FUNCTION "PMA_KONGSBERG_SORT" : VOID
TITLE = Collect Data for Kongsberg
VERSION : 0.1


VAR_TEMP
  temp_dwd : DWORD ;
END_VAR
BEGIN
NETWORK
TITLE = DG 1 Binary Points
// *** TELEGRAM 1 ***   Block 2
//  PointId = 011010   Binary Point
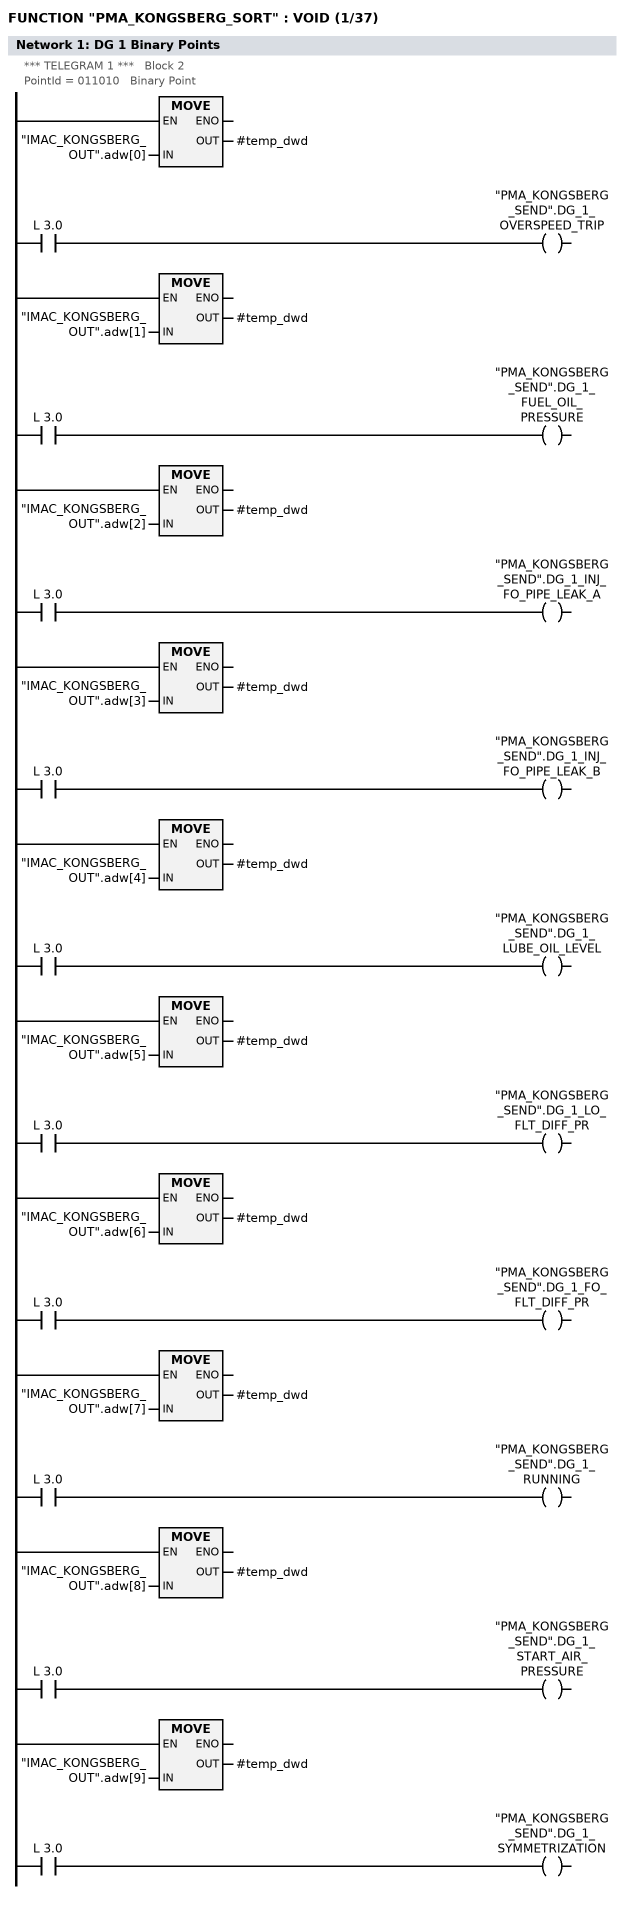
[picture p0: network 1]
      L     "IMAC_KONGSBERG_OUT".adw[0];
      T     #temp_dwd;
      U     L      3.0;
      =     "PMA_KONGSBERG_SEND".DG_1_OVERSPEED_TRIP;


// PointId = 011080   Binary Point
      L     "IMAC_KONGSBERG_OUT".adw[1];
      T     #temp_dwd;
      U     L      3.0;
      =     "PMA_KONGSBERG_SEND".DG_1_FUEL_OIL_PRESSURE;


// PointId = 011160   Binary Point
      L     "IMAC_KONGSBERG_OUT".adw[2];
      T     #temp_dwd;
      U     L      3.0;
      =     "PMA_KONGSBERG_SEND".DG_1_INJ_FO_PIPE_LEAK_A;


// PointId = 011170   Binary Point
      L     "IMAC_KONGSBERG_OUT".adw[3];
      T     #temp_dwd;
      U     L      3.0;
      =     "PMA_KONGSBERG_SEND".DG_1_INJ_FO_PIPE_LEAK_B;


// PointId = 011180   Binary Point
      L     "IMAC_KONGSBERG_OUT".adw[4];
      T     #temp_dwd;
      U     L      3.0;
      =     "PMA_KONGSBERG_SEND".DG_1_LUBE_OIL_LEVEL;


// PointId = 011200   Binary Point
      L     "IMAC_KONGSBERG_OUT".adw[5];
      T     #temp_dwd;
      U     L      3.0;
      =     "PMA_KONGSBERG_SEND".DG_1_LO_FLT_DIFF_PR;


// PointId = 011210   Binary Point
      L     "IMAC_KONGSBERG_OUT".adw[6];
      T     #temp_dwd;
      U     L      3.0;
      =     "PMA_KONGSBERG_SEND".DG_1_FO_FLT_DIFF_PR;


// PointId = 011030   Binary Point
      L     "IMAC_KONGSBERG_OUT".adw[7];
      T     #temp_dwd;
      U     L      3.0;
      =     "PMA_KONGSBERG_SEND".DG_1_RUNNING;


// PointId = 011190   Binary Point
      L     "IMAC_KONGSBERG_OUT".adw[8];
      T     #temp_dwd;
      U     L      3.0;
      =     "PMA_KONGSBERG_SEND".DG_1_START_AIR_PRESSURE;


// PointId = 011570   Binary Point
      L     "IMAC_KONGSBERG_OUT".adw[9];
      T     #temp_dwd;
      U     L      3.0;
      =     "PMA_KONGSBERG_SEND".DG_1_SYMMETRIZATION;


NETWORK
TITLE = DG 1 Analogue Points

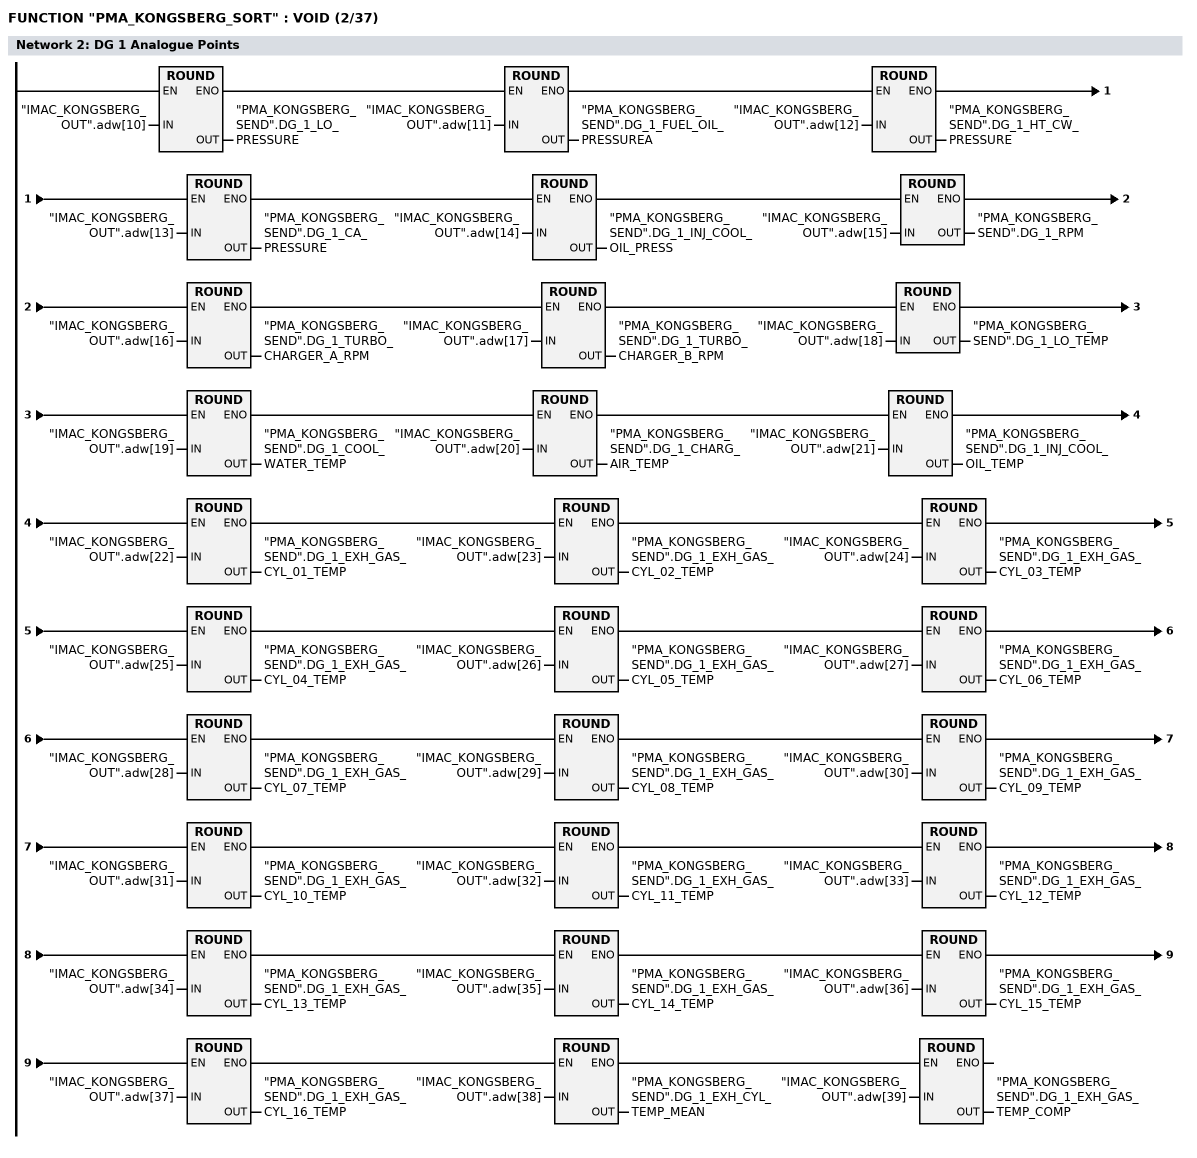
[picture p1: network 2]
// PointId = 011060   Analogue Point
      L     "IMAC_KONGSBERG_OUT".adw[10];
      RND   ;
      T     "PMA_KONGSBERG_SEND".DG_1_LO_PRESSURE;


// PointId = 011080   Analogue Point
      L     "IMAC_KONGSBERG_OUT".adw[11];
      RND   ;
      T     "PMA_KONGSBERG_SEND".DG_1_FUEL_OIL_PRESSUREA;


// PointId = 011090   Analogue Point
      L     "IMAC_KONGSBERG_OUT".adw[12];
      RND   ;
      T     "PMA_KONGSBERG_SEND".DG_1_HT_CW_PRESSURE;


// PointId = 011110   Analogue Point
      L     "IMAC_KONGSBERG_OUT".adw[13];
      RND   ;
      T     "PMA_KONGSBERG_SEND".DG_1_CA_PRESSURE;


// PointId = 011130   Analogue Point
      L     "IMAC_KONGSBERG_OUT".adw[14];
      RND   ;
      T     "PMA_KONGSBERG_SEND".DG_1_INJ_COOL_OIL_PRESS;


// PointId = 011020   Analogue Point
      L     "IMAC_KONGSBERG_OUT".adw[15];
      RND   ;
      T     "PMA_KONGSBERG_SEND".DG_1_RPM;


// PointId = 011040   Analogue Point
      L     "IMAC_KONGSBERG_OUT".adw[16];
      RND   ;
      T     "PMA_KONGSBERG_SEND".DG_1_TURBO_CHARGER_A_RPM;


// PointId = 011050   Analogue Point
      L     "IMAC_KONGSBERG_OUT".adw[17];
      RND   ;
      T     "PMA_KONGSBERG_SEND".DG_1_TURBO_CHARGER_B_RPM;


// PointId = 011070   Analogue Point
      L     "IMAC_KONGSBERG_OUT".adw[18];
      RND   ;
      T     "PMA_KONGSBERG_SEND".DG_1_LO_TEMP;


// PointId = 011100   Analogue Point
      L     "IMAC_KONGSBERG_OUT".adw[19];
      RND   ;
      T     "PMA_KONGSBERG_SEND".DG_1_COOL_WATER_TEMP;


// PointId = 011120   Analogue Point
      L     "IMAC_KONGSBERG_OUT".adw[20];
      RND   ;
      T     "PMA_KONGSBERG_SEND".DG_1_CHARG_AIR_TEMP;


// PointId = 011140   Analogue Point
      L     "IMAC_KONGSBERG_OUT".adw[21];
      RND   ;
      T     "PMA_KONGSBERG_SEND".DG_1_INJ_COOL_OIL_TEMP;


// PointId = 011230   Analogue Point
      L     "IMAC_KONGSBERG_OUT".adw[22];
      RND   ;
      T     "PMA_KONGSBERG_SEND".DG_1_EXH_GAS_CYL_01_TEMP;


// PointId = 011240   Analogue Point
      L     "IMAC_KONGSBERG_OUT".adw[23];
      RND   ;
      T     "PMA_KONGSBERG_SEND".DG_1_EXH_GAS_CYL_02_TEMP;


// PointId = 011250   Analogue Point
      L     "IMAC_KONGSBERG_OUT".adw[24];
      RND   ;
      T     "PMA_KONGSBERG_SEND".DG_1_EXH_GAS_CYL_03_TEMP;


// PointId = 011260   Analogue Point
      L     "IMAC_KONGSBERG_OUT".adw[25];
      RND   ;
      T     "PMA_KONGSBERG_SEND".DG_1_EXH_GAS_CYL_04_TEMP;


// PointId = 011270   Analogue Point
      L     "IMAC_KONGSBERG_OUT".adw[26];
      RND   ;
      T     "PMA_KONGSBERG_SEND".DG_1_EXH_GAS_CYL_05_TEMP;


// PointId = 011280   Analogue Point
      L     "IMAC_KONGSBERG_OUT".adw[27];
      RND   ;
      T     "PMA_KONGSBERG_SEND".DG_1_EXH_GAS_CYL_06_TEMP;


// PointId = 011290   Analogue Point
      L     "IMAC_KONGSBERG_OUT".adw[28];
      RND   ;
      T     "PMA_KONGSBERG_SEND".DG_1_EXH_GAS_CYL_07_TEMP;


// PointId = 011300   Analogue Point
      L     "IMAC_KONGSBERG_OUT".adw[29];
      RND   ;
      T     "PMA_KONGSBERG_SEND".DG_1_EXH_GAS_CYL_08_TEMP;


// PointId = 011310   Analogue Point
      L     "IMAC_KONGSBERG_OUT".adw[30];
      RND   ;
      T     "PMA_KONGSBERG_SEND".DG_1_EXH_GAS_CYL_09_TEMP;


// PointId = 011320   Analogue Point
      L     "IMAC_KONGSBERG_OUT".adw[31];
      RND   ;
      T     "PMA_KONGSBERG_SEND".DG_1_EXH_GAS_CYL_10_TEMP;


// PointId = 011330   Analogue Point
      L     "IMAC_KONGSBERG_OUT".adw[32];
      RND   ;
      T     "PMA_KONGSBERG_SEND".DG_1_EXH_GAS_CYL_11_TEMP;


// PointId = 011340   Analogue Point
      L     "IMAC_KONGSBERG_OUT".adw[33];
      RND   ;
      T     "PMA_KONGSBERG_SEND".DG_1_EXH_GAS_CYL_12_TEMP;


// PointId = 011350   Analogue Point
      L     "IMAC_KONGSBERG_OUT".adw[34];
      RND   ;
      T     "PMA_KONGSBERG_SEND".DG_1_EXH_GAS_CYL_13_TEMP;


// PointId = 011360   Analogue Point
      L     "IMAC_KONGSBERG_OUT".adw[35];
      RND   ;
      T     "PMA_KONGSBERG_SEND".DG_1_EXH_GAS_CYL_14_TEMP;


// PointId = 011370   Analogue Point
      L     "IMAC_KONGSBERG_OUT".adw[36];
      RND   ;
      T     "PMA_KONGSBERG_SEND".DG_1_EXH_GAS_CYL_15_TEMP;


// PointId = 011380   Analogue Point
      L     "IMAC_KONGSBERG_OUT".adw[37];
      RND   ;
      T     "PMA_KONGSBERG_SEND".DG_1_EXH_GAS_CYL_16_TEMP;


// PointId = 011550   Analogue Point
      L     "IMAC_KONGSBERG_OUT".adw[38];
      RND   ;
      T     "PMA_KONGSBERG_SEND".DG_1_EXH_CYL_TEMP_MEAN;


// PointId = 011560   Analogue Point
      L     "IMAC_KONGSBERG_OUT".adw[39];
      RND   ;
      T     "PMA_KONGSBERG_SEND".DG_1_EXH_GAS_TEMP_COMP;
NETWORK
TITLE = DG 2 Binary Points
// *** TELEGRAM 1 ***   Block 3
//  PointId = 012010   Binary Point
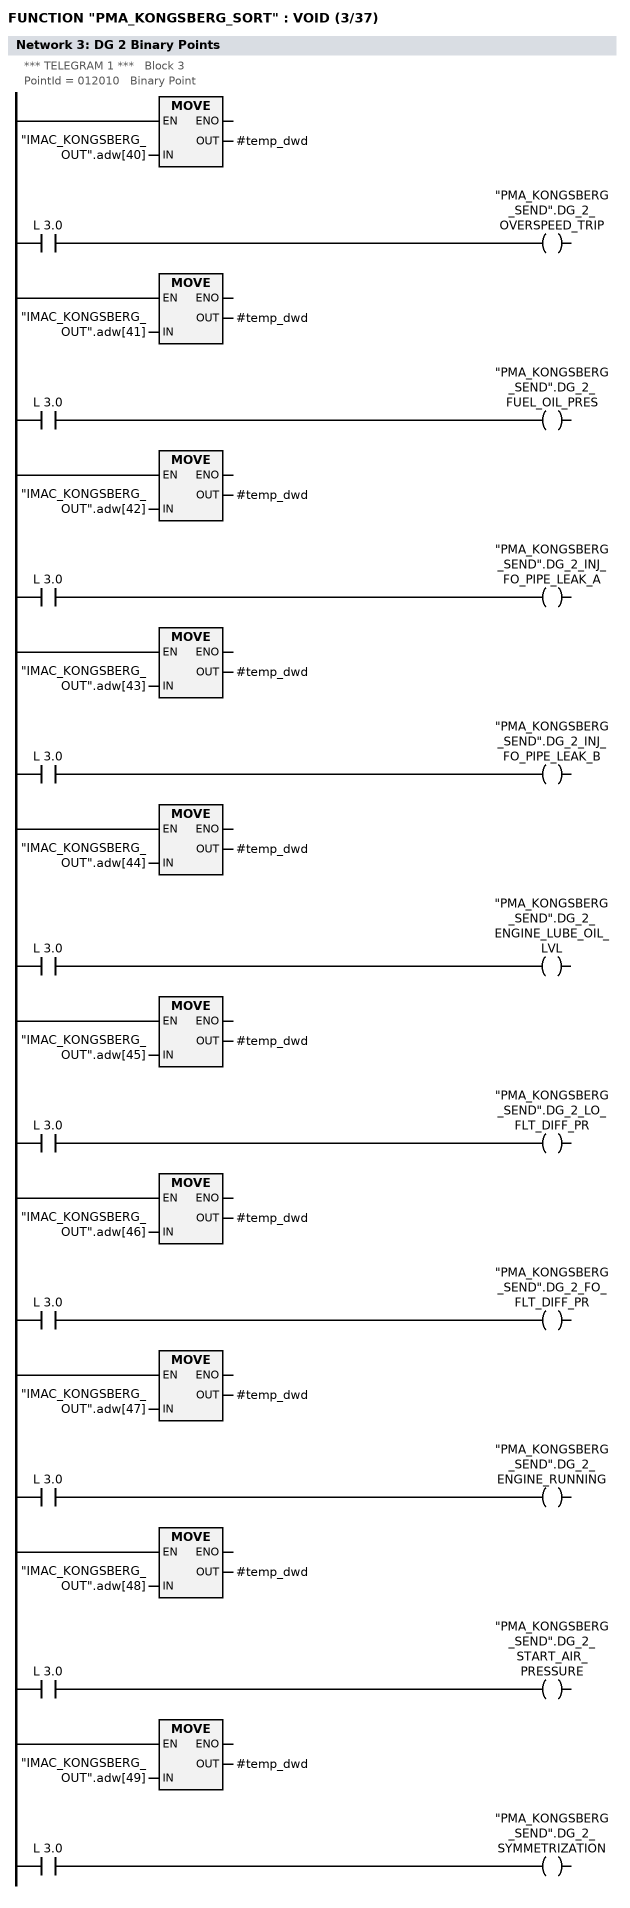
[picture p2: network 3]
      L     "IMAC_KONGSBERG_OUT".adw[40];
      T     #temp_dwd;
      U     L      3.0;
      =     "PMA_KONGSBERG_SEND".DG_2_OVERSPEED_TRIP;


// PointId = 012080   Binary Point
      L     "IMAC_KONGSBERG_OUT".adw[41];
      T     #temp_dwd;
      U     L      3.0;
      =     "PMA_KONGSBERG_SEND".DG_2_FUEL_OIL_PRES;


// PointId = 012160   Binary Point
      L     "IMAC_KONGSBERG_OUT".adw[42];
      T     #temp_dwd;
      U     L      3.0;
      =     "PMA_KONGSBERG_SEND".DG_2_INJ_FO_PIPE_LEAK_A;


// PointId = 012170   Binary Point
      L     "IMAC_KONGSBERG_OUT".adw[43];
      T     #temp_dwd;
      U     L      3.0;
      =     "PMA_KONGSBERG_SEND".DG_2_INJ_FO_PIPE_LEAK_B;


// PointId = 012180   Binary Point
      L     "IMAC_KONGSBERG_OUT".adw[44];
      T     #temp_dwd;
      U     L      3.0;
      =     "PMA_KONGSBERG_SEND".DG_2_ENGINE_LUBE_OIL_LVL;


// PointId = 012200   Binary Point
      L     "IMAC_KONGSBERG_OUT".adw[45];
      T     #temp_dwd;
      U     L      3.0;
      =     "PMA_KONGSBERG_SEND".DG_2_LO_FLT_DIFF_PR;


// PointId = 012210   Binary Point
      L     "IMAC_KONGSBERG_OUT".adw[46];
      T     #temp_dwd;
      U     L      3.0;
      =     "PMA_KONGSBERG_SEND".DG_2_FO_FLT_DIFF_PR;


// PointId = 012030   Binary Point
      L     "IMAC_KONGSBERG_OUT".adw[47];
      T     #temp_dwd;
      U     L      3.0;
      =     "PMA_KONGSBERG_SEND".DG_2_ENGINE_RUNNING;


// PointId = 012190   Binary Point
      L     "IMAC_KONGSBERG_OUT".adw[48];
      T     #temp_dwd;
      U     L      3.0;
      =     "PMA_KONGSBERG_SEND".DG_2_START_AIR_PRESSURE;


// PointId = 012570   Binary Point
      L     "IMAC_KONGSBERG_OUT".adw[49];
      T     #temp_dwd;
      U     L      3.0;
      =     "PMA_KONGSBERG_SEND".DG_2_SYMMETRIZATION;
NETWORK
TITLE = DG 2 Analogue Points

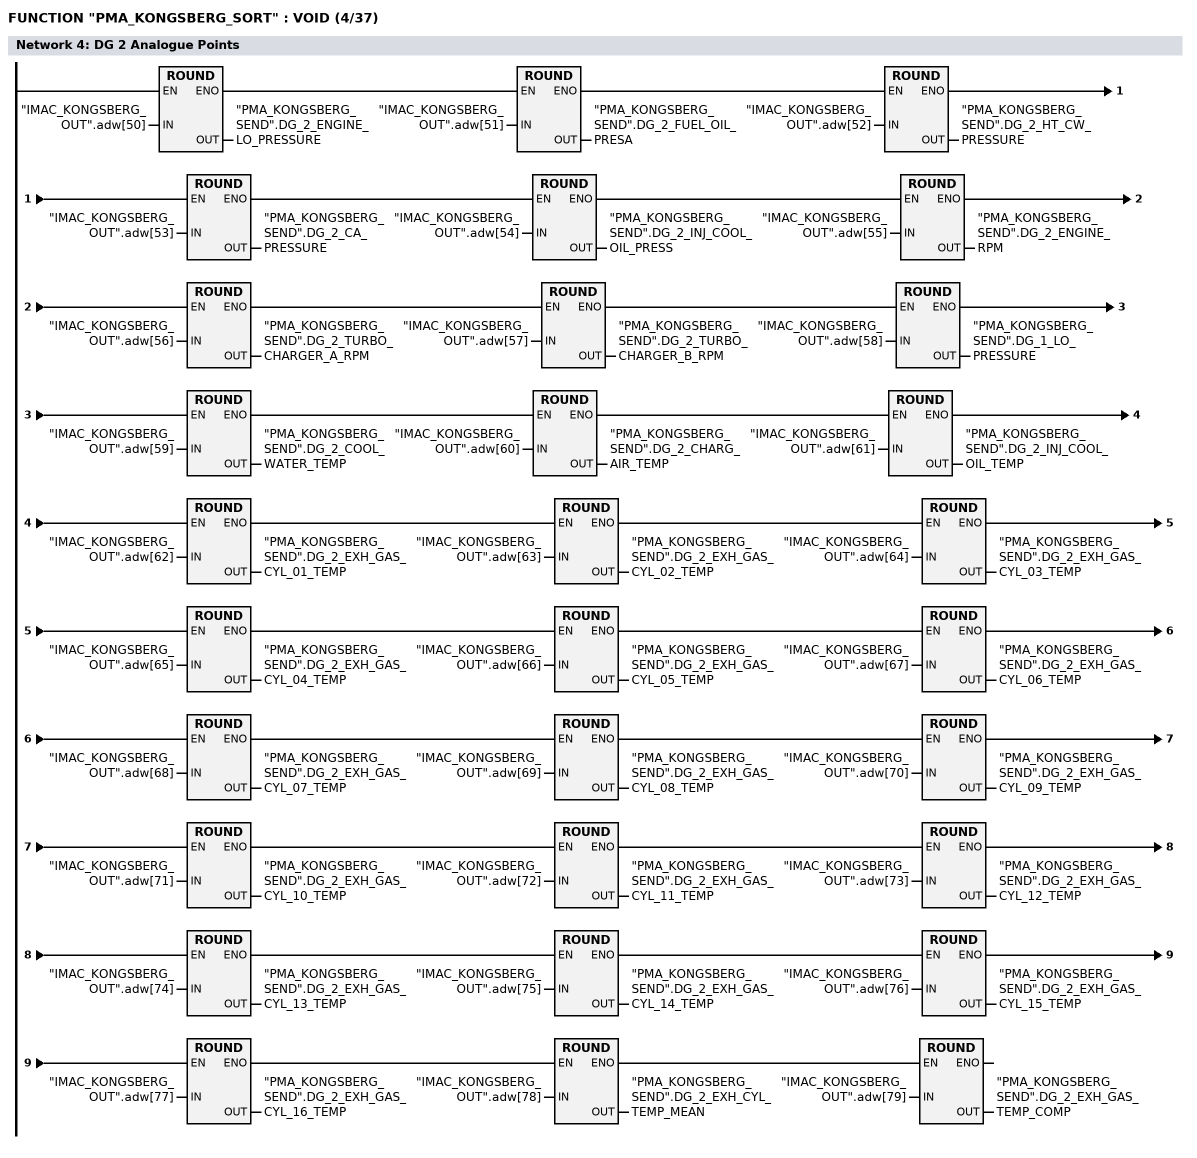
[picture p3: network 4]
//  PointId = 012060   Analogue Point
      L     "IMAC_KONGSBERG_OUT".adw[50];
      RND   ;
      T     "PMA_KONGSBERG_SEND".DG_2_ENGINE_LO_PRESSURE;


// PointId = 012080   Analogue Point
      L     "IMAC_KONGSBERG_OUT".adw[51];
      RND   ;
      T     "PMA_KONGSBERG_SEND".DG_2_FUEL_OIL_PRESA;


// PointId = 012090   Analogue Point
      L     "IMAC_KONGSBERG_OUT".adw[52];
      RND   ;
      T     "PMA_KONGSBERG_SEND".DG_2_HT_CW_PRESSURE;


// PointId = 012110   Analogue Point
      L     "IMAC_KONGSBERG_OUT".adw[53];
      RND   ;
      T     "PMA_KONGSBERG_SEND".DG_2_CA_PRESSURE;


// PointId = 012130   Analogue Point
      L     "IMAC_KONGSBERG_OUT".adw[54];
      RND   ;
      T     "PMA_KONGSBERG_SEND".DG_2_INJ_COOL_OIL_PRESS;


// PointId = 012020   Analogue Point
      L     "IMAC_KONGSBERG_OUT".adw[55];
      RND   ;
      T     "PMA_KONGSBERG_SEND".DG_2_ENGINE_RPM;


// PointId = 012040   Analogue Point
      L     "IMAC_KONGSBERG_OUT".adw[56];
      RND   ;
      T     "PMA_KONGSBERG_SEND".DG_2_TURBO_CHARGER_A_RPM;


// PointId = 012050   Analogue Point
      L     "IMAC_KONGSBERG_OUT".adw[57];
      RND   ;
      T     "PMA_KONGSBERG_SEND".DG_2_TURBO_CHARGER_B_RPM;


// PointId = 012070   Analogue Point
      L     "IMAC_KONGSBERG_OUT".adw[58];
      RND   ;
      T     "PMA_KONGSBERG_SEND".DG_1_LO_PRESSURE;


// PointId = 012100   Analogue Point
      L     "IMAC_KONGSBERG_OUT".adw[59];
      RND   ;
      T     "PMA_KONGSBERG_SEND".DG_2_COOL_WATER_TEMP;


// PointId = 012120   Analogue Point
      L     "IMAC_KONGSBERG_OUT".adw[60];
      RND   ;
      T     "PMA_KONGSBERG_SEND".DG_2_CHARG_AIR_TEMP;


// PointId = 012140   Analogue Point
      L     "IMAC_KONGSBERG_OUT".adw[61];
      RND   ;
      T     "PMA_KONGSBERG_SEND".DG_2_INJ_COOL_OIL_TEMP;


// PointId = 012230   Analogue Point
      L     "IMAC_KONGSBERG_OUT".adw[62];
      RND   ;
      T     "PMA_KONGSBERG_SEND".DG_2_EXH_GAS_CYL_01_TEMP;


// PointId = 012240   Analogue Point
      L     "IMAC_KONGSBERG_OUT".adw[63];
      RND   ;
      T     "PMA_KONGSBERG_SEND".DG_2_EXH_GAS_CYL_02_TEMP;


// PointId = 012250   Analogue Point
      L     "IMAC_KONGSBERG_OUT".adw[64];
      RND   ;
      T     "PMA_KONGSBERG_SEND".DG_2_EXH_GAS_CYL_03_TEMP;


// PointId = 012260   Analogue Point
      L     "IMAC_KONGSBERG_OUT".adw[65];
      RND   ;
      T     "PMA_KONGSBERG_SEND".DG_2_EXH_GAS_CYL_04_TEMP;


// PointId = 012270   Analogue Point
      L     "IMAC_KONGSBERG_OUT".adw[66];
      RND   ;
      T     "PMA_KONGSBERG_SEND".DG_2_EXH_GAS_CYL_05_TEMP;


// PointId = 012280   Analogue Point
      L     "IMAC_KONGSBERG_OUT".adw[67];
      RND   ;
      T     "PMA_KONGSBERG_SEND".DG_2_EXH_GAS_CYL_06_TEMP;


// PointId = 012290   Analogue Point
      L     "IMAC_KONGSBERG_OUT".adw[68];
      RND   ;
      T     "PMA_KONGSBERG_SEND".DG_2_EXH_GAS_CYL_07_TEMP;


// PointId = 012300   Analogue Point
      L     "IMAC_KONGSBERG_OUT".adw[69];
      RND   ;
      T     "PMA_KONGSBERG_SEND".DG_2_EXH_GAS_CYL_08_TEMP;


// PointId = 012310   Analogue Point
      L     "IMAC_KONGSBERG_OUT".adw[70];
      RND   ;
      T     "PMA_KONGSBERG_SEND".DG_2_EXH_GAS_CYL_09_TEMP;


// PointId = 012320   Analogue Point
      L     "IMAC_KONGSBERG_OUT".adw[71];
      RND   ;
      T     "PMA_KONGSBERG_SEND".DG_2_EXH_GAS_CYL_10_TEMP;


// PointId = 012330   Analogue Point
      L     "IMAC_KONGSBERG_OUT".adw[72];
      RND   ;
      T     "PMA_KONGSBERG_SEND".DG_2_EXH_GAS_CYL_11_TEMP;


// PointId = 012340   Analogue Point
      L     "IMAC_KONGSBERG_OUT".adw[73];
      RND   ;
      T     "PMA_KONGSBERG_SEND".DG_2_EXH_GAS_CYL_12_TEMP;


// PointId = 012350   Analogue Point
      L     "IMAC_KONGSBERG_OUT".adw[74];
      RND   ;
      T     "PMA_KONGSBERG_SEND".DG_2_EXH_GAS_CYL_13_TEMP;


// PointId = 012360   Analogue Point
      L     "IMAC_KONGSBERG_OUT".adw[75];
      RND   ;
      T     "PMA_KONGSBERG_SEND".DG_2_EXH_GAS_CYL_14_TEMP;


// PointId = 012370   Analogue Point
      L     "IMAC_KONGSBERG_OUT".adw[76];
      RND   ;
      T     "PMA_KONGSBERG_SEND".DG_2_EXH_GAS_CYL_15_TEMP;


// PointId = 012380   Analogue Point
      L     "IMAC_KONGSBERG_OUT".adw[77];
      RND   ;
      T     "PMA_KONGSBERG_SEND".DG_2_EXH_GAS_CYL_16_TEMP;


// PointId = 012550   Analogue Point
      L     "IMAC_KONGSBERG_OUT".adw[78];
      RND   ;
      T     "PMA_KONGSBERG_SEND".DG_2_EXH_CYL_TEMP_MEAN;


// PointId = 012560   Analogue Point
      L     "IMAC_KONGSBERG_OUT".adw[79];
      RND   ;
      T     "PMA_KONGSBERG_SEND".DG_2_EXH_GAS_TEMP_COMP;
NETWORK
TITLE = GEN 1 Analogue Points
// *** TELEGRAM 1 ***   Block 4
// PointId = 021010   Analogue Point
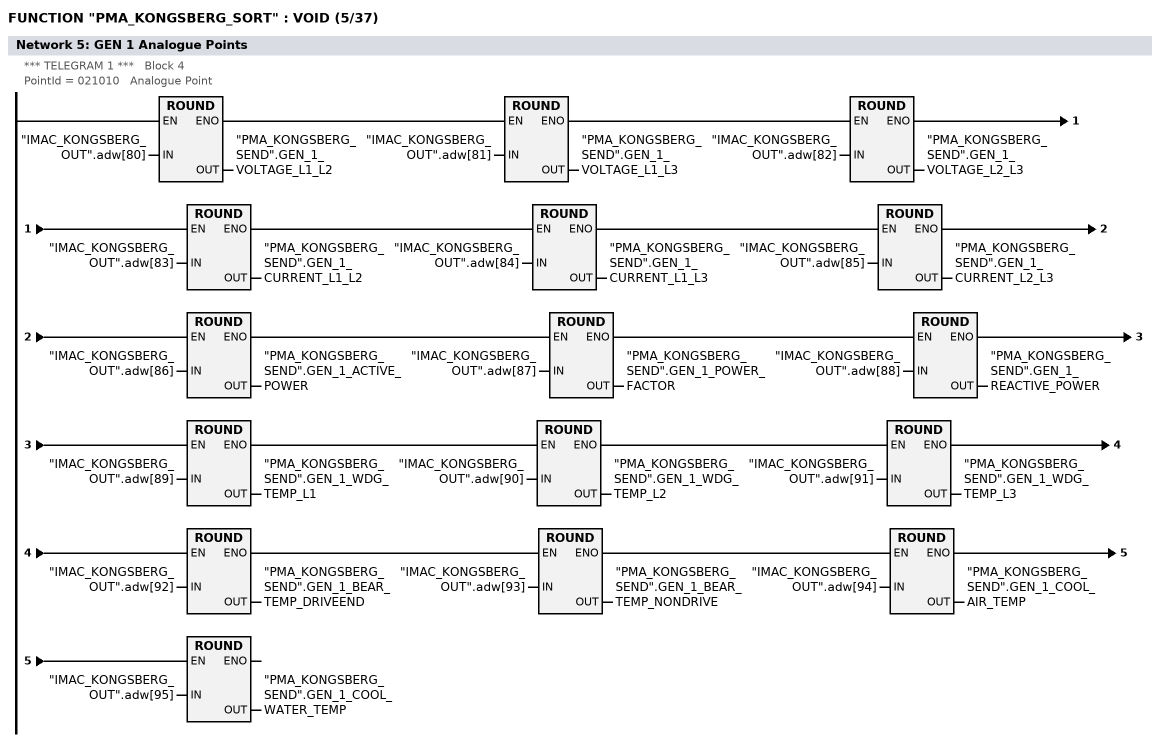
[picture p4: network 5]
      L     "IMAC_KONGSBERG_OUT".adw[80];
      RND   ;
      T     "PMA_KONGSBERG_SEND".GEN_1_VOLTAGE_L1_L2;


// PointId = 021020   Analogue Point
      L     "IMAC_KONGSBERG_OUT".adw[81];
      RND   ;
      T     "PMA_KONGSBERG_SEND".GEN_1_VOLTAGE_L1_L3;


// PointId = 021030   Analogue Point
      L     "IMAC_KONGSBERG_OUT".adw[82];
      RND   ;
      T     "PMA_KONGSBERG_SEND".GEN_1_VOLTAGE_L2_L3;


// PointId = 021040   Analogue Point
      L     "IMAC_KONGSBERG_OUT".adw[83];
      RND   ;
      T     "PMA_KONGSBERG_SEND".GEN_1_CURRENT_L1_L2;


// PointId = 021051   Analogue Point
      L     "IMAC_KONGSBERG_OUT".adw[84];
      RND   ;
      T     "PMA_KONGSBERG_SEND".GEN_1_CURRENT_L1_L3;


// PointId = 021060   Analogue Point
      L     "IMAC_KONGSBERG_OUT".adw[85];
      RND   ;
      T     "PMA_KONGSBERG_SEND".GEN_1_CURRENT_L2_L3;


// PointId = 021070   Analogue Point
      L     "IMAC_KONGSBERG_OUT".adw[86];
      RND   ;
      T     "PMA_KONGSBERG_SEND".GEN_1_ACTIVE_POWER;


// PointId = 021080   Analogue Point
      L     "IMAC_KONGSBERG_OUT".adw[87];
      RND   ;
      T     "PMA_KONGSBERG_SEND".GEN_1_POWER_FACTOR;


// PointId = 021090   Analogue Point
      L     "IMAC_KONGSBERG_OUT".adw[88];
      RND   ;
      T     "PMA_KONGSBERG_SEND".GEN_1_REACTIVE_POWER;


// PointId = 021120   Analogue Point
      L     "IMAC_KONGSBERG_OUT".adw[89];
      RND   ;
      T     "PMA_KONGSBERG_SEND".GEN_1_WDG_TEMP_L1;


// PointId = 021130   Analogue Point
      L     "IMAC_KONGSBERG_OUT".adw[90];
      RND   ;
      T     "PMA_KONGSBERG_SEND".GEN_1_WDG_TEMP_L2;


// PointId = 021140   Analogue Point
      L     "IMAC_KONGSBERG_OUT".adw[91];
      RND   ;
      T     "PMA_KONGSBERG_SEND".GEN_1_WDG_TEMP_L3;


// PointId = 021150   Analogue Point
      L     "IMAC_KONGSBERG_OUT".adw[92];
      RND   ;
      T     "PMA_KONGSBERG_SEND".GEN_1_BEAR_TEMP_DRIVEEND;


// PointId = 021160   Analogue Point
      L     "IMAC_KONGSBERG_OUT".adw[93];
      RND   ;
      T     "PMA_KONGSBERG_SEND".GEN_1_BEAR_TEMP_NONDRIVE;


// PointId = 021170   Analogue Point
      L     "IMAC_KONGSBERG_OUT".adw[94];
      RND   ;
      T     "PMA_KONGSBERG_SEND".GEN_1_COOL_AIR_TEMP;


// PointId = 021180   Analogue Point
      L     "IMAC_KONGSBERG_OUT".adw[95];
      RND   ;
      T     "PMA_KONGSBERG_SEND".GEN_1_COOL_WATER_TEMP;
NETWORK
TITLE = GEN 1 Binary Points
// *** TELEGRAM 1 ***   Block 5
// PointId = 021100   Binary Point
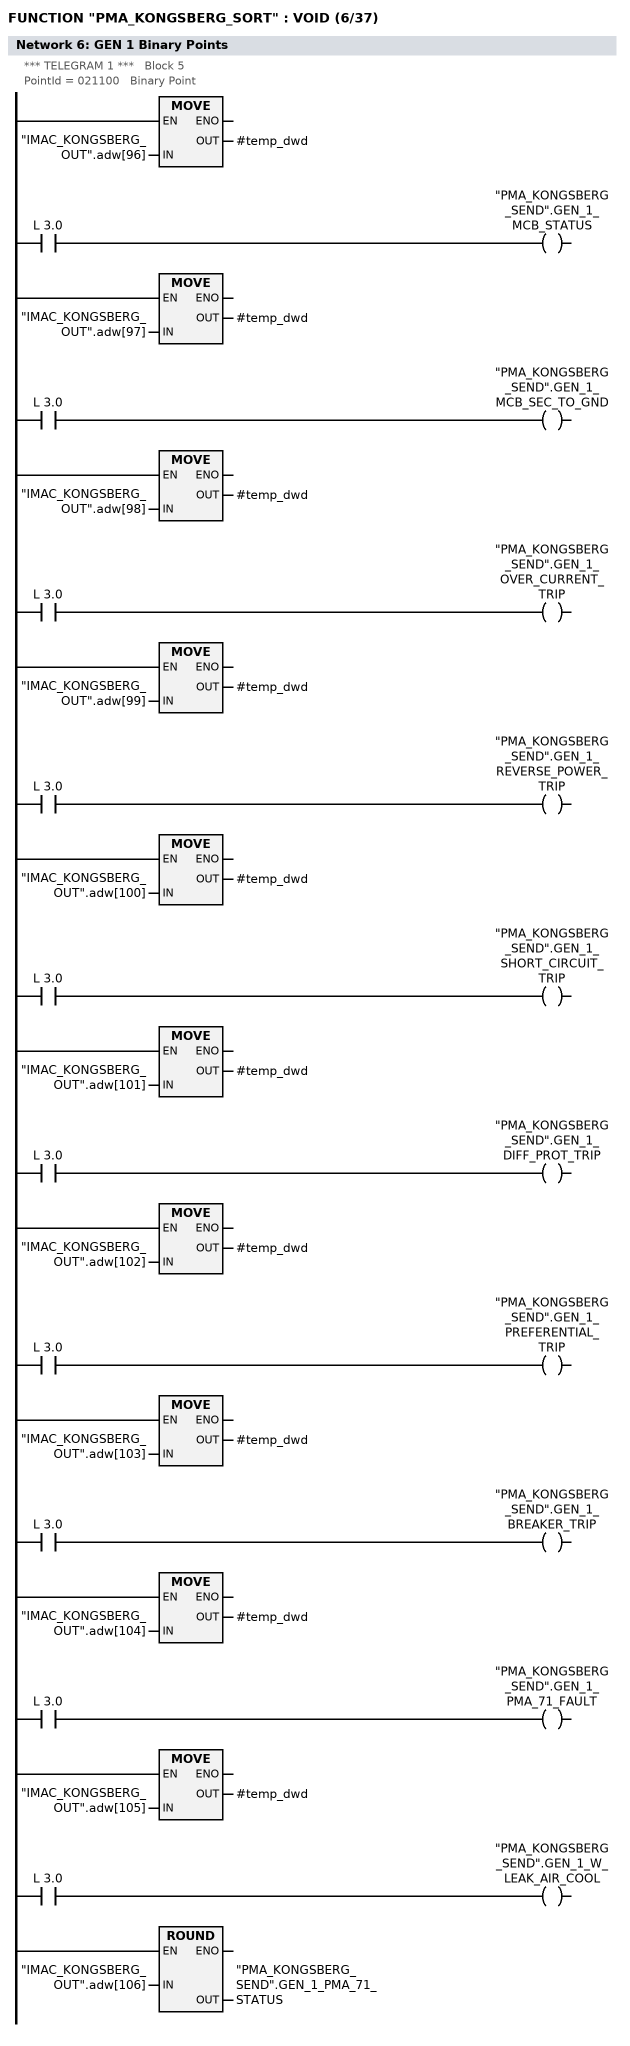
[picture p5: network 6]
      L     "IMAC_KONGSBERG_OUT".adw[96];
      T     #temp_dwd;
      U     L      3.0;
      =     "PMA_KONGSBERG_SEND".GEN_1_MCB_STATUS;


// PointId = 021110   Binary Point
      L     "IMAC_KONGSBERG_OUT".adw[97];
      T     #temp_dwd;
      U     L      3.0;
      =     "PMA_KONGSBERG_SEND".GEN_1_MCB_SEC_TO_GND;


// PointId = 021190   Binary Point
      L     "IMAC_KONGSBERG_OUT".adw[98];
      T     #temp_dwd;
      U     L      3.0;
      =     "PMA_KONGSBERG_SEND".GEN_1_OVER_CURRENT_TRIP;


// PointId = 021200   Binary Point
      L     "IMAC_KONGSBERG_OUT".adw[99];
      T     #temp_dwd;
      U     L      3.0;
      =     "PMA_KONGSBERG_SEND".GEN_1_REVERSE_POWER_TRIP;


// PointId = 021210   Binary Point
      L     "IMAC_KONGSBERG_OUT".adw[100];
      T     #temp_dwd;
      U     L      3.0;
      =     "PMA_KONGSBERG_SEND".GEN_1_SHORT_CIRCUIT_TRIP;


// PointId = 021240   Binary Point
      L     "IMAC_KONGSBERG_OUT".adw[101];
      T     #temp_dwd;
      U     L      3.0;
      =     "PMA_KONGSBERG_SEND".GEN_1_DIFF_PROT_TRIP;


// PointId = 021260   Binary Point
      L     "IMAC_KONGSBERG_OUT".adw[102];
      T     #temp_dwd;
      U     L      3.0;
      =     "PMA_KONGSBERG_SEND".GEN_1_PREFERENTIAL_TRIP;


// PointId = 021270   Binary Point
      L     "IMAC_KONGSBERG_OUT".adw[103];
      T     #temp_dwd;
      U     L      3.0;
      =     "PMA_KONGSBERG_SEND".GEN_1_BREAKER_TRIP;


// PointId = 021290   Binary Point
      L     "IMAC_KONGSBERG_OUT".adw[104];
      T     #temp_dwd;
      U     L      3.0;
      =     "PMA_KONGSBERG_SEND".GEN_1_PMA_71_FAULT;


// PointId = 021310   Binary Point
      L     "IMAC_KONGSBERG_OUT".adw[105];
      T     #temp_dwd;
      U     L      3.0;
      =     "PMA_KONGSBERG_SEND".GEN_1_W_LEAK_AIR_COOL;


// PointId = 021300   Analogue Point
      L     "IMAC_KONGSBERG_OUT".adw[106];
      RND   ;
      T     "PMA_KONGSBERG_SEND".GEN_1_PMA_71_STATUS;
NETWORK
TITLE = GEN 2 Analogue Points
//  *** TELEGRAM 1 ***   Block 6
// PointId = 022010   Analogue Point
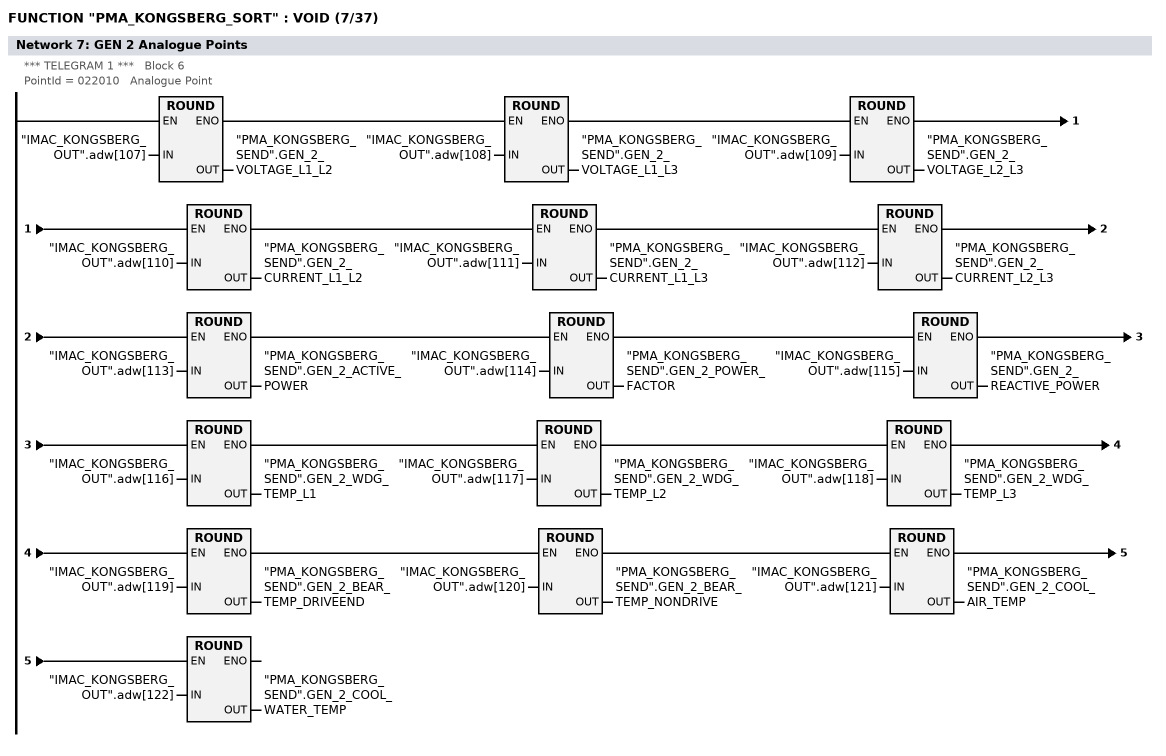
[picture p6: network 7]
      L     "IMAC_KONGSBERG_OUT".adw[107];
      RND   ;
      T     "PMA_KONGSBERG_SEND".GEN_2_VOLTAGE_L1_L2;


// PointId = 022020   Analogue Point
      L     "IMAC_KONGSBERG_OUT".adw[108];
      RND   ;
      T     "PMA_KONGSBERG_SEND".GEN_2_VOLTAGE_L1_L3;


// PointId = 022030   Analogue Point
      L     "IMAC_KONGSBERG_OUT".adw[109];
      RND   ;
      T     "PMA_KONGSBERG_SEND".GEN_2_VOLTAGE_L2_L3;


// PointId = 022040   Analogue Point
      L     "IMAC_KONGSBERG_OUT".adw[110];
      RND   ;
      T     "PMA_KONGSBERG_SEND".GEN_2_CURRENT_L1_L2;


// PointId = 022051   Analogue Point
      L     "IMAC_KONGSBERG_OUT".adw[111];
      RND   ;
      T     "PMA_KONGSBERG_SEND".GEN_2_CURRENT_L1_L3;


// PointId = 022060   Analogue Point
      L     "IMAC_KONGSBERG_OUT".adw[112];
      RND   ;
      T     "PMA_KONGSBERG_SEND".GEN_2_CURRENT_L2_L3;


// PointId = 022070   Analogue Point
      L     "IMAC_KONGSBERG_OUT".adw[113];
      RND   ;
      T     "PMA_KONGSBERG_SEND".GEN_2_ACTIVE_POWER;


// PointId = 022080   Analogue Point
      L     "IMAC_KONGSBERG_OUT".adw[114];
      RND   ;
      T     "PMA_KONGSBERG_SEND".GEN_2_POWER_FACTOR;


// PointId = 022090   Analogue Point
      L     "IMAC_KONGSBERG_OUT".adw[115];
      RND   ;
      T     "PMA_KONGSBERG_SEND".GEN_2_REACTIVE_POWER;


// PointId = 022120   Analogue Point
      L     "IMAC_KONGSBERG_OUT".adw[116];
      RND   ;
      T     "PMA_KONGSBERG_SEND".GEN_2_WDG_TEMP_L1;


// PointId = 022130   Analogue Point
      L     "IMAC_KONGSBERG_OUT".adw[117];
      RND   ;
      T     "PMA_KONGSBERG_SEND".GEN_2_WDG_TEMP_L2;


// PointId = 022140   Analogue Point
      L     "IMAC_KONGSBERG_OUT".adw[118];
      RND   ;
      T     "PMA_KONGSBERG_SEND".GEN_2_WDG_TEMP_L3;


// PointId = 022150   Analogue Point
      L     "IMAC_KONGSBERG_OUT".adw[119];
      RND   ;
      T     "PMA_KONGSBERG_SEND".GEN_2_BEAR_TEMP_DRIVEEND;


// PointId = 022160   Analogue Point
      L     "IMAC_KONGSBERG_OUT".adw[120];
      RND   ;
      T     "PMA_KONGSBERG_SEND".GEN_2_BEAR_TEMP_NONDRIVE;


// PointId = 022170   Analogue Point
      L     "IMAC_KONGSBERG_OUT".adw[121];
      RND   ;
      T     "PMA_KONGSBERG_SEND".GEN_2_COOL_AIR_TEMP;


// PointId = 022180   Analogue Point
      L     "IMAC_KONGSBERG_OUT".adw[122];
      RND   ;
      T     "PMA_KONGSBERG_SEND".GEN_2_COOL_WATER_TEMP;
NETWORK
TITLE = GEN 2 Binary Points
// *** TELEGRAM 1 ***   Block 7
// PointId = 022100   Binary Point
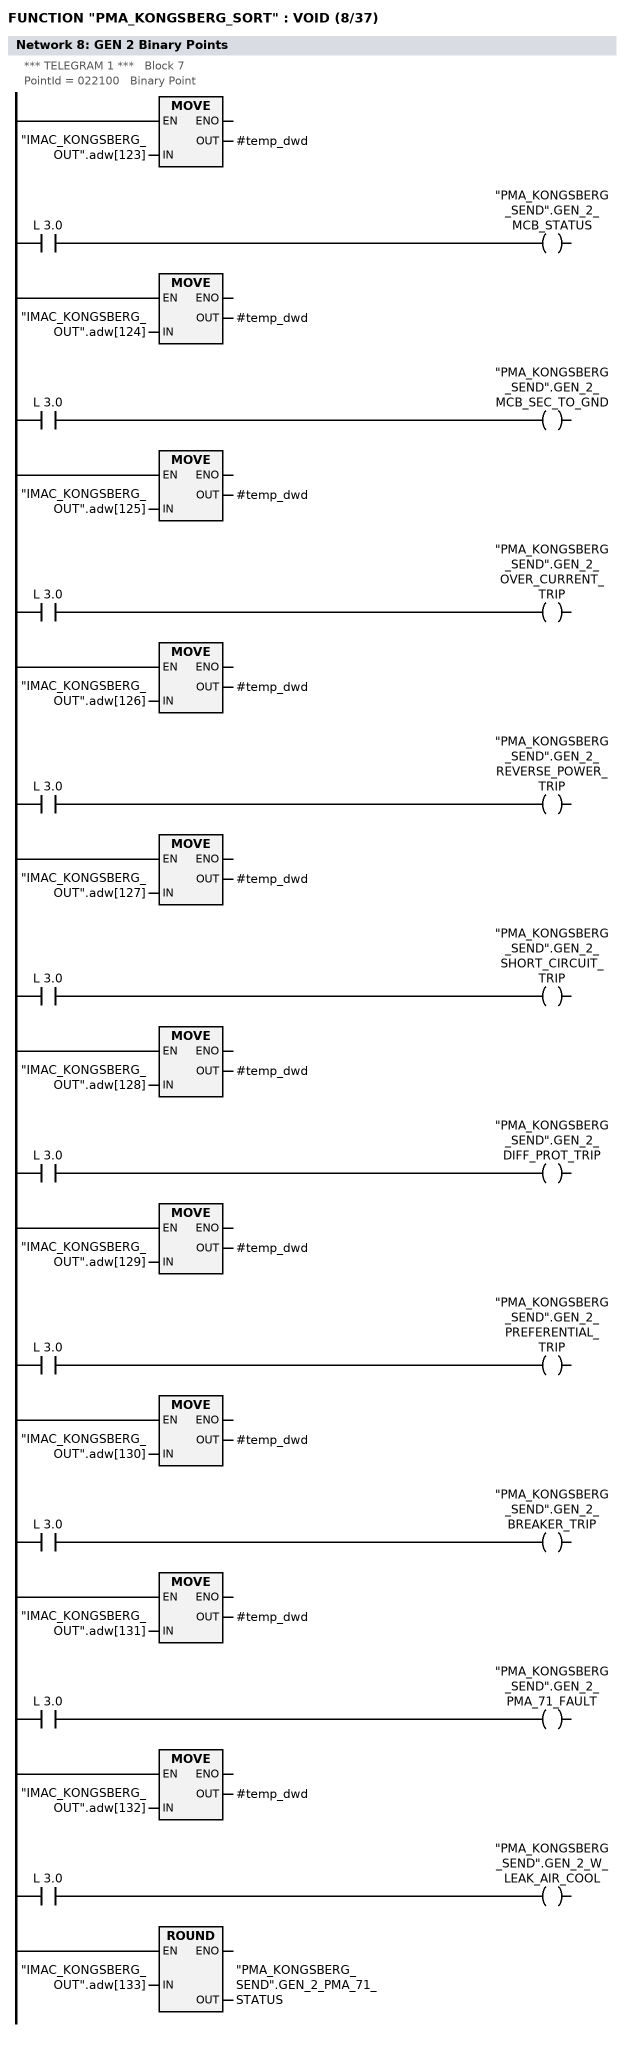
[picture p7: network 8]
      L     "IMAC_KONGSBERG_OUT".adw[123];
      T     #temp_dwd;
      U     L      3.0;
      =     "PMA_KONGSBERG_SEND".GEN_2_MCB_STATUS;


// PointId = 022110   Binary Point
      L     "IMAC_KONGSBERG_OUT".adw[124];
      T     #temp_dwd;
      U     L      3.0;
      =     "PMA_KONGSBERG_SEND".GEN_2_MCB_SEC_TO_GND;


// PointId = 022190   Binary Point
      L     "IMAC_KONGSBERG_OUT".adw[125];
      T     #temp_dwd;
      U     L      3.0;
      =     "PMA_KONGSBERG_SEND".GEN_2_OVER_CURRENT_TRIP;


// PointId = 022200   Binary Point
      L     "IMAC_KONGSBERG_OUT".adw[126];
      T     #temp_dwd;
      U     L      3.0;
      =     "PMA_KONGSBERG_SEND".GEN_2_REVERSE_POWER_TRIP;


// PointId = 022210   Binary Point
      L     "IMAC_KONGSBERG_OUT".adw[127];
      T     #temp_dwd;
      U     L      3.0;
      =     "PMA_KONGSBERG_SEND".GEN_2_SHORT_CIRCUIT_TRIP;


// PointId = 022240   Binary Point
      L     "IMAC_KONGSBERG_OUT".adw[128];
      T     #temp_dwd;
      U     L      3.0;
      =     "PMA_KONGSBERG_SEND".GEN_2_DIFF_PROT_TRIP;


// PointId = 022260   Binary Point
      L     "IMAC_KONGSBERG_OUT".adw[129];
      T     #temp_dwd;
      U     L      3.0;
      =     "PMA_KONGSBERG_SEND".GEN_2_PREFERENTIAL_TRIP;


// PointId = 022270   Binary Point
      L     "IMAC_KONGSBERG_OUT".adw[130];
      T     #temp_dwd;
      U     L      3.0;
      =     "PMA_KONGSBERG_SEND".GEN_2_BREAKER_TRIP;


// PointId = 022290   Binary Point
      L     "IMAC_KONGSBERG_OUT".adw[131];
      T     #temp_dwd;
      U     L      3.0;
      =     "PMA_KONGSBERG_SEND".GEN_2_PMA_71_FAULT;


// PointId = 022310   Binary Point
      L     "IMAC_KONGSBERG_OUT".adw[132];
      T     #temp_dwd;
      U     L      3.0;
      =     "PMA_KONGSBERG_SEND".GEN_2_W_LEAK_AIR_COOL;


// PointId = 022300   Analogue Point
      L     "IMAC_KONGSBERG_OUT".adw[133];
      RND   ;
      T     "PMA_KONGSBERG_SEND".GEN_2_PMA_71_STATUS;
NETWORK
TITLE = DG 3 Binary Points
// *** TELEGRAM 2 ***   Block 2
// PointId = 013010   Binary Point
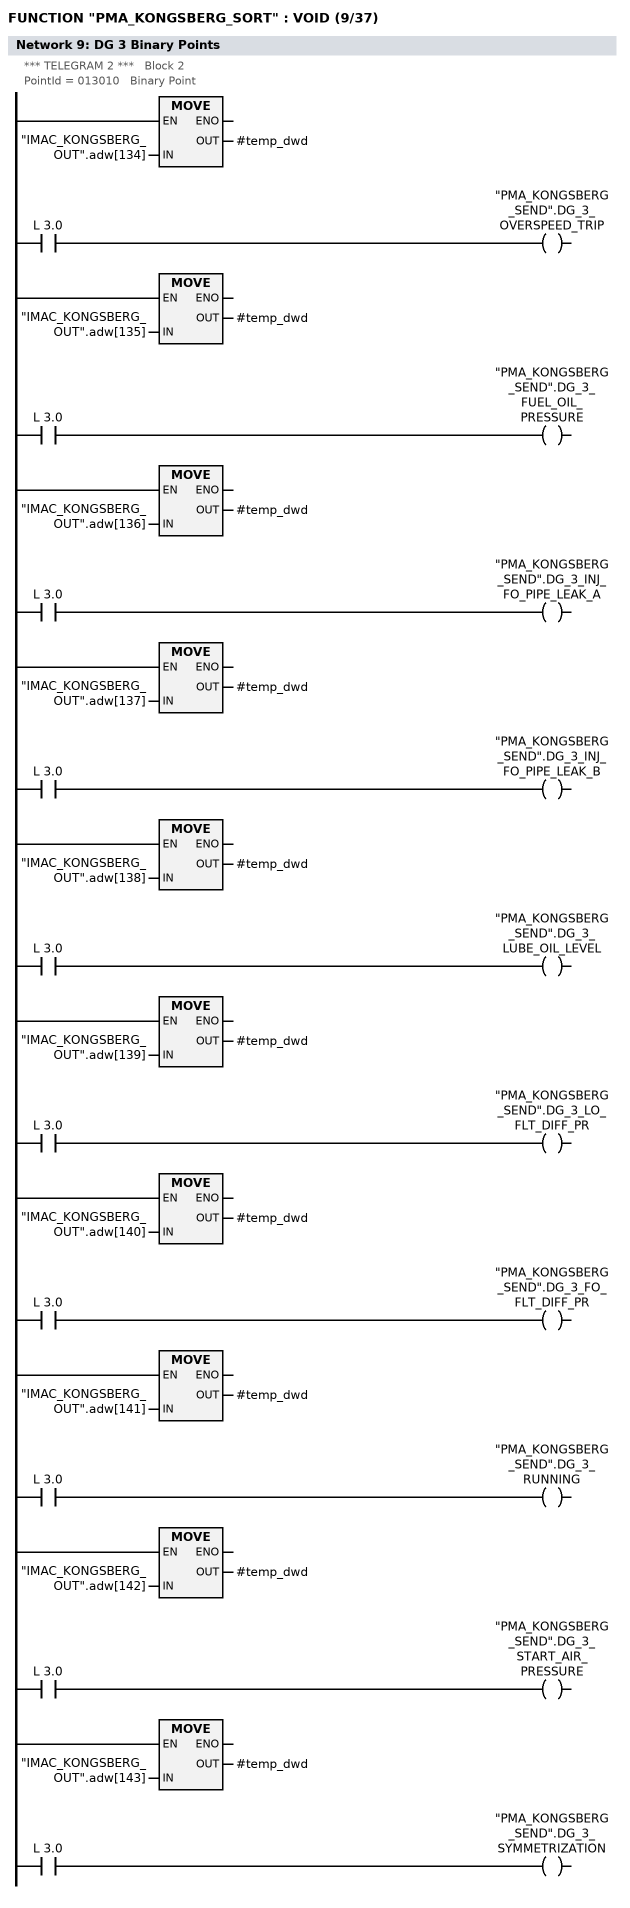
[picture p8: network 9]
      L     "IMAC_KONGSBERG_OUT".adw[134];
      T     #temp_dwd;
      U     L      3.0;
      =     "PMA_KONGSBERG_SEND".DG_3_OVERSPEED_TRIP;


// PointId = 013080   Binary Point
      L     "IMAC_KONGSBERG_OUT".adw[135];
      T     #temp_dwd;
      U     L      3.0;
      =     "PMA_KONGSBERG_SEND".DG_3_FUEL_OIL_PRESSURE;


// PointId = 013160   Binary Point
      L     "IMAC_KONGSBERG_OUT".adw[136];
      T     #temp_dwd;
      U     L      3.0;
      =     "PMA_KONGSBERG_SEND".DG_3_INJ_FO_PIPE_LEAK_A;


// PointId = 013170   Binary Point
      L     "IMAC_KONGSBERG_OUT".adw[137];
      T     #temp_dwd;
      U     L      3.0;
      =     "PMA_KONGSBERG_SEND".DG_3_INJ_FO_PIPE_LEAK_B;


// PointId = 013180   Binary Point
      L     "IMAC_KONGSBERG_OUT".adw[138];
      T     #temp_dwd;
      U     L      3.0;
      =     "PMA_KONGSBERG_SEND".DG_3_LUBE_OIL_LEVEL;


// PointId = 013200   Binary Point
      L     "IMAC_KONGSBERG_OUT".adw[139];
      T     #temp_dwd;
      U     L      3.0;
      =     "PMA_KONGSBERG_SEND".DG_3_LO_FLT_DIFF_PR;


// PointId = 013210   Binary Point
      L     "IMAC_KONGSBERG_OUT".adw[140];
      T     #temp_dwd;
      U     L      3.0;
      =     "PMA_KONGSBERG_SEND".DG_3_FO_FLT_DIFF_PR;


// PointId = 013030   Binary Point
      L     "IMAC_KONGSBERG_OUT".adw[141];
      T     #temp_dwd;
      U     L      3.0;
      =     "PMA_KONGSBERG_SEND".DG_3_RUNNING;


// PointId = 013190   Binary Point
      L     "IMAC_KONGSBERG_OUT".adw[142];
      T     #temp_dwd;
      U     L      3.0;
      =     "PMA_KONGSBERG_SEND".DG_3_START_AIR_PRESSURE;


// PointId = 013570   Binary Point
      L     "IMAC_KONGSBERG_OUT".adw[143];
      T     #temp_dwd;
      U     L      3.0;
      =     "PMA_KONGSBERG_SEND".DG_3_SYMMETRIZATION;
NETWORK
TITLE = DG 3 Analogue Points

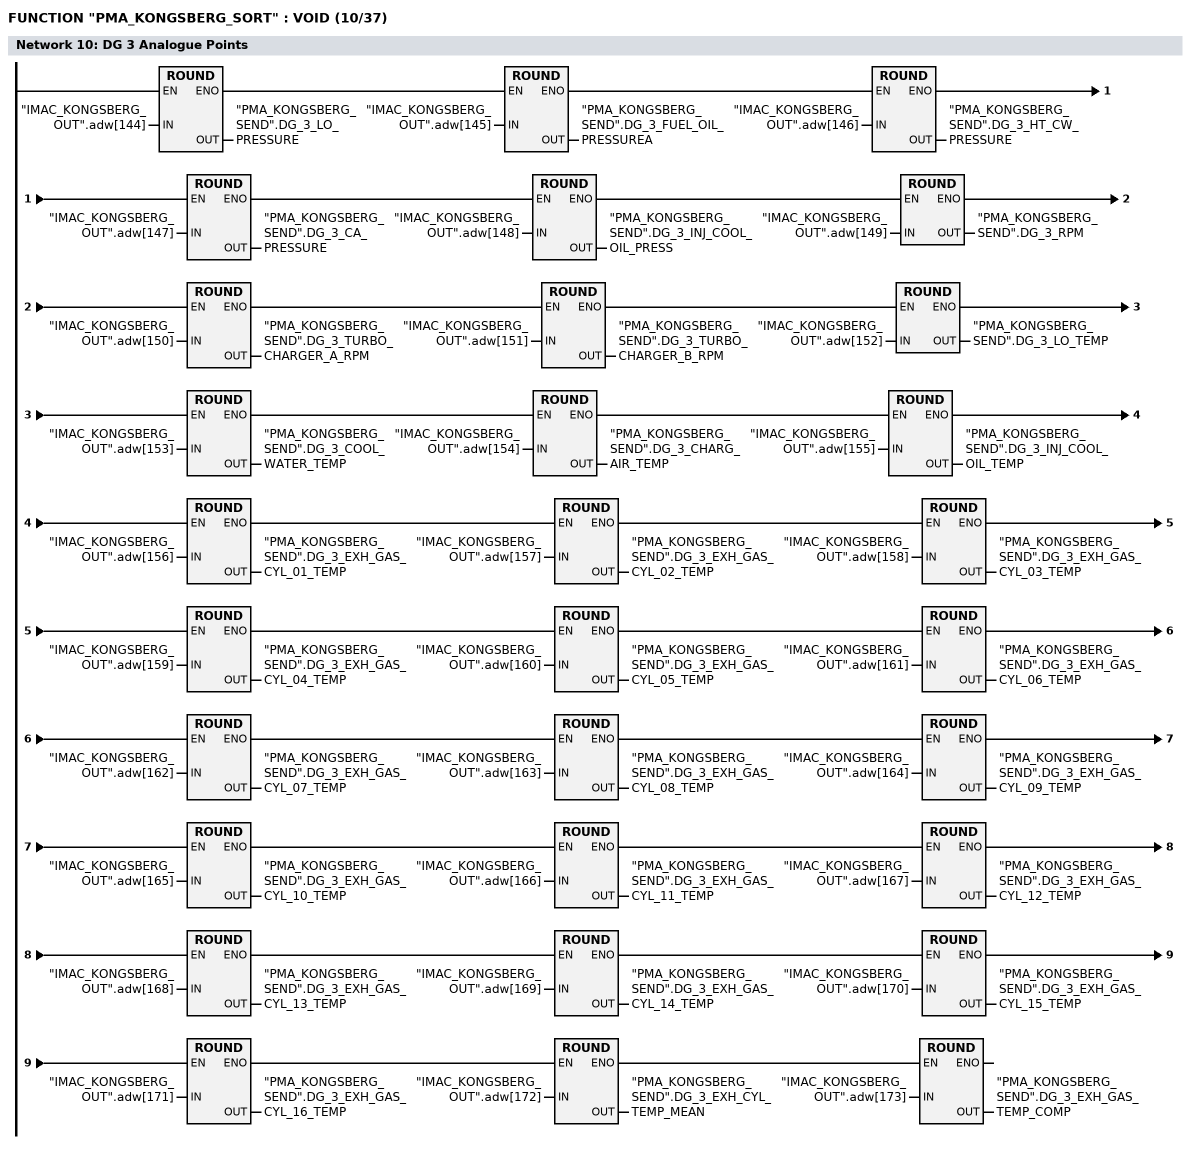
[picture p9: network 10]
// PointId = 013060   Analogue Point
      L     "IMAC_KONGSBERG_OUT".adw[144];
      RND   ;
      T     "PMA_KONGSBERG_SEND".DG_3_LO_PRESSURE;


// PointId = 013080   Analogue Point
      L     "IMAC_KONGSBERG_OUT".adw[145];
      RND   ;
      T     "PMA_KONGSBERG_SEND".DG_3_FUEL_OIL_PRESSUREA;


// PointId = 013090   Analogue Point
      L     "IMAC_KONGSBERG_OUT".adw[146];
      RND   ;
      T     "PMA_KONGSBERG_SEND".DG_3_HT_CW_PRESSURE;


// PointId = 013110   Analogue Point
      L     "IMAC_KONGSBERG_OUT".adw[147];
      RND   ;
      T     "PMA_KONGSBERG_SEND".DG_3_CA_PRESSURE;


// PointId = 013130   Analogue Point
      L     "IMAC_KONGSBERG_OUT".adw[148];
      RND   ;
      T     "PMA_KONGSBERG_SEND".DG_3_INJ_COOL_OIL_PRESS;


// PointId = 013020   Analogue Point
      L     "IMAC_KONGSBERG_OUT".adw[149];
      RND   ;
      T     "PMA_KONGSBERG_SEND".DG_3_RPM;


// PointId = 013040   Analogue Point
      L     "IMAC_KONGSBERG_OUT".adw[150];
      RND   ;
      T     "PMA_KONGSBERG_SEND".DG_3_TURBO_CHARGER_A_RPM;


// PointId = 013050   Analogue Point
      L     "IMAC_KONGSBERG_OUT".adw[151];
      RND   ;
      T     "PMA_KONGSBERG_SEND".DG_3_TURBO_CHARGER_B_RPM;


// PointId = 013070   Analogue Point
      L     "IMAC_KONGSBERG_OUT".adw[152];
      RND   ;
      T     "PMA_KONGSBERG_SEND".DG_3_LO_TEMP;


// PointId = 013100   Analogue Point
      L     "IMAC_KONGSBERG_OUT".adw[153];
      RND   ;
      T     "PMA_KONGSBERG_SEND".DG_3_COOL_WATER_TEMP;


// PointId = 013120   Analogue Point
      L     "IMAC_KONGSBERG_OUT".adw[154];
      RND   ;
      T     "PMA_KONGSBERG_SEND".DG_3_CHARG_AIR_TEMP;


// PointId = 013140   Analogue Point
      L     "IMAC_KONGSBERG_OUT".adw[155];
      RND   ;
      T     "PMA_KONGSBERG_SEND".DG_3_INJ_COOL_OIL_TEMP;


// PointId = 013230   Analogue Point
      L     "IMAC_KONGSBERG_OUT".adw[156];
      RND   ;
      T     "PMA_KONGSBERG_SEND".DG_3_EXH_GAS_CYL_01_TEMP;


// PointId = 013240   Analogue Point
      L     "IMAC_KONGSBERG_OUT".adw[157];
      RND   ;
      T     "PMA_KONGSBERG_SEND".DG_3_EXH_GAS_CYL_02_TEMP;


// PointId = 013250   Analogue Point
      L     "IMAC_KONGSBERG_OUT".adw[158];
      RND   ;
      T     "PMA_KONGSBERG_SEND".DG_3_EXH_GAS_CYL_03_TEMP;


// PointId = 013260   Analogue Point
      L     "IMAC_KONGSBERG_OUT".adw[159];
      RND   ;
      T     "PMA_KONGSBERG_SEND".DG_3_EXH_GAS_CYL_04_TEMP;


// PointId = 013270   Analogue Point
      L     "IMAC_KONGSBERG_OUT".adw[160];
      RND   ;
      T     "PMA_KONGSBERG_SEND".DG_3_EXH_GAS_CYL_05_TEMP;


// PointId = 013280   Analogue Point
      L     "IMAC_KONGSBERG_OUT".adw[161];
      RND   ;
      T     "PMA_KONGSBERG_SEND".DG_3_EXH_GAS_CYL_06_TEMP;


// PointId = 013290   Analogue Point
      L     "IMAC_KONGSBERG_OUT".adw[162];
      RND   ;
      T     "PMA_KONGSBERG_SEND".DG_3_EXH_GAS_CYL_07_TEMP;


// PointId = 013300   Analogue Point
      L     "IMAC_KONGSBERG_OUT".adw[163];
      RND   ;
      T     "PMA_KONGSBERG_SEND".DG_3_EXH_GAS_CYL_08_TEMP;


// PointId = 013310   Analogue Point
      L     "IMAC_KONGSBERG_OUT".adw[164];
      RND   ;
      T     "PMA_KONGSBERG_SEND".DG_3_EXH_GAS_CYL_09_TEMP;


// PointId = 013320   Analogue Point
      L     "IMAC_KONGSBERG_OUT".adw[165];
      RND   ;
      T     "PMA_KONGSBERG_SEND".DG_3_EXH_GAS_CYL_10_TEMP;


// PointId = 013330   Analogue Point
      L     "IMAC_KONGSBERG_OUT".adw[166];
      RND   ;
      T     "PMA_KONGSBERG_SEND".DG_3_EXH_GAS_CYL_11_TEMP;


// PointId = 013340   Analogue Point
      L     "IMAC_KONGSBERG_OUT".adw[167];
      RND   ;
      T     "PMA_KONGSBERG_SEND".DG_3_EXH_GAS_CYL_12_TEMP;


// PointId = 013350   Analogue Point
      L     "IMAC_KONGSBERG_OUT".adw[168];
      RND   ;
      T     "PMA_KONGSBERG_SEND".DG_3_EXH_GAS_CYL_13_TEMP;


// PointId = 013360   Analogue Point
      L     "IMAC_KONGSBERG_OUT".adw[169];
      RND   ;
      T     "PMA_KONGSBERG_SEND".DG_3_EXH_GAS_CYL_14_TEMP;


// PointId = 013370   Analogue Point
      L     "IMAC_KONGSBERG_OUT".adw[170];
      RND   ;
      T     "PMA_KONGSBERG_SEND".DG_3_EXH_GAS_CYL_15_TEMP;


// PointId = 013380   Analogue Point
      L     "IMAC_KONGSBERG_OUT".adw[171];
      RND   ;
      T     "PMA_KONGSBERG_SEND".DG_3_EXH_GAS_CYL_16_TEMP;


// PointId = 013550   Analogue Point
      L     "IMAC_KONGSBERG_OUT".adw[172];
      RND   ;
      T     "PMA_KONGSBERG_SEND".DG_3_EXH_CYL_TEMP_MEAN;


// PointId = 013560   Analogue Point
      L     "IMAC_KONGSBERG_OUT".adw[173];
      RND   ;
      T     "PMA_KONGSBERG_SEND".DG_3_EXH_GAS_TEMP_COMP;
NETWORK
TITLE = DG 4 Binary Points
// *** TELEGRAM 2 ***   Block 3
// PointId = 014010   Binary Point
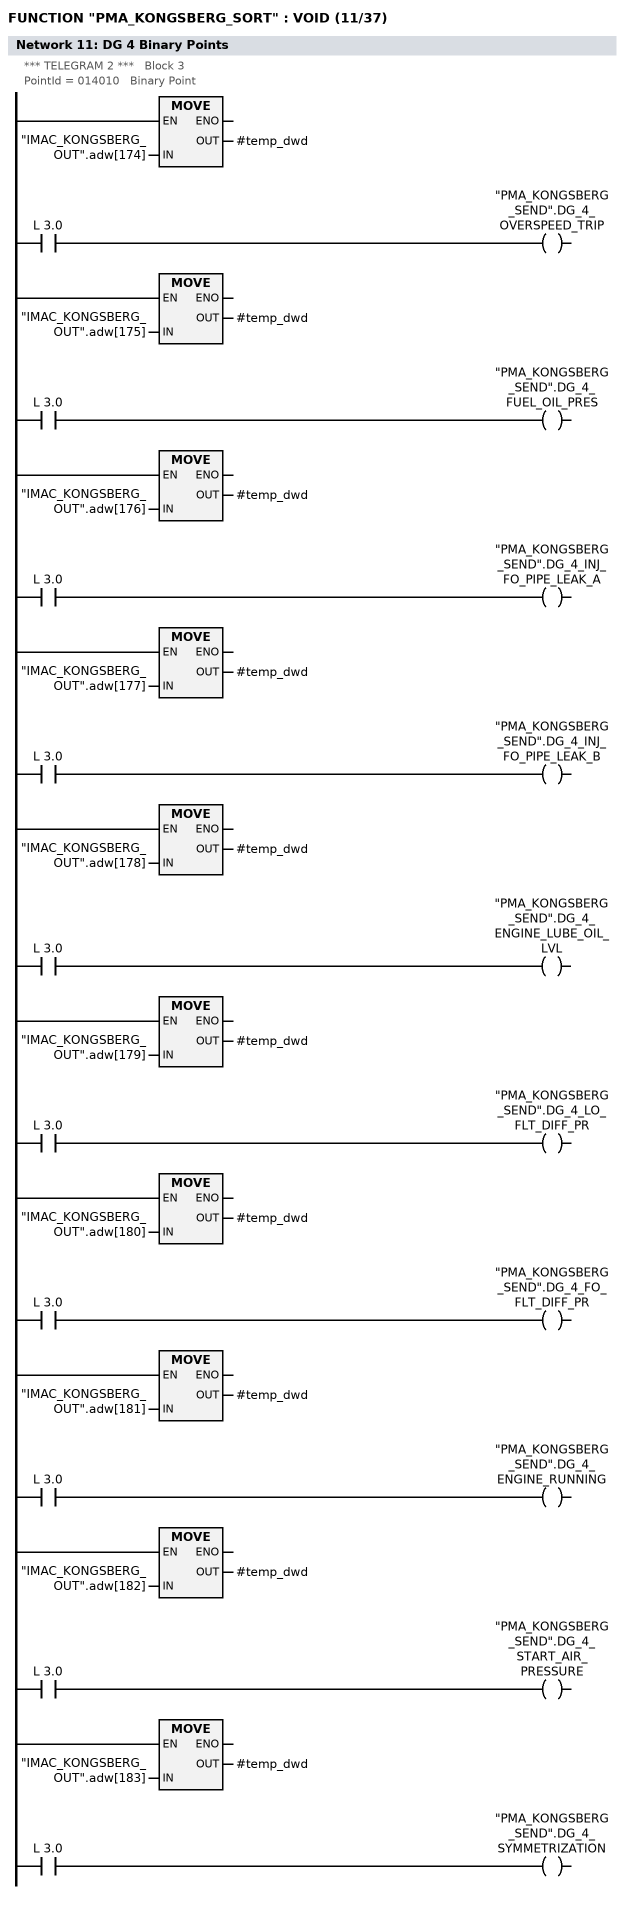
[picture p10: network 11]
      L     "IMAC_KONGSBERG_OUT".adw[174];
      T     #temp_dwd;
      U     L      3.0;
      =     "PMA_KONGSBERG_SEND".DG_4_OVERSPEED_TRIP;


// PointId = 014080   Binary Point
      L     "IMAC_KONGSBERG_OUT".adw[175];
      T     #temp_dwd;
      U     L      3.0;
      =     "PMA_KONGSBERG_SEND".DG_4_FUEL_OIL_PRES;


// PointId = 014160   Binary Point
      L     "IMAC_KONGSBERG_OUT".adw[176];
      T     #temp_dwd;
      U     L      3.0;
      =     "PMA_KONGSBERG_SEND".DG_4_INJ_FO_PIPE_LEAK_A;


// PointId = 014170   Binary Point
      L     "IMAC_KONGSBERG_OUT".adw[177];
      T     #temp_dwd;
      U     L      3.0;
      =     "PMA_KONGSBERG_SEND".DG_4_INJ_FO_PIPE_LEAK_B;


// PointId = 014180   Binary Point
      L     "IMAC_KONGSBERG_OUT".adw[178];
      T     #temp_dwd;
      U     L      3.0;
      =     "PMA_KONGSBERG_SEND".DG_4_ENGINE_LUBE_OIL_LVL;


// PointId = 014200   Binary Point
      L     "IMAC_KONGSBERG_OUT".adw[179];
      T     #temp_dwd;
      U     L      3.0;
      =     "PMA_KONGSBERG_SEND".DG_4_LO_FLT_DIFF_PR;


// PointId = 014210   Binary Point
      L     "IMAC_KONGSBERG_OUT".adw[180];
      T     #temp_dwd;
      U     L      3.0;
      =     "PMA_KONGSBERG_SEND".DG_4_FO_FLT_DIFF_PR;


// PointId = 014030   Binary Point
      L     "IMAC_KONGSBERG_OUT".adw[181];
      T     #temp_dwd;
      U     L      3.0;
      =     "PMA_KONGSBERG_SEND".DG_4_ENGINE_RUNNING;


// PointId = 014190   Binary Point
      L     "IMAC_KONGSBERG_OUT".adw[182];
      T     #temp_dwd;
      U     L      3.0;
      =     "PMA_KONGSBERG_SEND".DG_4_START_AIR_PRESSURE;


// PointId = 014570   Binary Point
      L     "IMAC_KONGSBERG_OUT".adw[183];
      T     #temp_dwd;
      U     L      3.0;
      =     "PMA_KONGSBERG_SEND".DG_4_SYMMETRIZATION;
NETWORK
TITLE = DG 4 Analogue Points

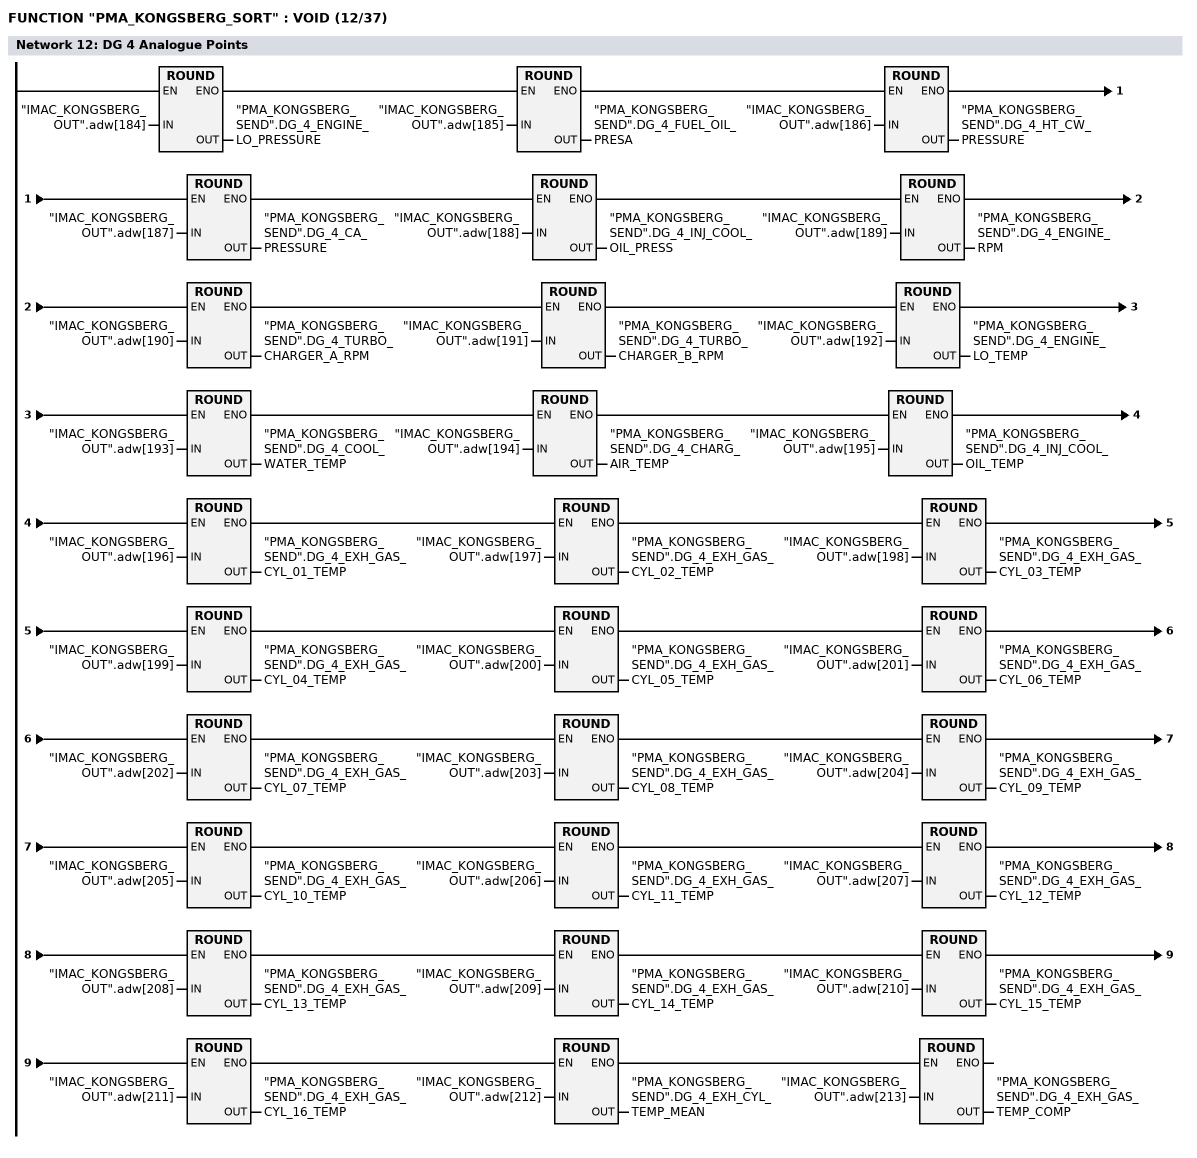
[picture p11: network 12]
//  PointId = 014060   Analogue Point
      L     "IMAC_KONGSBERG_OUT".adw[184];
      RND   ;
      T     "PMA_KONGSBERG_SEND".DG_4_ENGINE_LO_PRESSURE;


// PointId = 014080   Analogue Point
      L     "IMAC_KONGSBERG_OUT".adw[185];
      RND   ;
      T     "PMA_KONGSBERG_SEND".DG_4_FUEL_OIL_PRESA;


// PointId = 014090   Analogue Point
      L     "IMAC_KONGSBERG_OUT".adw[186];
      RND   ;
      T     "PMA_KONGSBERG_SEND".DG_4_HT_CW_PRESSURE;


// PointId = 014110   Analogue Point
      L     "IMAC_KONGSBERG_OUT".adw[187];
      RND   ;
      T     "PMA_KONGSBERG_SEND".DG_4_CA_PRESSURE;


// PointId = 014130   Analogue Point
      L     "IMAC_KONGSBERG_OUT".adw[188];
      RND   ;
      T     "PMA_KONGSBERG_SEND".DG_4_INJ_COOL_OIL_PRESS;


// PointId = 014020   Analogue Point
      L     "IMAC_KONGSBERG_OUT".adw[189];
      RND   ;
      T     "PMA_KONGSBERG_SEND".DG_4_ENGINE_RPM;


// PointId = 014040   Analogue Point
      L     "IMAC_KONGSBERG_OUT".adw[190];
      RND   ;
      T     "PMA_KONGSBERG_SEND".DG_4_TURBO_CHARGER_A_RPM;


// PointId = 014050   Analogue Point
      L     "IMAC_KONGSBERG_OUT".adw[191];
      RND   ;
      T     "PMA_KONGSBERG_SEND".DG_4_TURBO_CHARGER_B_RPM;


// PointId = 014070   Analogue Point
      L     "IMAC_KONGSBERG_OUT".adw[192];
      RND   ;
      T     "PMA_KONGSBERG_SEND".DG_4_ENGINE_LO_TEMP;


// PointId = 014100   Analogue Point
      L     "IMAC_KONGSBERG_OUT".adw[193];
      RND   ;
      T     "PMA_KONGSBERG_SEND".DG_4_COOL_WATER_TEMP;


// PointId = 014120   Analogue Point
      L     "IMAC_KONGSBERG_OUT".adw[194];
      RND   ;
      T     "PMA_KONGSBERG_SEND".DG_4_CHARG_AIR_TEMP;


// PointId = 014140   Analogue Point
      L     "IMAC_KONGSBERG_OUT".adw[195];
      RND   ;
      T     "PMA_KONGSBERG_SEND".DG_4_INJ_COOL_OIL_TEMP;


// PointId = 014230   Analogue Point
      L     "IMAC_KONGSBERG_OUT".adw[196];
      RND   ;
      T     "PMA_KONGSBERG_SEND".DG_4_EXH_GAS_CYL_01_TEMP;


// PointId = 014240   Analogue Point
      L     "IMAC_KONGSBERG_OUT".adw[197];
      RND   ;
      T     "PMA_KONGSBERG_SEND".DG_4_EXH_GAS_CYL_02_TEMP;


// PointId = 014250   Analogue Point
      L     "IMAC_KONGSBERG_OUT".adw[198];
      RND   ;
      T     "PMA_KONGSBERG_SEND".DG_4_EXH_GAS_CYL_03_TEMP;


// PointId = 014260   Analogue Point
      L     "IMAC_KONGSBERG_OUT".adw[199];
      RND   ;
      T     "PMA_KONGSBERG_SEND".DG_4_EXH_GAS_CYL_04_TEMP;


// PointId = 014270   Analogue Point
      L     "IMAC_KONGSBERG_OUT".adw[200];
      RND   ;
      T     "PMA_KONGSBERG_SEND".DG_4_EXH_GAS_CYL_05_TEMP;


// PointId = 014280   Analogue Point
      L     "IMAC_KONGSBERG_OUT".adw[201];
      RND   ;
      T     "PMA_KONGSBERG_SEND".DG_4_EXH_GAS_CYL_06_TEMP;


// PointId = 014290   Analogue Point
      L     "IMAC_KONGSBERG_OUT".adw[202];
      RND   ;
      T     "PMA_KONGSBERG_SEND".DG_4_EXH_GAS_CYL_07_TEMP;


// PointId = 014300   Analogue Point
      L     "IMAC_KONGSBERG_OUT".adw[203];
      RND   ;
      T     "PMA_KONGSBERG_SEND".DG_4_EXH_GAS_CYL_08_TEMP;


// PointId = 014310   Analogue Point
      L     "IMAC_KONGSBERG_OUT".adw[204];
      RND   ;
      T     "PMA_KONGSBERG_SEND".DG_4_EXH_GAS_CYL_09_TEMP;


// PointId = 014320   Analogue Point
      L     "IMAC_KONGSBERG_OUT".adw[205];
      RND   ;
      T     "PMA_KONGSBERG_SEND".DG_4_EXH_GAS_CYL_10_TEMP;


// PointId = 014330   Analogue Point
      L     "IMAC_KONGSBERG_OUT".adw[206];
      RND   ;
      T     "PMA_KONGSBERG_SEND".DG_4_EXH_GAS_CYL_11_TEMP;


// PointId = 014340   Analogue Point
      L     "IMAC_KONGSBERG_OUT".adw[207];
      RND   ;
      T     "PMA_KONGSBERG_SEND".DG_4_EXH_GAS_CYL_12_TEMP;


// PointId = 014350   Analogue Point
      L     "IMAC_KONGSBERG_OUT".adw[208];
      RND   ;
      T     "PMA_KONGSBERG_SEND".DG_4_EXH_GAS_CYL_13_TEMP;


// PointId = 014360   Analogue Point
      L     "IMAC_KONGSBERG_OUT".adw[209];
      RND   ;
      T     "PMA_KONGSBERG_SEND".DG_4_EXH_GAS_CYL_14_TEMP;


// PointId = 014370   Analogue Point
      L     "IMAC_KONGSBERG_OUT".adw[210];
      RND   ;
      T     "PMA_KONGSBERG_SEND".DG_4_EXH_GAS_CYL_15_TEMP;


// PointId = 014380   Analogue Point
      L     "IMAC_KONGSBERG_OUT".adw[211];
      RND   ;
      T     "PMA_KONGSBERG_SEND".DG_4_EXH_GAS_CYL_16_TEMP;


// PointId = 014550   Analogue Point
      L     "IMAC_KONGSBERG_OUT".adw[212];
      RND   ;
      T     "PMA_KONGSBERG_SEND".DG_4_EXH_CYL_TEMP_MEAN;


// PointId = 014560   Analogue Point
      L     "IMAC_KONGSBERG_OUT".adw[213];
      RND   ;
      T     "PMA_KONGSBERG_SEND".DG_4_EXH_GAS_TEMP_COMP;
NETWORK
TITLE = GEN 3 Analogue Points
// *** TELEGRAM 2 ***   Block 4
// PointId = 023010   Analogue Point
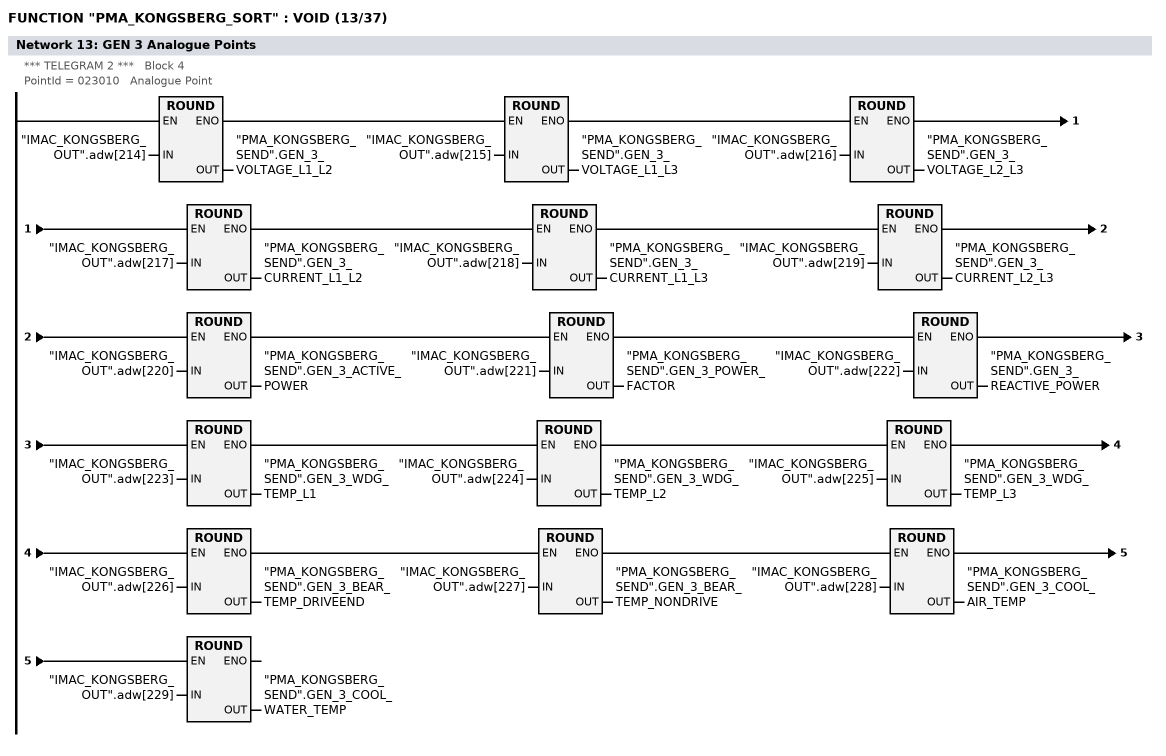
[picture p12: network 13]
      L     "IMAC_KONGSBERG_OUT".adw[214];
      RND   ;
      T     "PMA_KONGSBERG_SEND".GEN_3_VOLTAGE_L1_L2;


// PointId = 023020   Analogue Point
      L     "IMAC_KONGSBERG_OUT".adw[215];
      RND   ;
      T     "PMA_KONGSBERG_SEND".GEN_3_VOLTAGE_L1_L3;


// PointId = 023030   Analogue Point
      L     "IMAC_KONGSBERG_OUT".adw[216];
      RND   ;
      T     "PMA_KONGSBERG_SEND".GEN_3_VOLTAGE_L2_L3;


// PointId = 023040   Analogue Point
      L     "IMAC_KONGSBERG_OUT".adw[217];
      RND   ;
      T     "PMA_KONGSBERG_SEND".GEN_3_CURRENT_L1_L2;


// PointId = 023051   Analogue Point
      L     "IMAC_KONGSBERG_OUT".adw[218];
      RND   ;
      T     "PMA_KONGSBERG_SEND".GEN_3_CURRENT_L1_L3;


// PointId = 023060   Analogue Point
      L     "IMAC_KONGSBERG_OUT".adw[219];
      RND   ;
      T     "PMA_KONGSBERG_SEND".GEN_3_CURRENT_L2_L3;


// PointId = 023070   Analogue Point
      L     "IMAC_KONGSBERG_OUT".adw[220];
      RND   ;
      T     "PMA_KONGSBERG_SEND".GEN_3_ACTIVE_POWER;


// PointId = 023080   Analogue Point
      L     "IMAC_KONGSBERG_OUT".adw[221];
      RND   ;
      T     "PMA_KONGSBERG_SEND".GEN_3_POWER_FACTOR;


// PointId = 023090   Analogue Point
      L     "IMAC_KONGSBERG_OUT".adw[222];
      RND   ;
      T     "PMA_KONGSBERG_SEND".GEN_3_REACTIVE_POWER;


// PointId = 023120   Analogue Point
      L     "IMAC_KONGSBERG_OUT".adw[223];
      RND   ;
      T     "PMA_KONGSBERG_SEND".GEN_3_WDG_TEMP_L1;


// PointId = 023130   Analogue Point
      L     "IMAC_KONGSBERG_OUT".adw[224];
      RND   ;
      T     "PMA_KONGSBERG_SEND".GEN_3_WDG_TEMP_L2;


// PointId = 023140   Analogue Point
      L     "IMAC_KONGSBERG_OUT".adw[225];
      RND   ;
      T     "PMA_KONGSBERG_SEND".GEN_3_WDG_TEMP_L3;


// PointId = 023150   Analogue Point
      L     "IMAC_KONGSBERG_OUT".adw[226];
      RND   ;
      T     "PMA_KONGSBERG_SEND".GEN_3_BEAR_TEMP_DRIVEEND;


// PointId = 023160   Analogue Point
      L     "IMAC_KONGSBERG_OUT".adw[227];
      RND   ;
      T     "PMA_KONGSBERG_SEND".GEN_3_BEAR_TEMP_NONDRIVE;


// PointId = 023170   Analogue Point
      L     "IMAC_KONGSBERG_OUT".adw[228];
      RND   ;
      T     "PMA_KONGSBERG_SEND".GEN_3_COOL_AIR_TEMP;


// PointId = 023180   Analogue Point
      L     "IMAC_KONGSBERG_OUT".adw[229];
      RND   ;
      T     "PMA_KONGSBERG_SEND".GEN_3_COOL_WATER_TEMP;
NETWORK
TITLE = GEN 3 Binary Points
// *** TELEGRAM 2 ***   Block 5
//  PointId = 023100   Binary Point
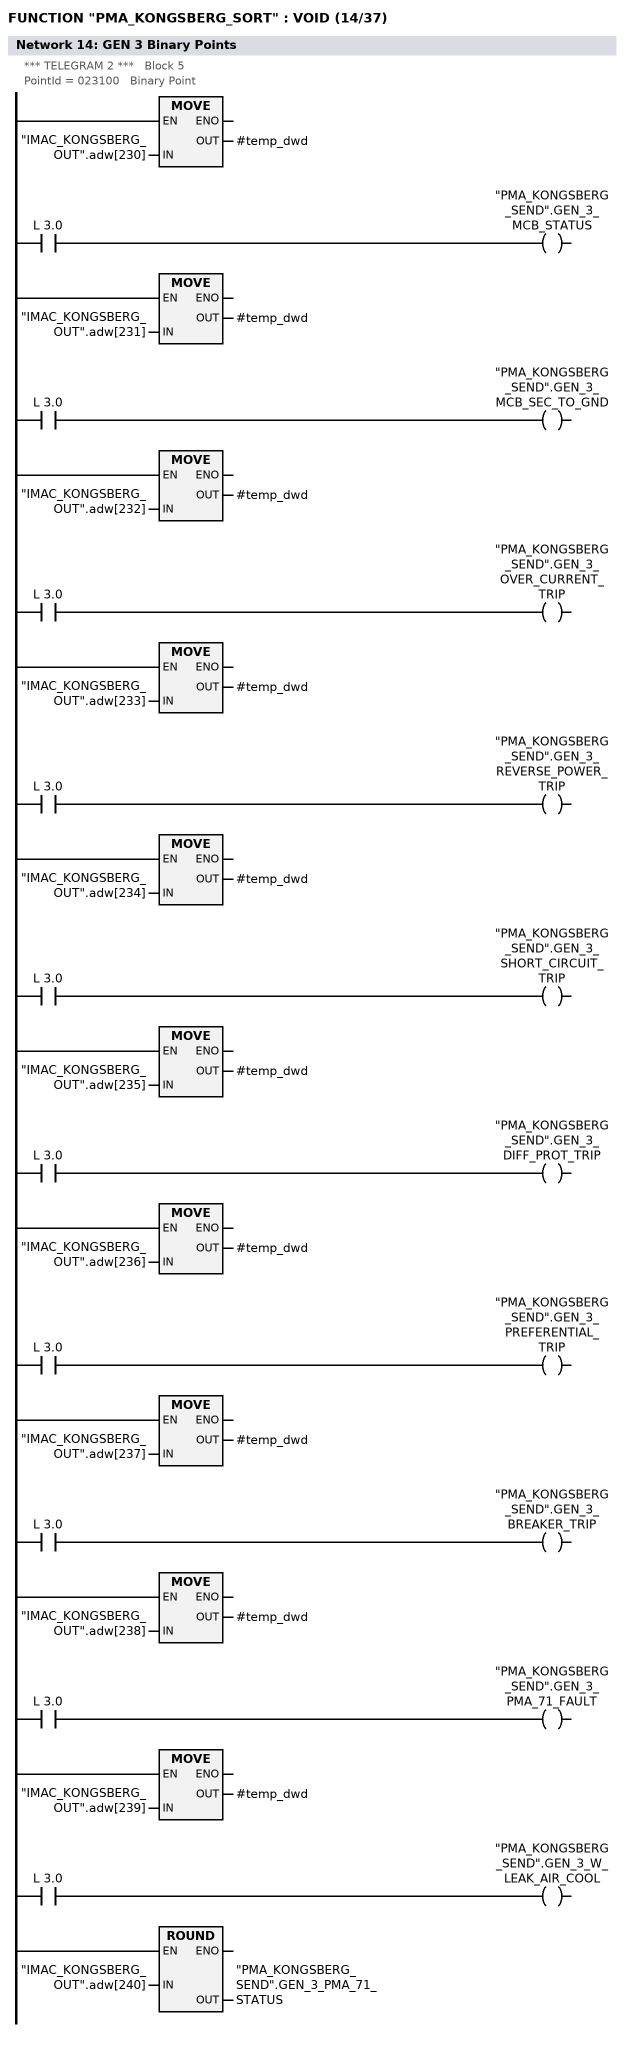
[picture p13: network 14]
      L     "IMAC_KONGSBERG_OUT".adw[230];
      T     #temp_dwd;
      U     L      3.0;
      =     "PMA_KONGSBERG_SEND".GEN_3_MCB_STATUS;


// PointId = 023110   Binary Point
      L     "IMAC_KONGSBERG_OUT".adw[231];
      T     #temp_dwd;
      U     L      3.0;
      =     "PMA_KONGSBERG_SEND".GEN_3_MCB_SEC_TO_GND;


// PointId = 023190   Binary Point
      L     "IMAC_KONGSBERG_OUT".adw[232];
      T     #temp_dwd;
      U     L      3.0;
      =     "PMA_KONGSBERG_SEND".GEN_3_OVER_CURRENT_TRIP;


// PointId = 023200   Binary Point
      L     "IMAC_KONGSBERG_OUT".adw[233];
      T     #temp_dwd;
      U     L      3.0;
      =     "PMA_KONGSBERG_SEND".GEN_3_REVERSE_POWER_TRIP;


// PointId = 023210   Binary Point
      L     "IMAC_KONGSBERG_OUT".adw[234];
      T     #temp_dwd;
      U     L      3.0;
      =     "PMA_KONGSBERG_SEND".GEN_3_SHORT_CIRCUIT_TRIP;


// PointId = 023240   Binary Point
      L     "IMAC_KONGSBERG_OUT".adw[235];
      T     #temp_dwd;
      U     L      3.0;
      =     "PMA_KONGSBERG_SEND".GEN_3_DIFF_PROT_TRIP;


// PointId = 023260   Binary Point
      L     "IMAC_KONGSBERG_OUT".adw[236];
      T     #temp_dwd;
      U     L      3.0;
      =     "PMA_KONGSBERG_SEND".GEN_3_PREFERENTIAL_TRIP;


// PointId = 023270   Binary Point
      L     "IMAC_KONGSBERG_OUT".adw[237];
      T     #temp_dwd;
      U     L      3.0;
      =     "PMA_KONGSBERG_SEND".GEN_3_BREAKER_TRIP;


// PointId = 023290   Binary Point
      L     "IMAC_KONGSBERG_OUT".adw[238];
      T     #temp_dwd;
      U     L      3.0;
      =     "PMA_KONGSBERG_SEND".GEN_3_PMA_71_FAULT;


// PointId = 023310   Binary Point
      L     "IMAC_KONGSBERG_OUT".adw[239];
      T     #temp_dwd;
      U     L      3.0;
      =     "PMA_KONGSBERG_SEND".GEN_3_W_LEAK_AIR_COOL;

//  PointId = 023300   Analogue Point
      L     "IMAC_KONGSBERG_OUT".adw[240];
      RND   ;
      T     "PMA_KONGSBERG_SEND".GEN_3_PMA_71_STATUS;
NETWORK
TITLE = GEN 4 Analogue Points
// *** TELEGRAM 2 ***   Block 6
// PointId = 024010   Analogue Point
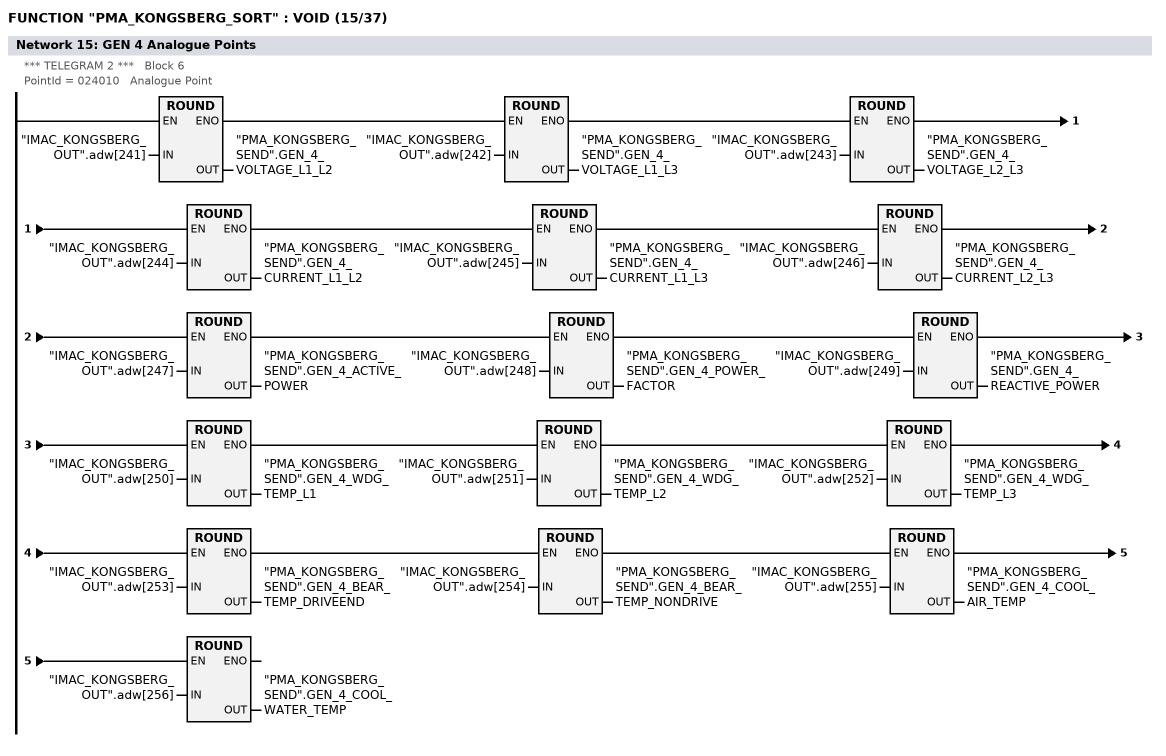
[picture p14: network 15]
      L     "IMAC_KONGSBERG_OUT".adw[241];
      RND   ;
      T     "PMA_KONGSBERG_SEND".GEN_4_VOLTAGE_L1_L2;


// PointId = 024020   Analogue Point
      L     "IMAC_KONGSBERG_OUT".adw[242];
      RND   ;
      T     "PMA_KONGSBERG_SEND".GEN_4_VOLTAGE_L1_L3;


// PointId = 024030   Analogue Point
      L     "IMAC_KONGSBERG_OUT".adw[243];
      RND   ;
      T     "PMA_KONGSBERG_SEND".GEN_4_VOLTAGE_L2_L3;


// PointId = 024040   Analogue Point
      L     "IMAC_KONGSBERG_OUT".adw[244];
      RND   ;
      T     "PMA_KONGSBERG_SEND".GEN_4_CURRENT_L1_L2;


// PointId = 024051   Analogue Point
      L     "IMAC_KONGSBERG_OUT".adw[245];
      RND   ;
      T     "PMA_KONGSBERG_SEND".GEN_4_CURRENT_L1_L3;


// PointId = 024060   Analogue Point
      L     "IMAC_KONGSBERG_OUT".adw[246];
      RND   ;
      T     "PMA_KONGSBERG_SEND".GEN_4_CURRENT_L2_L3;


// PointId = 024070   Analogue Point
      L     "IMAC_KONGSBERG_OUT".adw[247];
      RND   ;
      T     "PMA_KONGSBERG_SEND".GEN_4_ACTIVE_POWER;


// PointId = 024080   Analogue Point
      L     "IMAC_KONGSBERG_OUT".adw[248];
      RND   ;
      T     "PMA_KONGSBERG_SEND".GEN_4_POWER_FACTOR;


// PointId = 024090   Analogue Point
      L     "IMAC_KONGSBERG_OUT".adw[249];
      RND   ;
      T     "PMA_KONGSBERG_SEND".GEN_4_REACTIVE_POWER;


// PointId = 024120   Analogue Point
      L     "IMAC_KONGSBERG_OUT".adw[250];
      RND   ;
      T     "PMA_KONGSBERG_SEND".GEN_4_WDG_TEMP_L1;


// PointId = 024130   Analogue Point
      L     "IMAC_KONGSBERG_OUT".adw[251];
      RND   ;
      T     "PMA_KONGSBERG_SEND".GEN_4_WDG_TEMP_L2;


// PointId = 024140   Analogue Point
      L     "IMAC_KONGSBERG_OUT".adw[252];
      RND   ;
      T     "PMA_KONGSBERG_SEND".GEN_4_WDG_TEMP_L3;


// PointId = 024150   Analogue Point
      L     "IMAC_KONGSBERG_OUT".adw[253];
      RND   ;
      T     "PMA_KONGSBERG_SEND".GEN_4_BEAR_TEMP_DRIVEEND;


// PointId = 024160   Analogue Point
      L     "IMAC_KONGSBERG_OUT".adw[254];
      RND   ;
      T     "PMA_KONGSBERG_SEND".GEN_4_BEAR_TEMP_NONDRIVE;


// PointId = 024170   Analogue Point
      L     "IMAC_KONGSBERG_OUT".adw[255];
      RND   ;
      T     "PMA_KONGSBERG_SEND".GEN_4_COOL_AIR_TEMP;


// PointId = 024180   Analogue Point
      L     "IMAC_KONGSBERG_OUT".adw[256];
      RND   ;
      T     "PMA_KONGSBERG_SEND".GEN_4_COOL_WATER_TEMP;
NETWORK
TITLE = GEN 4 Binary Points
// *** TELEGRAM 2 ***   Block 7
// PointId = 024100   Binary Point
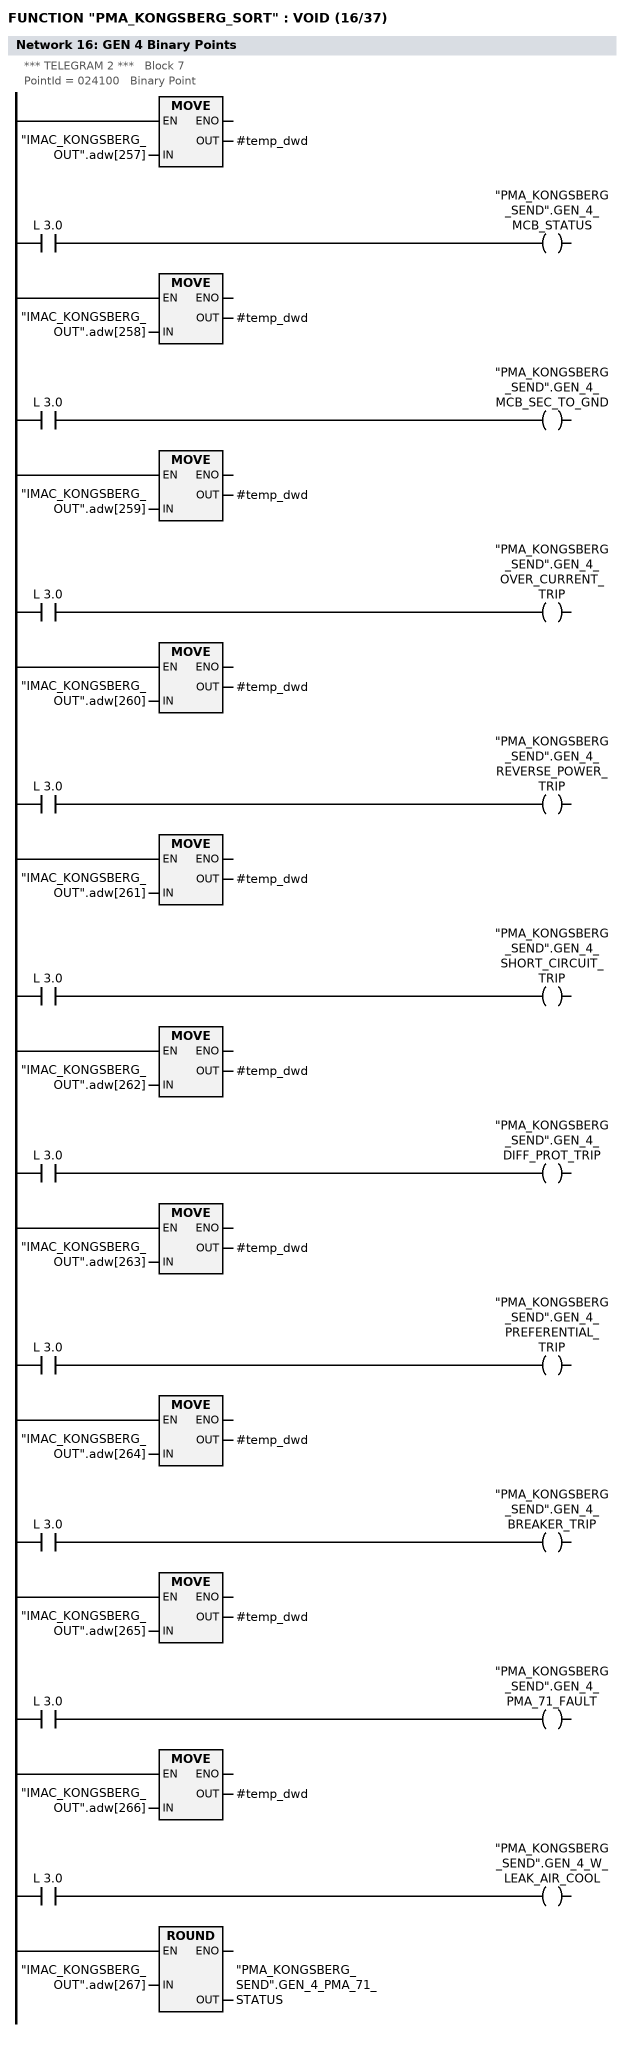
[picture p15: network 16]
      L     "IMAC_KONGSBERG_OUT".adw[257];
      T     #temp_dwd;
      U     L      3.0;
      =     "PMA_KONGSBERG_SEND".GEN_4_MCB_STATUS;


// PointId = 024110   Binary Point
      L     "IMAC_KONGSBERG_OUT".adw[258];
      T     #temp_dwd;
      U     L      3.0;
      =     "PMA_KONGSBERG_SEND".GEN_4_MCB_SEC_TO_GND;


// PointId = 024190   Binary Point
      L     "IMAC_KONGSBERG_OUT".adw[259];
      T     #temp_dwd;
      U     L      3.0;
      =     "PMA_KONGSBERG_SEND".GEN_4_OVER_CURRENT_TRIP;


// PointId = 024200   Binary Point
      L     "IMAC_KONGSBERG_OUT".adw[260];
      T     #temp_dwd;
      U     L      3.0;
      =     "PMA_KONGSBERG_SEND".GEN_4_REVERSE_POWER_TRIP;


// PointId = 024210   Binary Point
      L     "IMAC_KONGSBERG_OUT".adw[261];
      T     #temp_dwd;
      U     L      3.0;
      =     "PMA_KONGSBERG_SEND".GEN_4_SHORT_CIRCUIT_TRIP;


// PointId = 024240   Binary Point
      L     "IMAC_KONGSBERG_OUT".adw[262];
      T     #temp_dwd;
      U     L      3.0;
      =     "PMA_KONGSBERG_SEND".GEN_4_DIFF_PROT_TRIP;


// PointId = 024260   Binary Point
      L     "IMAC_KONGSBERG_OUT".adw[263];
      T     #temp_dwd;
      U     L      3.0;
      =     "PMA_KONGSBERG_SEND".GEN_4_PREFERENTIAL_TRIP;


// PointId = 024270   Binary Point
      L     "IMAC_KONGSBERG_OUT".adw[264];
      T     #temp_dwd;
      U     L      3.0;
      =     "PMA_KONGSBERG_SEND".GEN_4_BREAKER_TRIP;


// PointId = 024290   Binary Point
      L     "IMAC_KONGSBERG_OUT".adw[265];
      T     #temp_dwd;
      U     L      3.0;
      =     "PMA_KONGSBERG_SEND".GEN_4_PMA_71_FAULT;


// PointId = 024310   Binary Point
      L     "IMAC_KONGSBERG_OUT".adw[266];
      T     #temp_dwd;
      U     L      3.0;
      =     "PMA_KONGSBERG_SEND".GEN_4_W_LEAK_AIR_COOL;


// PointId = 024300   Analogue Point
      L     "IMAC_KONGSBERG_OUT".adw[267];
      RND   ;
      T     "PMA_KONGSBERG_SEND".GEN_4_PMA_71_STATUS;
NETWORK
TITLE = DG 5 Binary Points
// *** TELEGRAM 3 ***   Block 2
// PointId = 015010   Binary Point
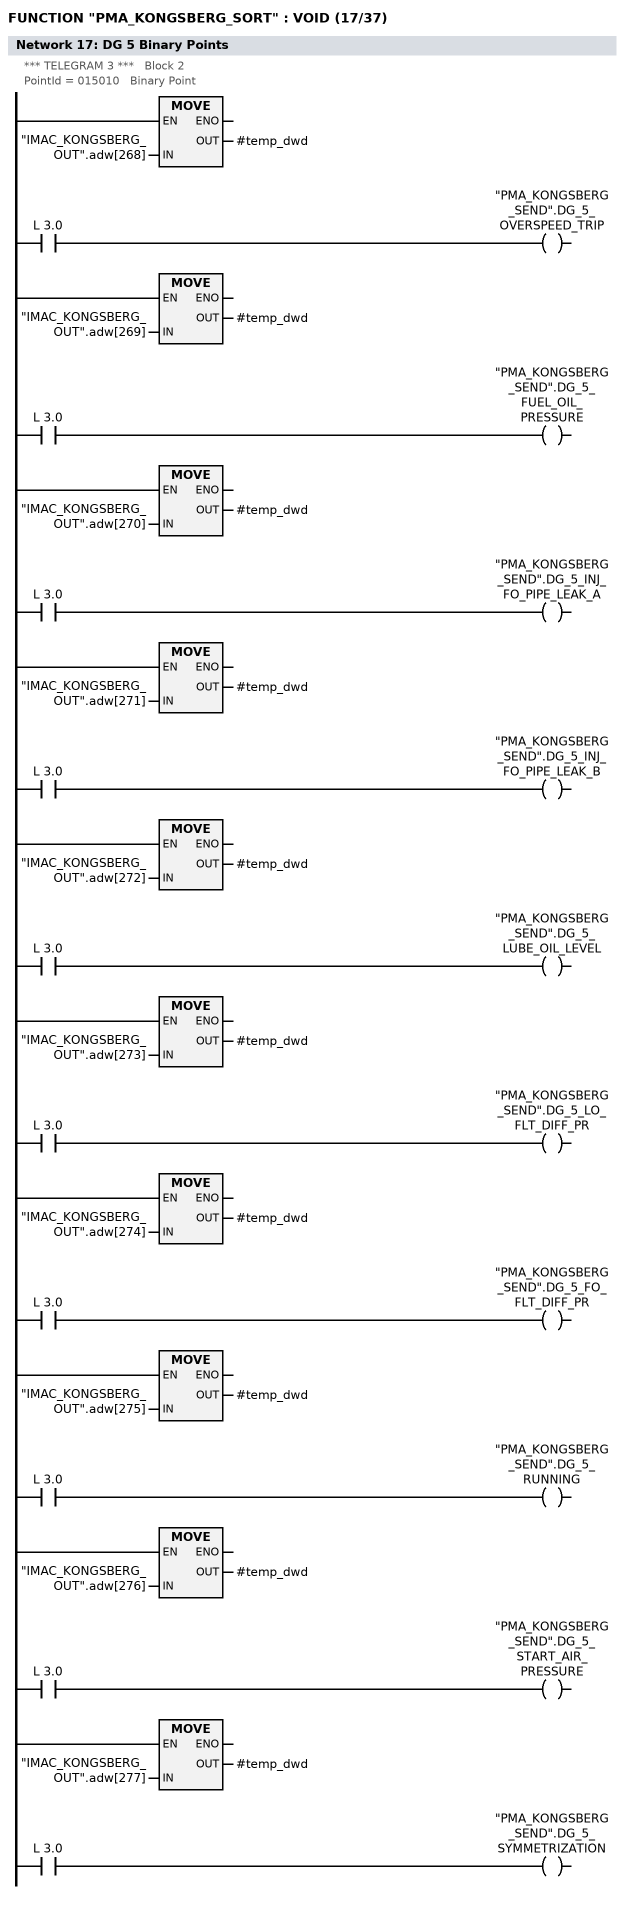
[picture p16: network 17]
      L     "IMAC_KONGSBERG_OUT".adw[268];
      T     #temp_dwd;
      U     L      3.0;
      =     "PMA_KONGSBERG_SEND".DG_5_OVERSPEED_TRIP;


// PointId = 015080   Binary Point
      L     "IMAC_KONGSBERG_OUT".adw[269];
      T     #temp_dwd;
      U     L      3.0;
      =     "PMA_KONGSBERG_SEND".DG_5_FUEL_OIL_PRESSURE;


// PointId = 015160   Binary Point
      L     "IMAC_KONGSBERG_OUT".adw[270];
      T     #temp_dwd;
      U     L      3.0;
      =     "PMA_KONGSBERG_SEND".DG_5_INJ_FO_PIPE_LEAK_A;


// PointId = 015170   Binary Point
      L     "IMAC_KONGSBERG_OUT".adw[271];
      T     #temp_dwd;
      U     L      3.0;
      =     "PMA_KONGSBERG_SEND".DG_5_INJ_FO_PIPE_LEAK_B;


// PointId = 015180   Binary Point
      L     "IMAC_KONGSBERG_OUT".adw[272];
      T     #temp_dwd;
      U     L      3.0;
      =     "PMA_KONGSBERG_SEND".DG_5_LUBE_OIL_LEVEL;


// PointId = 015200   Binary Point
      L     "IMAC_KONGSBERG_OUT".adw[273];
      T     #temp_dwd;
      U     L      3.0;
      =     "PMA_KONGSBERG_SEND".DG_5_LO_FLT_DIFF_PR;


// PointId = 015210   Binary Point
      L     "IMAC_KONGSBERG_OUT".adw[274];
      T     #temp_dwd;
      U     L      3.0;
      =     "PMA_KONGSBERG_SEND".DG_5_FO_FLT_DIFF_PR;


// PointId = 015030   Binary Point
      L     "IMAC_KONGSBERG_OUT".adw[275];
      T     #temp_dwd;
      U     L      3.0;
      =     "PMA_KONGSBERG_SEND".DG_5_RUNNING;


// PointId = 015190   Binary Point
      L     "IMAC_KONGSBERG_OUT".adw[276];
      T     #temp_dwd;
      U     L      3.0;
      =     "PMA_KONGSBERG_SEND".DG_5_START_AIR_PRESSURE;


// PointId = 015570   Binary Point
      L     "IMAC_KONGSBERG_OUT".adw[277];
      T     #temp_dwd;
      U     L      3.0;
      =     "PMA_KONGSBERG_SEND".DG_5_SYMMETRIZATION;
NETWORK
TITLE = DG 5 Analogue Points

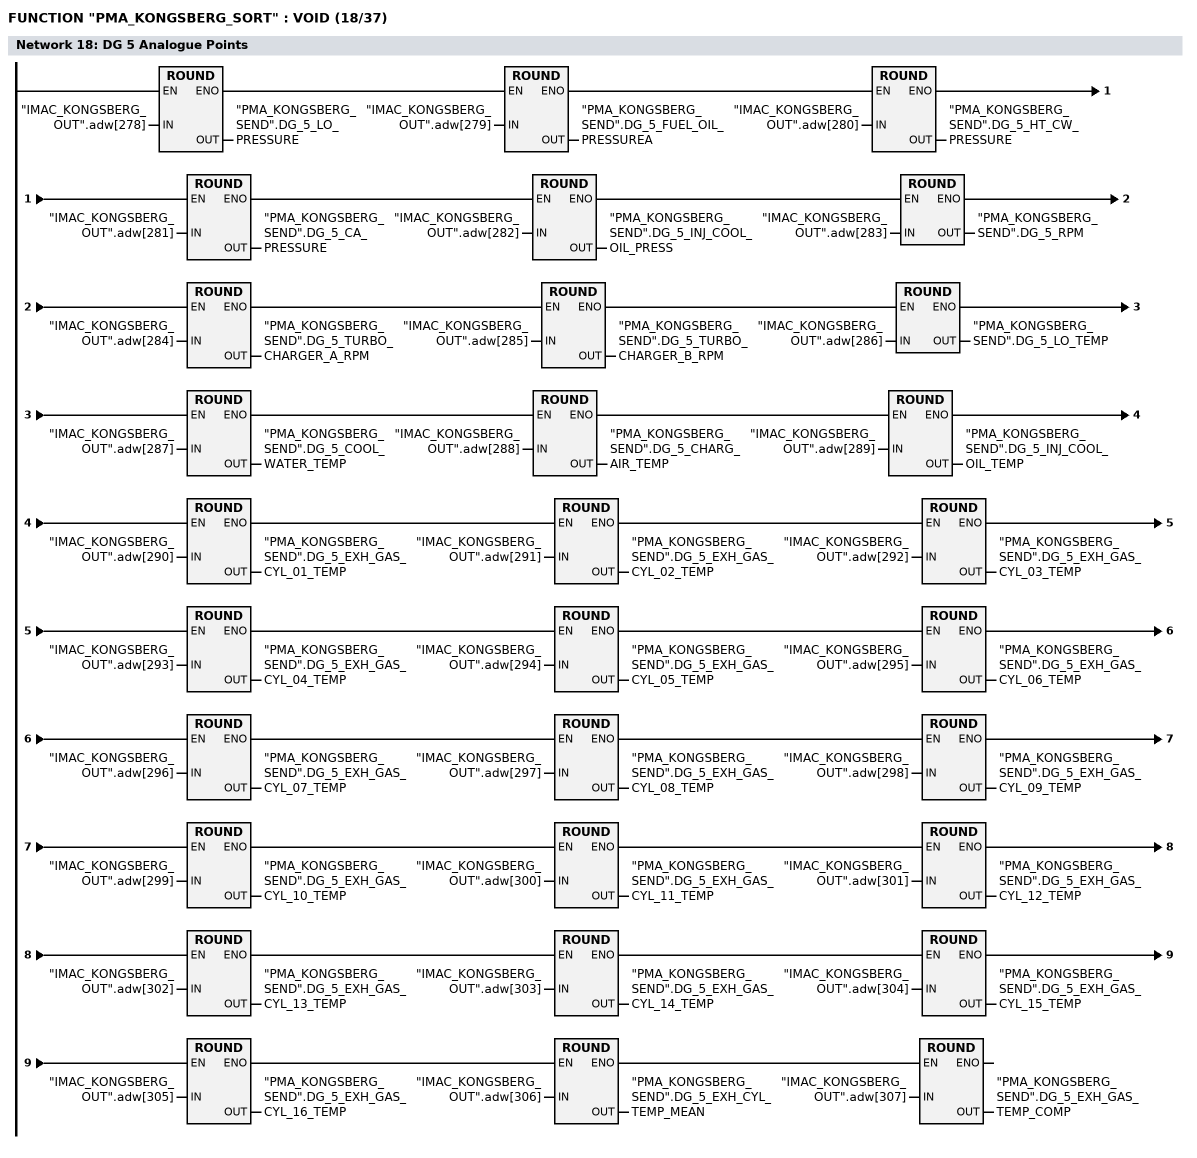
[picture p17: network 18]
//  PointId = 015060   Analogue Point
      L     "IMAC_KONGSBERG_OUT".adw[278];
      RND   ;
      T     "PMA_KONGSBERG_SEND".DG_5_LO_PRESSURE;


// PointId = 015080   Analogue Point
      L     "IMAC_KONGSBERG_OUT".adw[279];
      RND   ;
      T     "PMA_KONGSBERG_SEND".DG_5_FUEL_OIL_PRESSUREA;


// PointId = 015090   Analogue Point
      L     "IMAC_KONGSBERG_OUT".adw[280];
      RND   ;
      T     "PMA_KONGSBERG_SEND".DG_5_HT_CW_PRESSURE;


// PointId = 015110   Analogue Point
      L     "IMAC_KONGSBERG_OUT".adw[281];
      RND   ;
      T     "PMA_KONGSBERG_SEND".DG_5_CA_PRESSURE;


// PointId = 015130   Analogue Point
      L     "IMAC_KONGSBERG_OUT".adw[282];
      RND   ;
      T     "PMA_KONGSBERG_SEND".DG_5_INJ_COOL_OIL_PRESS;


// PointId = 015020   Analogue Point
      L     "IMAC_KONGSBERG_OUT".adw[283];
      RND   ;
      T     "PMA_KONGSBERG_SEND".DG_5_RPM;


// PointId = 015040   Analogue Point
      L     "IMAC_KONGSBERG_OUT".adw[284];
      RND   ;
      T     "PMA_KONGSBERG_SEND".DG_5_TURBO_CHARGER_A_RPM;


// PointId = 015050   Analogue Point
      L     "IMAC_KONGSBERG_OUT".adw[285];
      RND   ;
      T     "PMA_KONGSBERG_SEND".DG_5_TURBO_CHARGER_B_RPM;


// PointId = 015070   Analogue Point
      L     "IMAC_KONGSBERG_OUT".adw[286];
      RND   ;
      T     "PMA_KONGSBERG_SEND".DG_5_LO_TEMP;


// PointId = 015100   Analogue Point
      L     "IMAC_KONGSBERG_OUT".adw[287];
      RND   ;
      T     "PMA_KONGSBERG_SEND".DG_5_COOL_WATER_TEMP;


// PointId = 015120   Analogue Point
      L     "IMAC_KONGSBERG_OUT".adw[288];
      RND   ;
      T     "PMA_KONGSBERG_SEND".DG_5_CHARG_AIR_TEMP;


// PointId = 015140   Analogue Point
      L     "IMAC_KONGSBERG_OUT".adw[289];
      RND   ;
      T     "PMA_KONGSBERG_SEND".DG_5_INJ_COOL_OIL_TEMP;


// PointId = 015230   Analogue Point
      L     "IMAC_KONGSBERG_OUT".adw[290];
      RND   ;
      T     "PMA_KONGSBERG_SEND".DG_5_EXH_GAS_CYL_01_TEMP;


// PointId = 015240   Analogue Point
      L     "IMAC_KONGSBERG_OUT".adw[291];
      RND   ;
      T     "PMA_KONGSBERG_SEND".DG_5_EXH_GAS_CYL_02_TEMP;


// PointId = 015250   Analogue Point
      L     "IMAC_KONGSBERG_OUT".adw[292];
      RND   ;
      T     "PMA_KONGSBERG_SEND".DG_5_EXH_GAS_CYL_03_TEMP;


// PointId = 015260   Analogue Point
      L     "IMAC_KONGSBERG_OUT".adw[293];
      RND   ;
      T     "PMA_KONGSBERG_SEND".DG_5_EXH_GAS_CYL_04_TEMP;


// PointId = 015270   Analogue Point
      L     "IMAC_KONGSBERG_OUT".adw[294];
      RND   ;
      T     "PMA_KONGSBERG_SEND".DG_5_EXH_GAS_CYL_05_TEMP;


// PointId = 015280   Analogue Point
      L     "IMAC_KONGSBERG_OUT".adw[295];
      RND   ;
      T     "PMA_KONGSBERG_SEND".DG_5_EXH_GAS_CYL_06_TEMP;


// PointId = 015290   Analogue Point
      L     "IMAC_KONGSBERG_OUT".adw[296];
      RND   ;
      T     "PMA_KONGSBERG_SEND".DG_5_EXH_GAS_CYL_07_TEMP;


// PointId = 015300   Analogue Point
      L     "IMAC_KONGSBERG_OUT".adw[297];
      RND   ;
      T     "PMA_KONGSBERG_SEND".DG_5_EXH_GAS_CYL_08_TEMP;


// PointId = 015310   Analogue Point
      L     "IMAC_KONGSBERG_OUT".adw[298];
      RND   ;
      T     "PMA_KONGSBERG_SEND".DG_5_EXH_GAS_CYL_09_TEMP;


// PointId = 015320   Analogue Point
      L     "IMAC_KONGSBERG_OUT".adw[299];
      RND   ;
      T     "PMA_KONGSBERG_SEND".DG_5_EXH_GAS_CYL_10_TEMP;


// PointId = 015330   Analogue Point
      L     "IMAC_KONGSBERG_OUT".adw[300];
      RND   ;
      T     "PMA_KONGSBERG_SEND".DG_5_EXH_GAS_CYL_11_TEMP;


// PointId = 015340   Analogue Point
      L     "IMAC_KONGSBERG_OUT".adw[301];
      RND   ;
      T     "PMA_KONGSBERG_SEND".DG_5_EXH_GAS_CYL_12_TEMP;


// PointId = 015350   Analogue Point
      L     "IMAC_KONGSBERG_OUT".adw[302];
      RND   ;
      T     "PMA_KONGSBERG_SEND".DG_5_EXH_GAS_CYL_13_TEMP;


// PointId = 015360   Analogue Point
      L     "IMAC_KONGSBERG_OUT".adw[303];
      RND   ;
      T     "PMA_KONGSBERG_SEND".DG_5_EXH_GAS_CYL_14_TEMP;


// PointId = 015370   Analogue Point
      L     "IMAC_KONGSBERG_OUT".adw[304];
      RND   ;
      T     "PMA_KONGSBERG_SEND".DG_5_EXH_GAS_CYL_15_TEMP;


// PointId = 015380   Analogue Point
      L     "IMAC_KONGSBERG_OUT".adw[305];
      RND   ;
      T     "PMA_KONGSBERG_SEND".DG_5_EXH_GAS_CYL_16_TEMP;


// PointId = 015550   Analogue Point
      L     "IMAC_KONGSBERG_OUT".adw[306];
      RND   ;
      T     "PMA_KONGSBERG_SEND".DG_5_EXH_CYL_TEMP_MEAN;


// PointId = 015560   Analogue Point
      L     "IMAC_KONGSBERG_OUT".adw[307];
      RND   ;
      T     "PMA_KONGSBERG_SEND".DG_5_EXH_GAS_TEMP_COMP;
NETWORK
TITLE = DG 6 Binary Points
// *** TELEGRAM 3 ***   Block 3
// PointId = 016010   Binary Point
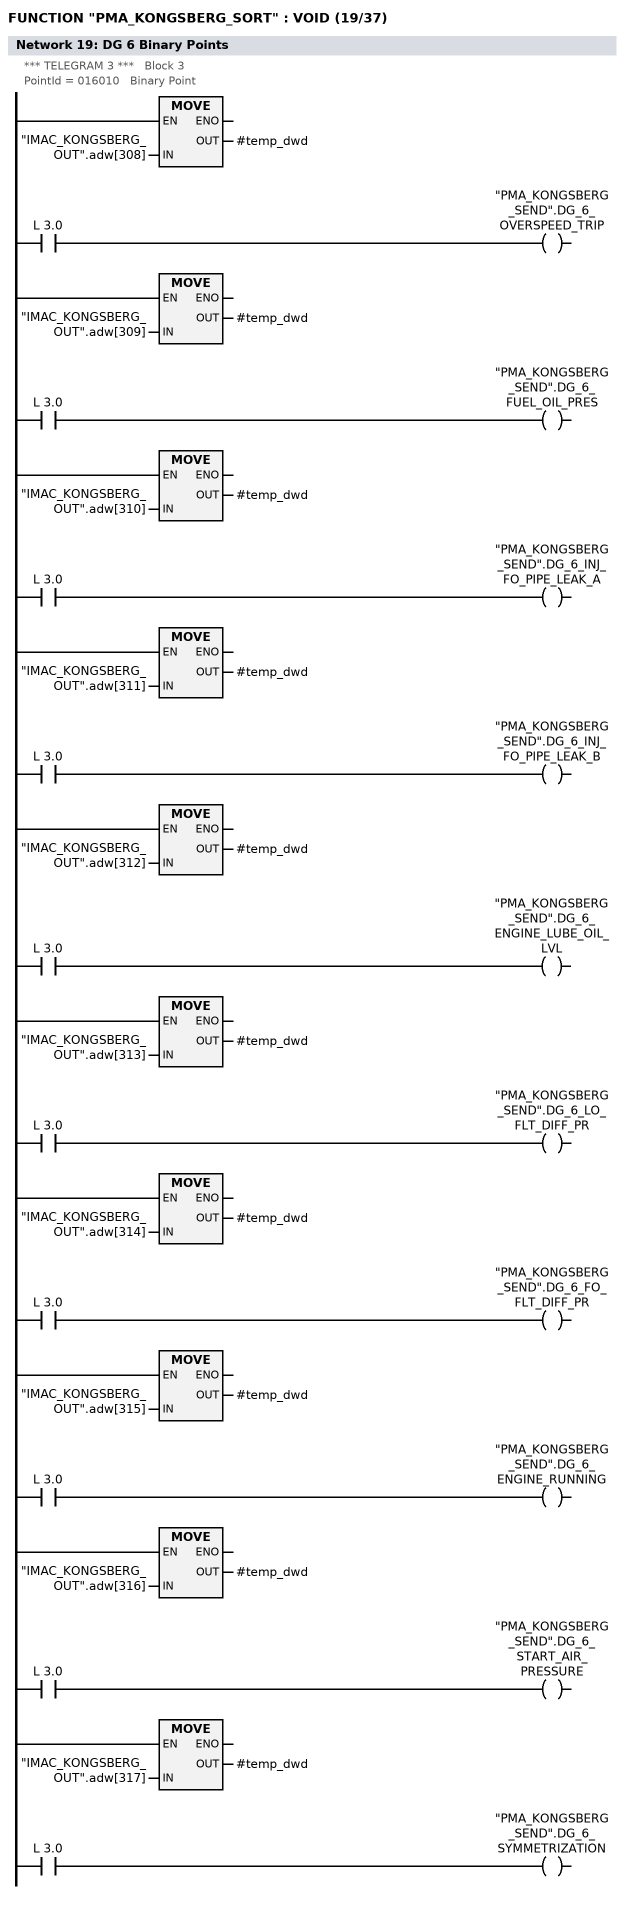
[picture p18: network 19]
      L     "IMAC_KONGSBERG_OUT".adw[308];
      T     #temp_dwd;
      U     L      3.0;
      =     "PMA_KONGSBERG_SEND".DG_6_OVERSPEED_TRIP;


// PointId = 016080   Binary Point
      L     "IMAC_KONGSBERG_OUT".adw[309];
      T     #temp_dwd;
      U     L      3.0;
      =     "PMA_KONGSBERG_SEND".DG_6_FUEL_OIL_PRES;


// PointId = 016160   Binary Point
      L     "IMAC_KONGSBERG_OUT".adw[310];
      T     #temp_dwd;
      U     L      3.0;
      =     "PMA_KONGSBERG_SEND".DG_6_INJ_FO_PIPE_LEAK_A;


// PointId = 016170   Binary Point
      L     "IMAC_KONGSBERG_OUT".adw[311];
      T     #temp_dwd;
      U     L      3.0;
      =     "PMA_KONGSBERG_SEND".DG_6_INJ_FO_PIPE_LEAK_B;


// PointId = 016180   Binary Point
      L     "IMAC_KONGSBERG_OUT".adw[312];
      T     #temp_dwd;
      U     L      3.0;
      =     "PMA_KONGSBERG_SEND".DG_6_ENGINE_LUBE_OIL_LVL;


// PointId = 016200   Binary Point
      L     "IMAC_KONGSBERG_OUT".adw[313];
      T     #temp_dwd;
      U     L      3.0;
      =     "PMA_KONGSBERG_SEND".DG_6_LO_FLT_DIFF_PR;


// PointId = 016210   Binary Point
      L     "IMAC_KONGSBERG_OUT".adw[314];
      T     #temp_dwd;
      U     L      3.0;
      =     "PMA_KONGSBERG_SEND".DG_6_FO_FLT_DIFF_PR;


// PointId = 016030   Binary Point
      L     "IMAC_KONGSBERG_OUT".adw[315];
      T     #temp_dwd;
      U     L      3.0;
      =     "PMA_KONGSBERG_SEND".DG_6_ENGINE_RUNNING;


// PointId = 016190   Binary Point
      L     "IMAC_KONGSBERG_OUT".adw[316];
      T     #temp_dwd;
      U     L      3.0;
      =     "PMA_KONGSBERG_SEND".DG_6_START_AIR_PRESSURE;


// PointId = 016570   Binary Point
      L     "IMAC_KONGSBERG_OUT".adw[317];
      T     #temp_dwd;
      U     L      3.0;
      =     "PMA_KONGSBERG_SEND".DG_6_SYMMETRIZATION;
NETWORK
TITLE = DG 6 Analogue Points

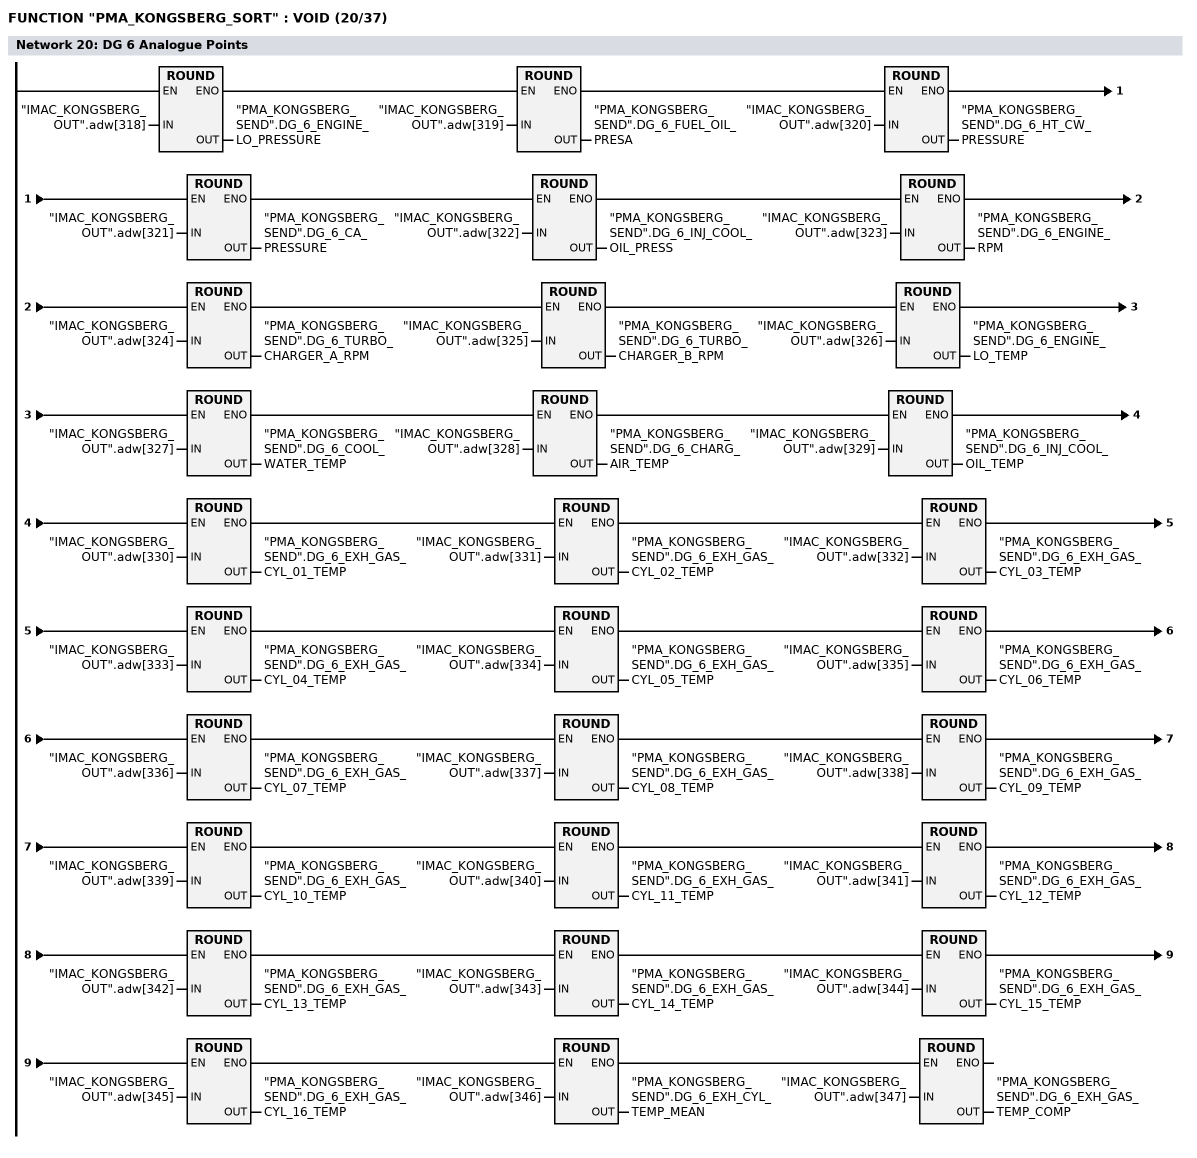
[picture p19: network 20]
//  PointId = 016060   Analogue Point
      L     "IMAC_KONGSBERG_OUT".adw[318];
      RND   ;
      T     "PMA_KONGSBERG_SEND".DG_6_ENGINE_LO_PRESSURE;


// PointId = 016080   Analogue Point
      L     "IMAC_KONGSBERG_OUT".adw[319];
      RND   ;
      T     "PMA_KONGSBERG_SEND".DG_6_FUEL_OIL_PRESA;


// PointId = 016090   Analogue Point
      L     "IMAC_KONGSBERG_OUT".adw[320];
      RND   ;
      T     "PMA_KONGSBERG_SEND".DG_6_HT_CW_PRESSURE;


// PointId = 016110   Analogue Point
      L     "IMAC_KONGSBERG_OUT".adw[321];
      RND   ;
      T     "PMA_KONGSBERG_SEND".DG_6_CA_PRESSURE;


// PointId = 016130   Analogue Point
      L     "IMAC_KONGSBERG_OUT".adw[322];
      RND   ;
      T     "PMA_KONGSBERG_SEND".DG_6_INJ_COOL_OIL_PRESS;


// PointId = 016020   Analogue Point
      L     "IMAC_KONGSBERG_OUT".adw[323];
      RND   ;
      T     "PMA_KONGSBERG_SEND".DG_6_ENGINE_RPM;


// PointId = 016040   Analogue Point
      L     "IMAC_KONGSBERG_OUT".adw[324];
      RND   ;
      T     "PMA_KONGSBERG_SEND".DG_6_TURBO_CHARGER_A_RPM;


// PointId = 016050   Analogue Point
      L     "IMAC_KONGSBERG_OUT".adw[325];
      RND   ;
      T     "PMA_KONGSBERG_SEND".DG_6_TURBO_CHARGER_B_RPM;


// PointId = 016070   Analogue Point
      L     "IMAC_KONGSBERG_OUT".adw[326];
      RND   ;
      T     "PMA_KONGSBERG_SEND".DG_6_ENGINE_LO_TEMP;


// PointId = 016100   Analogue Point
      L     "IMAC_KONGSBERG_OUT".adw[327];
      RND   ;
      T     "PMA_KONGSBERG_SEND".DG_6_COOL_WATER_TEMP;


// PointId = 016120   Analogue Point
      L     "IMAC_KONGSBERG_OUT".adw[328];
      RND   ;
      T     "PMA_KONGSBERG_SEND".DG_6_CHARG_AIR_TEMP;


// PointId = 016140   Analogue Point
      L     "IMAC_KONGSBERG_OUT".adw[329];
      RND   ;
      T     "PMA_KONGSBERG_SEND".DG_6_INJ_COOL_OIL_TEMP;


// PointId = 016230   Analogue Point
      L     "IMAC_KONGSBERG_OUT".adw[330];
      RND   ;
      T     "PMA_KONGSBERG_SEND".DG_6_EXH_GAS_CYL_01_TEMP;


// PointId = 016240   Analogue Point
      L     "IMAC_KONGSBERG_OUT".adw[331];
      RND   ;
      T     "PMA_KONGSBERG_SEND".DG_6_EXH_GAS_CYL_02_TEMP;


// PointId = 016250   Analogue Point
      L     "IMAC_KONGSBERG_OUT".adw[332];
      RND   ;
      T     "PMA_KONGSBERG_SEND".DG_6_EXH_GAS_CYL_03_TEMP;


// PointId = 016260   Analogue Point
      L     "IMAC_KONGSBERG_OUT".adw[333];
      RND   ;
      T     "PMA_KONGSBERG_SEND".DG_6_EXH_GAS_CYL_04_TEMP;


// PointId = 016270   Analogue Point
      L     "IMAC_KONGSBERG_OUT".adw[334];
      RND   ;
      T     "PMA_KONGSBERG_SEND".DG_6_EXH_GAS_CYL_05_TEMP;


// PointId = 016280   Analogue Point
      L     "IMAC_KONGSBERG_OUT".adw[335];
      RND   ;
      T     "PMA_KONGSBERG_SEND".DG_6_EXH_GAS_CYL_06_TEMP;


// PointId = 016290   Analogue Point
      L     "IMAC_KONGSBERG_OUT".adw[336];
      RND   ;
      T     "PMA_KONGSBERG_SEND".DG_6_EXH_GAS_CYL_07_TEMP;


// PointId = 016300   Analogue Point
      L     "IMAC_KONGSBERG_OUT".adw[337];
      RND   ;
      T     "PMA_KONGSBERG_SEND".DG_6_EXH_GAS_CYL_08_TEMP;


// PointId = 016310   Analogue Point
      L     "IMAC_KONGSBERG_OUT".adw[338];
      RND   ;
      T     "PMA_KONGSBERG_SEND".DG_6_EXH_GAS_CYL_09_TEMP;


// PointId = 016320   Analogue Point
      L     "IMAC_KONGSBERG_OUT".adw[339];
      RND   ;
      T     "PMA_KONGSBERG_SEND".DG_6_EXH_GAS_CYL_10_TEMP;


// PointId = 016330   Analogue Point
      L     "IMAC_KONGSBERG_OUT".adw[340];
      RND   ;
      T     "PMA_KONGSBERG_SEND".DG_6_EXH_GAS_CYL_11_TEMP;


// PointId = 016340   Analogue Point
      L     "IMAC_KONGSBERG_OUT".adw[341];
      RND   ;
      T     "PMA_KONGSBERG_SEND".DG_6_EXH_GAS_CYL_12_TEMP;


// PointId = 016350   Analogue Point
      L     "IMAC_KONGSBERG_OUT".adw[342];
      RND   ;
      T     "PMA_KONGSBERG_SEND".DG_6_EXH_GAS_CYL_13_TEMP;


// PointId = 016360   Analogue Point
      L     "IMAC_KONGSBERG_OUT".adw[343];
      RND   ;
      T     "PMA_KONGSBERG_SEND".DG_6_EXH_GAS_CYL_14_TEMP;


// PointId = 016370   Analogue Point
      L     "IMAC_KONGSBERG_OUT".adw[344];
      RND   ;
      T     "PMA_KONGSBERG_SEND".DG_6_EXH_GAS_CYL_15_TEMP;


// PointId = 016380   Analogue Point
      L     "IMAC_KONGSBERG_OUT".adw[345];
      RND   ;
      T     "PMA_KONGSBERG_SEND".DG_6_EXH_GAS_CYL_16_TEMP;


// PointId = 016550   Analogue Point
      L     "IMAC_KONGSBERG_OUT".adw[346];
      RND   ;
      T     "PMA_KONGSBERG_SEND".DG_6_EXH_CYL_TEMP_MEAN;


// PointId = 016560   Analogue Point
      L     "IMAC_KONGSBERG_OUT".adw[347];
      RND   ;
      T     "PMA_KONGSBERG_SEND".DG_6_EXH_GAS_TEMP_COMP;
NETWORK
TITLE = GEN 5 Analogue Points
// *** TELEGRAM 3 ***   Block 4
// PointId = 025010   Analogue Point
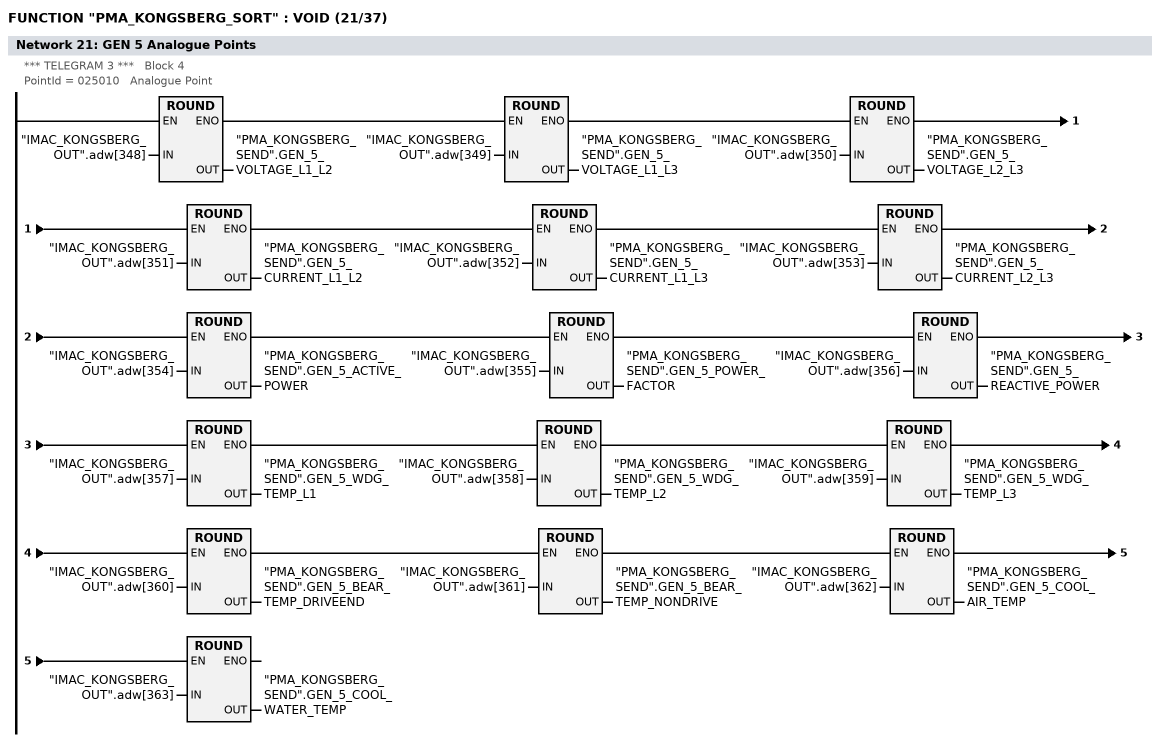
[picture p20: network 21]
      L     "IMAC_KONGSBERG_OUT".adw[348];
      RND   ;
      T     "PMA_KONGSBERG_SEND".GEN_5_VOLTAGE_L1_L2;


// PointId = 025020   Analogue Point
      L     "IMAC_KONGSBERG_OUT".adw[349];
      RND   ;
      T     "PMA_KONGSBERG_SEND".GEN_5_VOLTAGE_L1_L3;


// PointId = 025030   Analogue Point
      L     "IMAC_KONGSBERG_OUT".adw[350];
      RND   ;
      T     "PMA_KONGSBERG_SEND".GEN_5_VOLTAGE_L2_L3;


// PointId = 025040   Analogue Point
      L     "IMAC_KONGSBERG_OUT".adw[351];
      RND   ;
      T     "PMA_KONGSBERG_SEND".GEN_5_CURRENT_L1_L2;


// PointId = 025051   Analogue Point
      L     "IMAC_KONGSBERG_OUT".adw[352];
      RND   ;
      T     "PMA_KONGSBERG_SEND".GEN_5_CURRENT_L1_L3;


// PointId = 025060   Analogue Point
      L     "IMAC_KONGSBERG_OUT".adw[353];
      RND   ;
      T     "PMA_KONGSBERG_SEND".GEN_5_CURRENT_L2_L3;


// PointId = 025070   Analogue Point
      L     "IMAC_KONGSBERG_OUT".adw[354];
      RND   ;
      T     "PMA_KONGSBERG_SEND".GEN_5_ACTIVE_POWER;


// PointId = 025080   Analogue Point
      L     "IMAC_KONGSBERG_OUT".adw[355];
      RND   ;
      T     "PMA_KONGSBERG_SEND".GEN_5_POWER_FACTOR;


// PointId = 025090   Analogue Point
      L     "IMAC_KONGSBERG_OUT".adw[356];
      RND   ;
      T     "PMA_KONGSBERG_SEND".GEN_5_REACTIVE_POWER;


// PointId = 025120   Analogue Point
      L     "IMAC_KONGSBERG_OUT".adw[357];
      RND   ;
      T     "PMA_KONGSBERG_SEND".GEN_5_WDG_TEMP_L1;


// PointId = 025130   Analogue Point
      L     "IMAC_KONGSBERG_OUT".adw[358];
      RND   ;
      T     "PMA_KONGSBERG_SEND".GEN_5_WDG_TEMP_L2;


// PointId = 025140   Analogue Point
      L     "IMAC_KONGSBERG_OUT".adw[359];
      RND   ;
      T     "PMA_KONGSBERG_SEND".GEN_5_WDG_TEMP_L3;


// PointId = 025150   Analogue Point
      L     "IMAC_KONGSBERG_OUT".adw[360];
      RND   ;
      T     "PMA_KONGSBERG_SEND".GEN_5_BEAR_TEMP_DRIVEEND;


// PointId = 025160   Analogue Point
      L     "IMAC_KONGSBERG_OUT".adw[361];
      RND   ;
      T     "PMA_KONGSBERG_SEND".GEN_5_BEAR_TEMP_NONDRIVE;


// PointId = 025170   Analogue Point
      L     "IMAC_KONGSBERG_OUT".adw[362];
      RND   ;
      T     "PMA_KONGSBERG_SEND".GEN_5_COOL_AIR_TEMP;


// PointId = 025180   Analogue Point
      L     "IMAC_KONGSBERG_OUT".adw[363];
      RND   ;
      T     "PMA_KONGSBERG_SEND".GEN_5_COOL_WATER_TEMP;
NETWORK
TITLE = GEN 5 Binary Points
// *** TELEGRAM 3 ***   Block 5
//  PointId = 025100   Binary Point
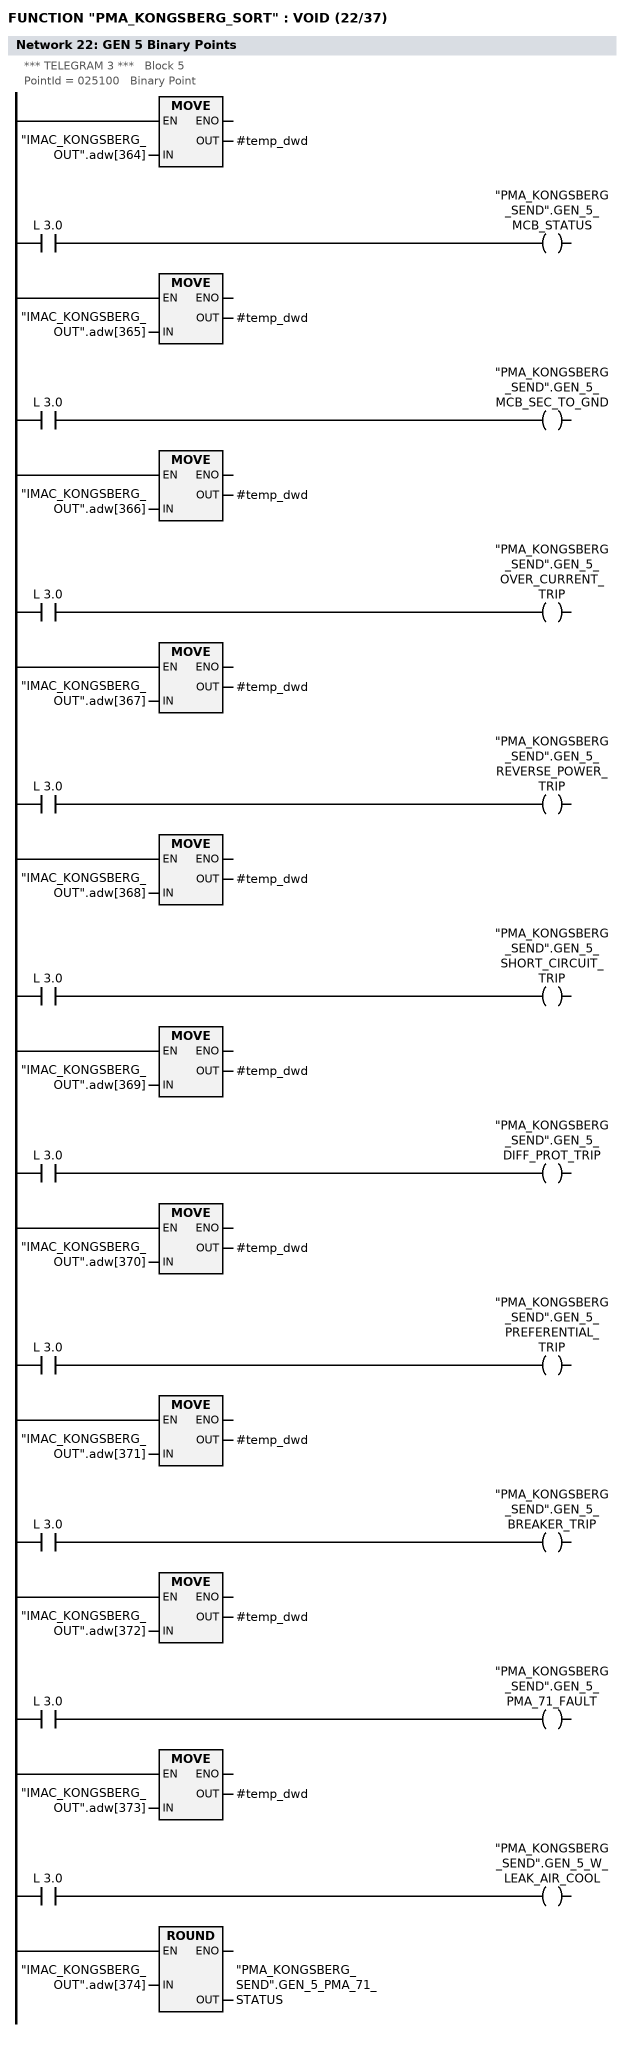
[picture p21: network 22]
      L     "IMAC_KONGSBERG_OUT".adw[364];
      T     #temp_dwd;
      U     L      3.0;
      =     "PMA_KONGSBERG_SEND".GEN_5_MCB_STATUS;


// PointId = 025110   Binary Point
      L     "IMAC_KONGSBERG_OUT".adw[365];
      T     #temp_dwd;
      U     L      3.0;
      =     "PMA_KONGSBERG_SEND".GEN_5_MCB_SEC_TO_GND;


// PointId = 025190   Binary Point
      L     "IMAC_KONGSBERG_OUT".adw[366];
      T     #temp_dwd;
      U     L      3.0;
      =     "PMA_KONGSBERG_SEND".GEN_5_OVER_CURRENT_TRIP;


// PointId = 025200   Binary Point
      L     "IMAC_KONGSBERG_OUT".adw[367];
      T     #temp_dwd;
      U     L      3.0;
      =     "PMA_KONGSBERG_SEND".GEN_5_REVERSE_POWER_TRIP;


// PointId = 025210   Binary Point
      L     "IMAC_KONGSBERG_OUT".adw[368];
      T     #temp_dwd;
      U     L      3.0;
      =     "PMA_KONGSBERG_SEND".GEN_5_SHORT_CIRCUIT_TRIP;


// PointId = 025240   Binary Point
      L     "IMAC_KONGSBERG_OUT".adw[369];
      T     #temp_dwd;
      U     L      3.0;
      =     "PMA_KONGSBERG_SEND".GEN_5_DIFF_PROT_TRIP;


// PointId = 025260   Binary Point
      L     "IMAC_KONGSBERG_OUT".adw[370];
      T     #temp_dwd;
      U     L      3.0;
      =     "PMA_KONGSBERG_SEND".GEN_5_PREFERENTIAL_TRIP;


// PointId = 025270   Binary Point
      L     "IMAC_KONGSBERG_OUT".adw[371];
      T     #temp_dwd;
      U     L      3.0;
      =     "PMA_KONGSBERG_SEND".GEN_5_BREAKER_TRIP;


// PointId = 025290   Binary Point
      L     "IMAC_KONGSBERG_OUT".adw[372];
      T     #temp_dwd;
      U     L      3.0;
      =     "PMA_KONGSBERG_SEND".GEN_5_PMA_71_FAULT;


// PointId = 025310   Binary Point
      L     "IMAC_KONGSBERG_OUT".adw[373];
      T     #temp_dwd;
      U     L      3.0;
      =     "PMA_KONGSBERG_SEND".GEN_5_W_LEAK_AIR_COOL;


//  PointId = 025300   Analogue Point
      L     "IMAC_KONGSBERG_OUT".adw[374];
      RND   ;
      T     "PMA_KONGSBERG_SEND".GEN_5_PMA_71_STATUS;
NETWORK
TITLE = GEN 6 Analogue Points
// *** TELEGRAM 3 ***   Block 6
// PointId = 026010   Analogue Point
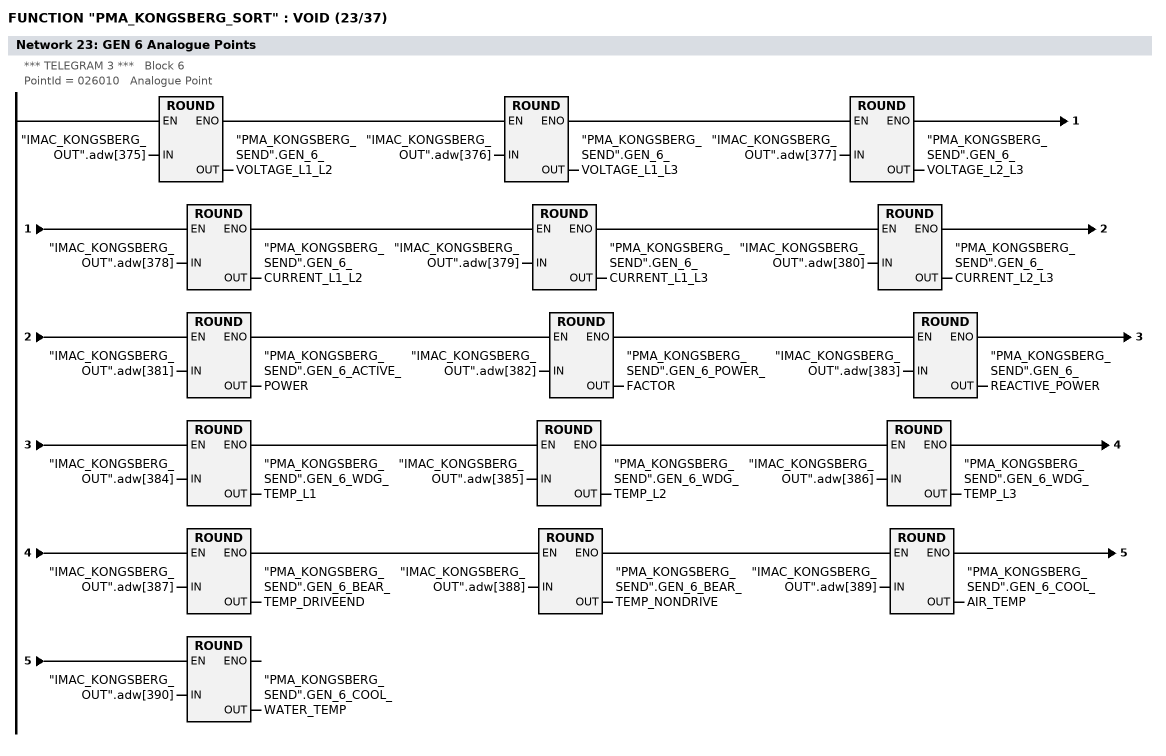
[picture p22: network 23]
      L     "IMAC_KONGSBERG_OUT".adw[375];
      RND   ;
      T     "PMA_KONGSBERG_SEND".GEN_6_VOLTAGE_L1_L2;


// PointId = 026020   Analogue Point
      L     "IMAC_KONGSBERG_OUT".adw[376];
      RND   ;
      T     "PMA_KONGSBERG_SEND".GEN_6_VOLTAGE_L1_L3;


// PointId = 026030   Analogue Point
      L     "IMAC_KONGSBERG_OUT".adw[377];
      RND   ;
      T     "PMA_KONGSBERG_SEND".GEN_6_VOLTAGE_L2_L3;


// PointId = 026040   Analogue Point
      L     "IMAC_KONGSBERG_OUT".adw[378];
      RND   ;
      T     "PMA_KONGSBERG_SEND".GEN_6_CURRENT_L1_L2;


// PointId = 026051   Analogue Point
      L     "IMAC_KONGSBERG_OUT".adw[379];
      RND   ;
      T     "PMA_KONGSBERG_SEND".GEN_6_CURRENT_L1_L3;


// PointId = 026060   Analogue Point
      L     "IMAC_KONGSBERG_OUT".adw[380];
      RND   ;
      T     "PMA_KONGSBERG_SEND".GEN_6_CURRENT_L2_L3;


// PointId = 026070   Analogue Point
      L     "IMAC_KONGSBERG_OUT".adw[381];
      RND   ;
      T     "PMA_KONGSBERG_SEND".GEN_6_ACTIVE_POWER;


// PointId = 026080   Analogue Point
      L     "IMAC_KONGSBERG_OUT".adw[382];
      RND   ;
      T     "PMA_KONGSBERG_SEND".GEN_6_POWER_FACTOR;


// PointId = 026090   Analogue Point
      L     "IMAC_KONGSBERG_OUT".adw[383];
      RND   ;
      T     "PMA_KONGSBERG_SEND".GEN_6_REACTIVE_POWER;


// PointId = 026120   Analogue Point
      L     "IMAC_KONGSBERG_OUT".adw[384];
      RND   ;
      T     "PMA_KONGSBERG_SEND".GEN_6_WDG_TEMP_L1;


// PointId = 026130   Analogue Point
      L     "IMAC_KONGSBERG_OUT".adw[385];
      RND   ;
      T     "PMA_KONGSBERG_SEND".GEN_6_WDG_TEMP_L2;


// PointId = 026140   Analogue Point
      L     "IMAC_KONGSBERG_OUT".adw[386];
      RND   ;
      T     "PMA_KONGSBERG_SEND".GEN_6_WDG_TEMP_L3;


// PointId = 026150   Analogue Point
      L     "IMAC_KONGSBERG_OUT".adw[387];
      RND   ;
      T     "PMA_KONGSBERG_SEND".GEN_6_BEAR_TEMP_DRIVEEND;


// PointId = 026160   Analogue Point
      L     "IMAC_KONGSBERG_OUT".adw[388];
      RND   ;
      T     "PMA_KONGSBERG_SEND".GEN_6_BEAR_TEMP_NONDRIVE;


// PointId = 026170   Analogue Point
      L     "IMAC_KONGSBERG_OUT".adw[389];
      RND   ;
      T     "PMA_KONGSBERG_SEND".GEN_6_COOL_AIR_TEMP;


// PointId = 026180   Analogue Point
      L     "IMAC_KONGSBERG_OUT".adw[390];
      RND   ;
      T     "PMA_KONGSBERG_SEND".GEN_6_COOL_WATER_TEMP;
NETWORK
TITLE = GEN 6 Binary Points
// *** TELEGRAM 3 ***   Block 7
// PointId = 026100   Binary Point
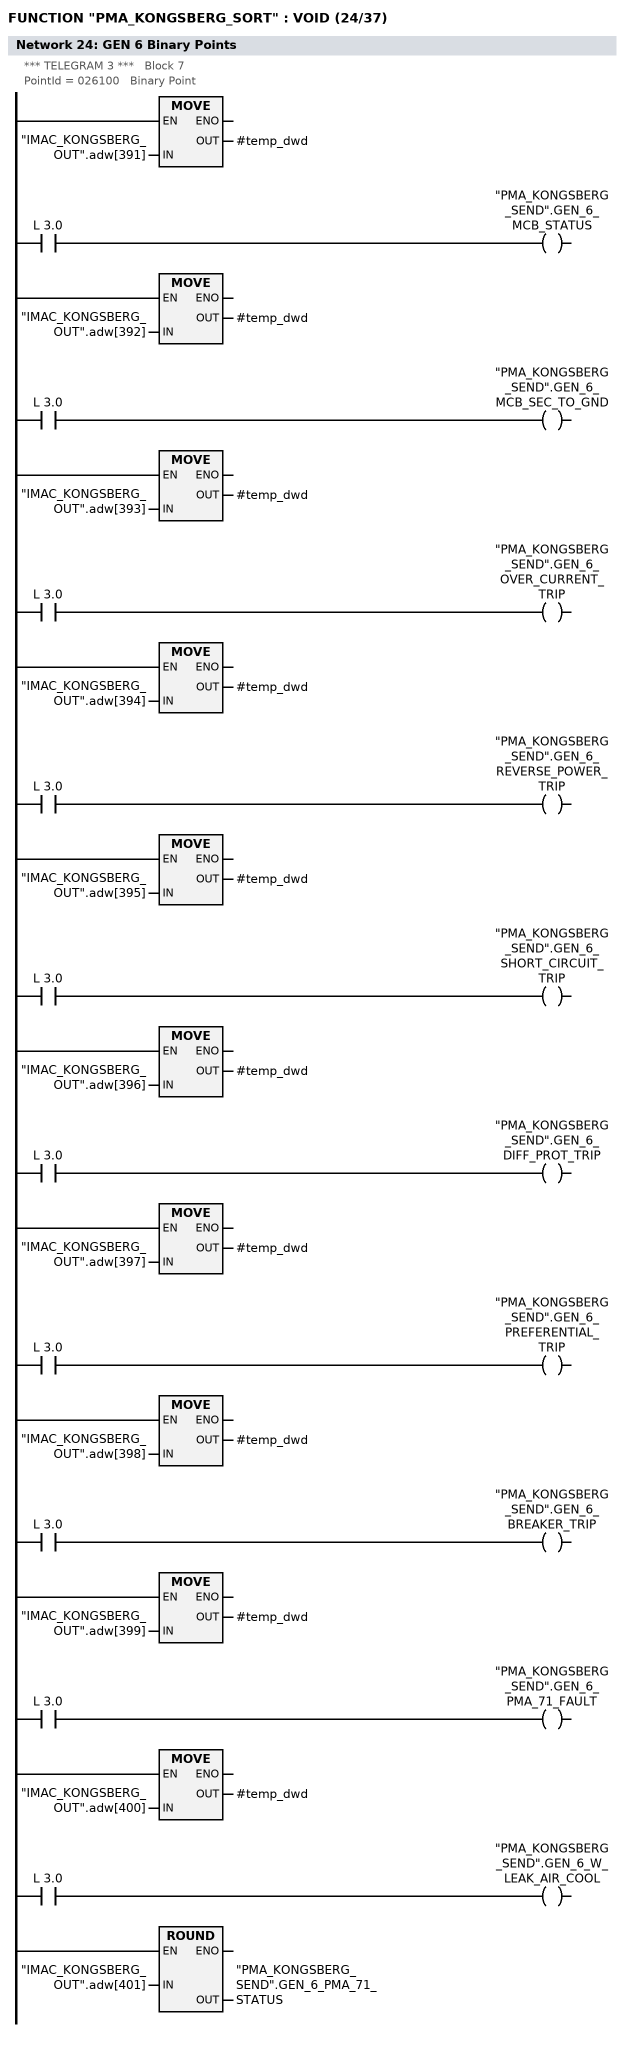
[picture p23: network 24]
      L     "IMAC_KONGSBERG_OUT".adw[391];
      T     #temp_dwd;
      U     L      3.0;
      =     "PMA_KONGSBERG_SEND".GEN_6_MCB_STATUS;


// PointId = 026110   Binary Point
      L     "IMAC_KONGSBERG_OUT".adw[392];
      T     #temp_dwd;
      U     L      3.0;
      =     "PMA_KONGSBERG_SEND".GEN_6_MCB_SEC_TO_GND;


// PointId = 026190   Binary Point
      L     "IMAC_KONGSBERG_OUT".adw[393];
      T     #temp_dwd;
      U     L      3.0;
      =     "PMA_KONGSBERG_SEND".GEN_6_OVER_CURRENT_TRIP;


// PointId = 026200   Binary Point
      L     "IMAC_KONGSBERG_OUT".adw[394];
      T     #temp_dwd;
      U     L      3.0;
      =     "PMA_KONGSBERG_SEND".GEN_6_REVERSE_POWER_TRIP;


// PointId = 026210   Binary Point
      L     "IMAC_KONGSBERG_OUT".adw[395];
      T     #temp_dwd;
      U     L      3.0;
      =     "PMA_KONGSBERG_SEND".GEN_6_SHORT_CIRCUIT_TRIP;


// PointId = 026240   Binary Point
      L     "IMAC_KONGSBERG_OUT".adw[396];
      T     #temp_dwd;
      U     L      3.0;
      =     "PMA_KONGSBERG_SEND".GEN_6_DIFF_PROT_TRIP;


// PointId = 026260   Binary Point
      L     "IMAC_KONGSBERG_OUT".adw[397];
      T     #temp_dwd;
      U     L      3.0;
      =     "PMA_KONGSBERG_SEND".GEN_6_PREFERENTIAL_TRIP;


// PointId = 026270   Binary Point
      L     "IMAC_KONGSBERG_OUT".adw[398];
      T     #temp_dwd;
      U     L      3.0;
      =     "PMA_KONGSBERG_SEND".GEN_6_BREAKER_TRIP;


// PointId = 026290   Binary Point
      L     "IMAC_KONGSBERG_OUT".adw[399];
      T     #temp_dwd;
      U     L      3.0;
      =     "PMA_KONGSBERG_SEND".GEN_6_PMA_71_FAULT;


// PointId = 026310   Binary Point
      L     "IMAC_KONGSBERG_OUT".adw[400];
      T     #temp_dwd;
      U     L      3.0;
      =     "PMA_KONGSBERG_SEND".GEN_6_W_LEAK_AIR_COOL;


// PointId = 026300   Analogue Point
      L     "IMAC_KONGSBERG_OUT".adw[401];
      RND   ;
      T     "PMA_KONGSBERG_SEND".GEN_6_PMA_71_STATUS;
NETWORK
TITLE = DG 7 Binary Points
// *** TELEGRAM 4 ***   Block 2
// PointId = 017110   Binary Point
      L     "IMAC_KONGSBERG_OUT".adw[402];
      T     #temp_dwd;
      U     L      3.0;
      =     "PMA_KONGSBERG_SEND".DG_7_ENG_COOL_LVL;


// PointId = 017010   Binary Point
      L     "IMAC_KONGSBERG_OUT".adw[403];
      T     #temp_dwd;
      U     L      3.0;
      =     "PMA_KONGSBERG_SEND".DG_7_ENG_LO_PRESS;


// PointId = 017070   Binary Point
      L     "IMAC_KONGSBERG_OUT".adw[404];
      T     #temp_dwd;
      U     L      3.0;
      =     "PMA_KONGSBERG_SEND".DG_7_FO_FLT_DIFF_PR;


// PointId = 017080   Binary Point
      L     "IMAC_KONGSBERG_OUT".adw[405];
      T     #temp_dwd;
      U     L      3.0;
      =     "PMA_KONGSBERG_SEND".DG_7_LO_FLT_DIFF_PR;


// PointId = 017090   Binary Point
      L     "IMAC_KONGSBERG_OUT".adw[406];
      T     #temp_dwd;
      U     L      3.0;
      =     "PMA_KONGSBERG_SEND".DG_7_ENG_CRK_CASE_PR;


// PointId = 017130   Binary Point
      L     "IMAC_KONGSBERG_OUT".adw[407];
      T     #temp_dwd;
      U     L      3.0;
      =     "PMA_KONGSBERG_SEND".DG_7_MAR_GEAR_OIL_PR;


// PointId = 017020   Binary Point
      L     "IMAC_KONGSBERG_OUT".adw[408];
      T     #temp_dwd;
      U     L      3.0;
      =     "PMA_KONGSBERG_SEND".DG_7_ENG_JACK_WT_TEMP_HI;


// PointId = 017030   Binary Point
      L     "IMAC_KONGSBERG_OUT".adw[409];
      T     #temp_dwd;
      U     L      3.0;
      =     "PMA_KONGSBERG_SEND".DG_7_ENG_JACK_WT_TEMP_LO;


// PointId = 017060   Binary Point
      L     "IMAC_KONGSBERG_OUT".adw[410];
      T     #temp_dwd;
      U     L      3.0;
      =     "PMA_KONGSBERG_SEND".DG_7_ENG_EXH_GAS_TEMP;


// PointId = 017100   Binary Point
      L     "IMAC_KONGSBERG_OUT".adw[411];
      T     #temp_dwd;
      U     L      3.0;
      =     "PMA_KONGSBERG_SEND".DG_7_ENG_AFT_COOL_TEMP;


// PointId = 017120   Binary Point
      L     "IMAC_KONGSBERG_OUT".adw[412];
      T     #temp_dwd;
      U     L      3.0;
      =     "PMA_KONGSBERG_SEND".DG_7_MAR_GEAR_OIL_TEMP;


// PointId = 017040   Binary Point
      L     "IMAC_KONGSBERG_OUT".adw[413];
      T     #temp_dwd;
      U     L      3.0;
      =     "PMA_KONGSBERG_SEND".DG_7_ENG_OVERSPEED;


// PointId = 017140   Binary Point
      L     "IMAC_KONGSBERG_OUT".adw[414];
      T     #temp_dwd;
      U     L      3.0;
      =     "PMA_KONGSBERG_SEND".DG_7_EL_FUEL_INJ;


// PointId = 017050   Binary Point
      L     "IMAC_KONGSBERG_OUT".adw[415];
      T     #temp_dwd;
      U     L      3.0;
      =     "PMA_KONGSBERG_SEND".DG_7_ENG_AIR_RESTR;


// PointId = 017490   Binary Point
      L     "IMAC_KONGSBERG_OUT".adw[416];
      T     #temp_dwd;
      U     L      3.0;
      =     "PMA_KONGSBERG_SEND".DG_7_SYMMETRIZATION;
NETWORK
TITLE = DG 7 Analogue Points

// PointId = 017150   Analogue Point
      L     "IMAC_KONGSBERG_OUT".adw[417];
      RND   ;
      T     "PMA_KONGSBERG_SEND".DG_7_EXH_GAS_CYL_01_TEMP;


// PointId = 017160   Analogue Point
      L     "IMAC_KONGSBERG_OUT".adw[418];
      RND   ;
      T     "PMA_KONGSBERG_SEND".DG_7_EXH_GAS_CYL_02_TEMP;


// PointId = 017170   Analogue Point
      L     "IMAC_KONGSBERG_OUT".adw[419];
      RND   ;
      T     "PMA_KONGSBERG_SEND".DG_7_EXH_GAS_CYL_03_TEMP;


// PointId = 017180   Analogue Point
      L     "IMAC_KONGSBERG_OUT".adw[420];
      RND   ;
      T     "PMA_KONGSBERG_SEND".DG_7_EXH_GAS_CYL_04_TEMP;


// PointId = 017190   Analogue Point
      L     "IMAC_KONGSBERG_OUT".adw[421];
      RND   ;
      T     "PMA_KONGSBERG_SEND".DG_7_EXH_GAS_CYL_05_TEMP;


// PointId = 017200   Analogue Point
      L     "IMAC_KONGSBERG_OUT".adw[422];
      RND   ;
      T     "PMA_KONGSBERG_SEND".DG_7_EXH_GAS_CYL_06_TEMP;


// PointId = 017210   Analogue Point
      L     "IMAC_KONGSBERG_OUT".adw[423];
      RND   ;
      T     "PMA_KONGSBERG_SEND".DG_7_EXH_GAS_CYL_07_TEMP;


// PointId = 017220   Analogue Point
      L     "IMAC_KONGSBERG_OUT".adw[424];
      RND   ;
      T     "PMA_KONGSBERG_SEND".DG_7_EXH_GAS_CYL_08_TEMP;


// PointId = 017230   Analogue Point
      L     "IMAC_KONGSBERG_OUT".adw[425];
      RND   ;
      T     "PMA_KONGSBERG_SEND".DG_7_EXH_GAS_CYL_09_TEMP;


// PointId = 017240   Analogue Point
      L     "IMAC_KONGSBERG_OUT".adw[426];
      RND   ;
      T     "PMA_KONGSBERG_SEND".DG_7_EXH_GAS_CYL_10_TEMP;


// PointId = 017250   Analogue Point
      L     "IMAC_KONGSBERG_OUT".adw[427];
      RND   ;
      T     "PMA_KONGSBERG_SEND".DG_7_EXH_GAS_CYL_11_TEMP;


// PointId = 017260   Analogue Point
      L     "IMAC_KONGSBERG_OUT".adw[428];
      RND   ;
      T     "PMA_KONGSBERG_SEND".DG_7_EXH_GAS_CYL_12_TEMP;


// PointId = 017270   Analogue Point
      L     "IMAC_KONGSBERG_OUT".adw[429];
      RND   ;
      T     "PMA_KONGSBERG_SEND".DG_7_EXH_GAS_CYL_13_TEMP;


// PointId = 017280   Analogue Point
      L     "IMAC_KONGSBERG_OUT".adw[430];
      RND   ;
      T     "PMA_KONGSBERG_SEND".DG_7_EXH_GAS_CYL_14_TEMP;


// PointId = 017290   Analogue Point
      L     "IMAC_KONGSBERG_OUT".adw[431];
      RND   ;
      T     "PMA_KONGSBERG_SEND".DG_7_EXH_GAS_CYL_15_TEMP;


// PointId = 017300   Analogue Point
      L     "IMAC_KONGSBERG_OUT".adw[432];
      RND   ;
      T     "PMA_KONGSBERG_SEND".DG_7_EXH_GAS_CYL_16_TEMP;


// PointId = 017470   Analogue Point
      L     "IMAC_KONGSBERG_OUT".adw[433];
      RND   ;
      T     "PMA_KONGSBERG_SEND".DG_7_EXH_CYL_TEMP_MEAN;


// PointId = 017480   Analogue Point
      L     "IMAC_KONGSBERG_OUT".adw[434];
      RND   ;
      T     "PMA_KONGSBERG_SEND".DG_7_EXH_GAS_TEMP_COMP;
NETWORK
TITLE = DG 8 Binary Points
// *** TELEGRAM 4 ***   Block 3
// PointId = 018110   Binary Point
      L     "IMAC_KONGSBERG_OUT".adw[435];
      T     #temp_dwd;
      U     L      3.0;
      =     "PMA_KONGSBERG_SEND".DG_8_ENG_COOL_LVL;


// PointId = 018010   Binary Point
      L     "IMAC_KONGSBERG_OUT".adw[436];
      T     #temp_dwd;
      U     L      3.0;
      =     "PMA_KONGSBERG_SEND".DG_8_ENG_LO_PRESS;


// PointId = 018070   Binary Point
      L     "IMAC_KONGSBERG_OUT".adw[437];
      T     #temp_dwd;
      U     L      3.0;
      =     "PMA_KONGSBERG_SEND".DG_8_FO_FLT_DIFF_PR;


// PointId = 018080   Binary Point
      L     "IMAC_KONGSBERG_OUT".adw[438];
      T     #temp_dwd;
      U     L      3.0;
      =     "PMA_KONGSBERG_SEND".DG_8_LO_FLT_DIFF_PR;


// PointId = 018090   Binary Point
      L     "IMAC_KONGSBERG_OUT".adw[439];
      T     #temp_dwd;
      U     L      3.0;
      =     "PMA_KONGSBERG_SEND".DG_8_ENG_CRK_CASE_PR;


// PointId = 018130   Binary Point
      L     "IMAC_KONGSBERG_OUT".adw[440];
      T     #temp_dwd;
      U     L      3.0;
      =     "PMA_KONGSBERG_SEND".DG_8_MAR_GEAR_OIL_PR;


// PointId = 018020   Binary Point
      L     "IMAC_KONGSBERG_OUT".adw[441];
      T     #temp_dwd;
      U     L      3.0;
      =     "PMA_KONGSBERG_SEND".DG_8_ENG_JACK_WT_TEMP_HI;


// PointId = 018030   Binary Point
      L     "IMAC_KONGSBERG_OUT".adw[442];
      T     #temp_dwd;
      U     L      3.0;
      =     "PMA_KONGSBERG_SEND".DG_8_ENG_JACK_WT_TEMP_LO;


// PointId = 018060   Binary Point
      L     "IMAC_KONGSBERG_OUT".adw[443];
      T     #temp_dwd;
      U     L      3.0;
      =     "PMA_KONGSBERG_SEND".DG_8_ENG_EXH_GAS_TEMP;


// PointId = 018100   Binary Point
      L     "IMAC_KONGSBERG_OUT".adw[444];
      T     #temp_dwd;
      U     L      3.0;
      =     "PMA_KONGSBERG_SEND".DG_8_ENG_AFT_COOL_TEMP;


// PointId = 018120   Binary Point
      L     "IMAC_KONGSBERG_OUT".adw[445];
      T     #temp_dwd;
      U     L      3.0;
      =     "PMA_KONGSBERG_SEND".DG_8_MAR_GEAR_OIL_TEMP;


// PointId = 018040   Binary Point
      L     "IMAC_KONGSBERG_OUT".adw[446];
      T     #temp_dwd;
      U     L      3.0;
      =     "PMA_KONGSBERG_SEND".DG_8_ENG_OVERSPEED;


// PointId = 018140   Binary Point
      L     "IMAC_KONGSBERG_OUT".adw[447];
      T     #temp_dwd;
      U     L      3.0;
      =     "PMA_KONGSBERG_SEND".DG_8_EL_FUEL_INJ;


// PointId = 018050   Binary Point
      L     "IMAC_KONGSBERG_OUT".adw[448];
      T     #temp_dwd;
      U     L      3.0;
      =     "PMA_KONGSBERG_SEND".DG_8_ENG_AIR_RESTR;


// PointId = 018490   Binary Point
      L     "IMAC_KONGSBERG_OUT".adw[449];
      T     #temp_dwd;
      U     L      3.0;
      =     "PMA_KONGSBERG_SEND".DG_8_SYMMETRIZATION;
NETWORK
TITLE = DG 8 Analogue Points

// PointId = 018150   Analogue Point
      L     "IMAC_KONGSBERG_OUT".adw[450];
      RND   ;
      T     "PMA_KONGSBERG_SEND".DG_8_EXH_GAS_CYL_01_TEMP;


// PointId = 018160   Analogue Point
      L     "IMAC_KONGSBERG_OUT".adw[451];
      RND   ;
      T     "PMA_KONGSBERG_SEND".DG_8_EXH_GAS_CYL_02_TEMP;


// PointId = 018170   Analogue Point
      L     "IMAC_KONGSBERG_OUT".adw[452];
      RND   ;
      T     "PMA_KONGSBERG_SEND".DG_8_EXH_GAS_CYL_03_TEMP;


// PointId = 018180   Analogue Point
      L     "IMAC_KONGSBERG_OUT".adw[453];
      RND   ;
      T     "PMA_KONGSBERG_SEND".DG_8_EXH_GAS_CYL_04_TEMP;


// PointId = 018190   Analogue Point
      L     "IMAC_KONGSBERG_OUT".adw[454];
      RND   ;
      T     "PMA_KONGSBERG_SEND".DG_8_EXH_GAS_CYL_05_TEMP;


// PointId = 018200   Analogue Point
      L     "IMAC_KONGSBERG_OUT".adw[455];
      RND   ;
      T     "PMA_KONGSBERG_SEND".DG_8_EXH_GAS_CYL_06_TEMP;


// PointId = 018210   Analogue Point
      L     "IMAC_KONGSBERG_OUT".adw[456];
      RND   ;
      T     "PMA_KONGSBERG_SEND".DG_8_EXH_GAS_CYL_07_TEMP;


// PointId = 018220   Analogue Point
      L     "IMAC_KONGSBERG_OUT".adw[457];
      RND   ;
      T     "PMA_KONGSBERG_SEND".DG_8_EXH_GAS_CYL_08_TEMP;


// PointId = 018230   Analogue Point
      L     "IMAC_KONGSBERG_OUT".adw[458];
      RND   ;
      T     "PMA_KONGSBERG_SEND".DG_8_EXH_GAS_CYL_09_TEMP;


// PointId = 018240   Analogue Point
      L     "IMAC_KONGSBERG_OUT".adw[459];
      RND   ;
      T     "PMA_KONGSBERG_SEND".DG_8_EXH_GAS_CYL_10_TEMP;


// PointId = 018250   Analogue Point
      L     "IMAC_KONGSBERG_OUT".adw[460];
      RND   ;
      T     "PMA_KONGSBERG_SEND".DG_8_EXH_GAS_CYL_11_TEMP;


// PointId = 018260   Analogue Point
      L     "IMAC_KONGSBERG_OUT".adw[461];
      RND   ;
      T     "PMA_KONGSBERG_SEND".DG_8_EXH_GAS_CYL_12_TEMP;


// PointId = 018270   Analogue Point
      L     "IMAC_KONGSBERG_OUT".adw[462];
      RND   ;
      T     "PMA_KONGSBERG_SEND".DG_8_EXH_GAS_CYL_13_TEMP;


// PointId = 018280   Analogue Point
      L     "IMAC_KONGSBERG_OUT".adw[463];
      RND   ;
      T     "PMA_KONGSBERG_SEND".DG_8_EXH_GAS_CYL_14_TEMP;


// PointId = 018290   Analogue Point
      L     "IMAC_KONGSBERG_OUT".adw[464];
      RND   ;
      T     "PMA_KONGSBERG_SEND".DG_8_EXH_GAS_CYL_15_TEMP;


// PointId = 018300   Analogue Point
      L     "IMAC_KONGSBERG_OUT".adw[465];
      RND   ;
      T     "PMA_KONGSBERG_SEND".DG_8_EXH_GAS_CYL_16_TEMP;


// PointId = 018470   Analogue Point
      L     "IMAC_KONGSBERG_OUT".adw[466];
      RND   ;
      T     "PMA_KONGSBERG_SEND".DG_8_EXH_CYL_TEMP_MEAN;


// PointId = 018480   Analogue Point
      L     "IMAC_KONGSBERG_OUT".adw[467];
      RND   ;
      T     "PMA_KONGSBERG_SEND".DG_8_EXH_GAS_TEMP_COMP;
NETWORK
TITLE = GEN 7 Analogue Points
// *** TELEGRAM 4 ***   Block 4
// PointId = 027010   Analogue Point
      L     "IMAC_KONGSBERG_OUT".adw[468];
      RND   ;
      T     "PMA_KONGSBERG_SEND".GEN_7_VOLTAGE_L1_L2;


// PointId = 027020   Analogue Point
      L     "IMAC_KONGSBERG_OUT".adw[469];
      RND   ;
      T     "PMA_KONGSBERG_SEND".GEN_7_VOLTAGE_L1_L3;


// PointId = 027030   Analogue Point
      L     "IMAC_KONGSBERG_OUT".adw[470];
      RND   ;
      T     "PMA_KONGSBERG_SEND".GEN_7_VOLTAGE_L2_L3;


// PointId = 027040   Analogue Point
      L     "IMAC_KONGSBERG_OUT".adw[471];
      RND   ;
      T     "PMA_KONGSBERG_SEND".GEN_7_CURRENT_L1_L2;


// PointId = 027051   Analogue Point
      L     "IMAC_KONGSBERG_OUT".adw[472];
      RND   ;
      T     "PMA_KONGSBERG_SEND".GEN_7_CURRENT_L1_L3;


// PointId = 027060   Analogue Point
      L     "IMAC_KONGSBERG_OUT".adw[473];
      RND   ;
      T     "PMA_KONGSBERG_SEND".GEN_7_CURRENT_L2_L3;


// PointId = 027070   Analogue Point
      L     "IMAC_KONGSBERG_OUT".adw[474];
      RND   ;
      T     "PMA_KONGSBERG_SEND".GEN_7_ACTIVE_POWER;


// PointId = 027080   Analogue Point
      L     "IMAC_KONGSBERG_OUT".adw[475];
      RND   ;
      T     "PMA_KONGSBERG_SEND".GEN_7_POWER_FACTOR;


// PointId = 027090   Analogue Point
      L     "IMAC_KONGSBERG_OUT".adw[476];
      RND   ;
      T     "PMA_KONGSBERG_SEND".GEN_7_REACTIVE_POWER;


// PointId = 027120   Analogue Point
      L     "IMAC_KONGSBERG_OUT".adw[477];
      RND   ;
      T     "PMA_KONGSBERG_SEND".GEN_7_WDG_TEMP_L1;


// PointId = 027130   Analogue Point
      L     "IMAC_KONGSBERG_OUT".adw[478];
      RND   ;
      T     "PMA_KONGSBERG_SEND".GEN_7_WDG_TEMP_L2;


// PointId = 027140   Analogue Point
      L     "IMAC_KONGSBERG_OUT".adw[479];
      RND   ;
      T     "PMA_KONGSBERG_SEND".GEN_7_WDG_TEMP_L3;


// PointId = 027150   Analogue Point
      L     "IMAC_KONGSBERG_OUT".adw[480];
      RND   ;
      T     "PMA_KONGSBERG_SEND".GEN_7_BEAR_TEMP_DRIVEEND;


// PointId = 027160   Analogue Point
      L     "IMAC_KONGSBERG_OUT".adw[481];
      RND   ;
      T     "PMA_KONGSBERG_SEND".GEN_7_BEAR_TEMP_NONDRIVE;


// PointId = 027170   Analogue Point
      L     "IMAC_KONGSBERG_OUT".adw[482];
      RND   ;
      T     "PMA_KONGSBERG_SEND".GEN_7_COOL_AIR_TEMP;


// PointId = 027180   Analogue Point
      L     "IMAC_KONGSBERG_OUT".adw[483];
      RND   ;
      T     "PMA_KONGSBERG_SEND".GEN_7_COOL_WATER_TEMP;
NETWORK
TITLE = GEN 7 Binary Points
// *** TELEGRAM 4 ***   Block 5
//  PointId = 027100   Binary Point
      L     "IMAC_KONGSBERG_OUT".adw[484];
      T     #temp_dwd;
      U     L      3.0;
      =     "PMA_KONGSBERG_SEND".GEN_7_MCB_STATUS;


// PointId = 027110   Binary Point
      L     "IMAC_KONGSBERG_OUT".adw[485];
      T     #temp_dwd;
      U     L      3.0;
      =     "PMA_KONGSBERG_SEND".GEN_7_MCB_SEC_TO_GND;


// PointId = 027190   Binary Point
      L     "IMAC_KONGSBERG_OUT".adw[486];
      T     #temp_dwd;
      U     L      3.0;
      =     "PMA_KONGSBERG_SEND".GEN_7_OVER_CURRENT_TRIP;


// PointId = 027200   Binary Point
      L     "IMAC_KONGSBERG_OUT".adw[487];
      T     #temp_dwd;
      U     L      3.0;
      =     "PMA_KONGSBERG_SEND".GEN_7_REVERSE_POWER_TRIP;


// PointId = 027210   Binary Point
      L     "IMAC_KONGSBERG_OUT".adw[488];
      T     #temp_dwd;
      U     L      3.0;
      =     "PMA_KONGSBERG_SEND".GEN_7_SHORT_CIRCUIT_TRIP;


// PointId = 027240   Binary Point
      L     "IMAC_KONGSBERG_OUT".adw[489];
      T     #temp_dwd;
      U     L      3.0;
      =     "PMA_KONGSBERG_SEND".GEN_7_DIFF_PROT_TRIP;


// PointId = 027260   Binary Point
      L     "IMAC_KONGSBERG_OUT".adw[490];
      T     #temp_dwd;
      U     L      3.0;
      =     "PMA_KONGSBERG_SEND".GEN_7_PREFERENTIAL_TRIP;


// PointId = 027270   Binary Point
      L     "IMAC_KONGSBERG_OUT".adw[491];
      T     #temp_dwd;
      U     L      3.0;
      =     "PMA_KONGSBERG_SEND".GEN_7_BREAKER_TRIP;


// PointId = 027290   Binary Point
      L     "IMAC_KONGSBERG_OUT".adw[492];
      T     #temp_dwd;
      U     L      3.0;
      =     "PMA_KONGSBERG_SEND".GEN_7_PMA_71_FAULT;


// PointId = 027310   Binary Point
      L     "IMAC_KONGSBERG_OUT".adw[493];
      T     #temp_dwd;
      U     L      3.0;
      =     "PMA_KONGSBERG_SEND".GEN_7_W_LEAK_AIR_COOL;


// PointId = 027300   Analogue Point
      L     "IMAC_KONGSBERG_OUT".adw[494];
      RND   ;
      T     "PMA_KONGSBERG_SEND".GEN_7_PMA_71_STATUS;
NETWORK
TITLE = GEN 8 Analogue Points
// *** TELEGRAM 4 ***   Block 6
// PointId = 028010   Analogue Point
      L     "IMAC_KONGSBERG_OUT".adw[495];
      RND   ;
      T     "PMA_KONGSBERG_SEND".GEN_8_VOLTAGE_L1_L2;


// PointId = 028020   Analogue Point
      L     "IMAC_KONGSBERG_OUT".adw[496];
      RND   ;
      T     "PMA_KONGSBERG_SEND".GEN_8_VOLTAGE_L1_L3;


// PointId = 028030   Analogue Point
      L     "IMAC_KONGSBERG_OUT".adw[497];
      RND   ;
      T     "PMA_KONGSBERG_SEND".GEN_8_VOLTAGE_L2_L3;


// PointId = 028040   Analogue Point
      L     "IMAC_KONGSBERG_OUT".adw[498];
      RND   ;
      T     "PMA_KONGSBERG_SEND".GEN_8_CURRENT_L1_L2;


// PointId = 028051   Analogue Point
      L     "IMAC_KONGSBERG_OUT".adw[499];
      RND   ;
      T     "PMA_KONGSBERG_SEND".GEN_8_CURRENT_L1_L3;


// PointId = 028060   Analogue Point
      L     "IMAC_KONGSBERG_OUT".adw[500];
      RND   ;
      T     "PMA_KONGSBERG_SEND".GEN_8_CURRENT_L2_L3;


// PointId = 028070   Analogue Point
      L     "IMAC_KONGSBERG_OUT".adw[501];
      RND   ;
      T     "PMA_KONGSBERG_SEND".GEN_8_ACTIVE_POWER;


// PointId = 028080   Analogue Point
      L     "IMAC_KONGSBERG_OUT".adw[502];
      RND   ;
      T     "PMA_KONGSBERG_SEND".GEN_8_POWER_FACTOR;


// PointId = 028090   Analogue Point
      L     "IMAC_KONGSBERG_OUT".adw[503];
      RND   ;
      T     "PMA_KONGSBERG_SEND".GEN_8_REACTIVE_POWER;


// PointId = 028120   Analogue Point
      L     "IMAC_KONGSBERG_OUT".adw[504];
      RND   ;
      T     "PMA_KONGSBERG_SEND".GEN_8_WDG_TEMP_L1;


// PointId = 028130   Analogue Point
      L     "IMAC_KONGSBERG_OUT".adw[505];
      RND   ;
      T     "PMA_KONGSBERG_SEND".GEN_8_WDG_TEMP_L2;


// PointId = 028140   Analogue Point
      L     "IMAC_KONGSBERG_OUT".adw[506];
      RND   ;
      T     "PMA_KONGSBERG_SEND".GEN_8_WDG_TEMP_L3;


// PointId = 028150   Analogue Point
      L     "IMAC_KONGSBERG_OUT".adw[507];
      RND   ;
      T     "PMA_KONGSBERG_SEND".GEN_8_BEAR_TEMP_DRIVEEND;


// PointId = 028160   Analogue Point
      L     "IMAC_KONGSBERG_OUT".adw[508];
      RND   ;
      T     "PMA_KONGSBERG_SEND".GEN_8_BEAR_TEMP_NONDRIVE;


// PointId = 028170   Analogue Point
      L     "IMAC_KONGSBERG_OUT".adw[509];
      RND   ;
      T     "PMA_KONGSBERG_SEND".GEN_8_COOL_AIR_TEMP;


// PointId = 028180   Analogue Point
      L     "IMAC_KONGSBERG_OUT".adw[510];
      RND   ;
      T     "PMA_KONGSBERG_SEND".GEN_8_COOL_WATER_TEMP;
NETWORK
TITLE = GEN 8 Binary Points
// *** TELEGRAM 4 ***   Block 7
// PointId = 028100   Binary Point
      L     "IMAC_KONGSBERG_OUT".adw[511];
      T     #temp_dwd;
      U     L      3.0;
      =     "PMA_KONGSBERG_SEND".GEN_8_MCB_STATUS;


// PointId = 028110   Binary Point
      L     "IMAC_KONGSBERG_OUT".adw[512];
      T     #temp_dwd;
      U     L      3.0;
      =     "PMA_KONGSBERG_SEND".GEN_8_MCB_SEC_TO_GND;


// PointId = 028190   Binary Point
      L     "IMAC_KONGSBERG_OUT".adw[513];
      T     #temp_dwd;
      U     L      3.0;
      =     "PMA_KONGSBERG_SEND".GEN_8_OVER_CURRENT_TRIP;


// PointId = 028200   Binary Point
      L     "IMAC_KONGSBERG_OUT".adw[514];
      T     #temp_dwd;
      U     L      3.0;
      =     "PMA_KONGSBERG_SEND".GEN_8_REVERSE_POWER_TRIP;


// PointId = 028210   Binary Point
      L     "IMAC_KONGSBERG_OUT".adw[515];
      T     #temp_dwd;
      U     L      3.0;
      =     "PMA_KONGSBERG_SEND".GEN_8_SHORT_CIRCUIT_TRIP;


// PointId = 028240   Binary Point
      L     "IMAC_KONGSBERG_OUT".adw[516];
      T     #temp_dwd;
      U     L      3.0;
      =     "PMA_KONGSBERG_SEND".GEN_8_DIFF_PROT_TRIP;


// PointId = 028260   Binary Point
      L     "IMAC_KONGSBERG_OUT".adw[517];
      T     #temp_dwd;
      U     L      3.0;
      =     "PMA_KONGSBERG_SEND".GEN_8_PREFERENTIAL_TRIP;


// PointId = 028270   Binary Point
      L     "IMAC_KONGSBERG_OUT".adw[518];
      T     #temp_dwd;
      U     L      3.0;
      =     "PMA_KONGSBERG_SEND".Spare_4_201_3;


// PointId = 028290   Binary Point
      L     "IMAC_KONGSBERG_OUT".adw[519];
      T     #temp_dwd;
      U     L      3.0;
      =     "PMA_KONGSBERG_SEND".GEN_8_PMA_71_FAULT;


// PointId = 028310   Binary Point
      L     "IMAC_KONGSBERG_OUT".adw[520];
      T     #temp_dwd;
      U     L      3.0;
      =     "PMA_KONGSBERG_SEND".GEN_8_W_LEAK_AIR_COOL;


// PointId = 028300   Analogue Point
      L     "IMAC_KONGSBERG_OUT".adw[521];
      RND   ;
      T     "PMA_KONGSBERG_SEND".GEN_8_PMA_71_STATUS;
NETWORK
TITLE = DG 9 Binary Points
// *** TELEGRAM 5 ***   Block 2
// PointId = 019110   Binary Point
      L     "IMAC_KONGSBERG_OUT".adw[522];
      T     #temp_dwd;
      U     L      3.0;
      =     "PMA_KONGSBERG_SEND".DG_9_ENG_COOL_LVL;


// PointId = 019010   Binary Point
      L     "IMAC_KONGSBERG_OUT".adw[523];
      T     #temp_dwd;
      U     L      3.0;
      =     "PMA_KONGSBERG_SEND".DG_9_ENG_LO_PRESS;


// PointId = 019070   Binary Point
      L     "IMAC_KONGSBERG_OUT".adw[524];
      T     #temp_dwd;
      U     L      3.0;
      =     "PMA_KONGSBERG_SEND".DG_9_FO_FLT_DIFF_PR;


// PointId = 019080   Binary Point
      L     "IMAC_KONGSBERG_OUT".adw[525];
      T     #temp_dwd;
      U     L      3.0;
      =     "PMA_KONGSBERG_SEND".DG_9_LO_FLT_DIFF_PR;


// PointId = 019090   Binary Point
      L     "IMAC_KONGSBERG_OUT".adw[526];
      T     #temp_dwd;
      U     L      3.0;
      =     "PMA_KONGSBERG_SEND".DG_9_ENG_CRK_CASE_PR;


// PointId = 019130   Binary Point
      L     "IMAC_KONGSBERG_OUT".adw[527];
      T     #temp_dwd;
      U     L      3.0;
      =     "PMA_KONGSBERG_SEND".DG_9_MAR_GEAR_OIL_PR;


// PointId = 019020   Binary Point
      L     "IMAC_KONGSBERG_OUT".adw[528];
      T     #temp_dwd;
      U     L      3.0;
      =     "PMA_KONGSBERG_SEND".DG_9_ENG_JACK_WT_TEMP_HI;


// PointId = 019030   Binary Point
      L     "IMAC_KONGSBERG_OUT".adw[529];
      T     #temp_dwd;
      U     L      3.0;
      =     "PMA_KONGSBERG_SEND".DG_9_ENG_JACK_WT_TEMP_LO;


// PointId = 019060   Binary Point
      L     "IMAC_KONGSBERG_OUT".adw[530];
      T     #temp_dwd;
      U     L      3.0;
      =     "PMA_KONGSBERG_SEND".DG_9_ENG_EXH_GAS_TEMP;


// PointId = 019100   Binary Point
      L     "IMAC_KONGSBERG_OUT".adw[531];
      T     #temp_dwd;
      U     L      3.0;
      =     "PMA_KONGSBERG_SEND".DG_9_ENG_AFT_COOL_TEMP;


// PointId = 019120   Binary Point
      L     "IMAC_KONGSBERG_OUT".adw[532];
      T     #temp_dwd;
      U     L      3.0;
      =     "PMA_KONGSBERG_SEND".DG_9_MAR_GEAR_OIL_TEMP;


// PointId = 019040   Binary Point
      L     "IMAC_KONGSBERG_OUT".adw[533];
      T     #temp_dwd;
      U     L      3.0;
      =     "PMA_KONGSBERG_SEND".DG_9_ENG_OVERSPEED;


// PointId = 019140   Binary Point
      L     "IMAC_KONGSBERG_OUT".adw[534];
      T     #temp_dwd;
      U     L      3.0;
      =     "PMA_KONGSBERG_SEND".DG_9_EL_FUEL_INJ;


// PointId = 019050   Binary Point
      L     "IMAC_KONGSBERG_OUT".adw[535];
      T     #temp_dwd;
      U     L      3.0;
      =     "PMA_KONGSBERG_SEND".DG_9_ENG_AIR_RESTR;


// PointId = 019490   Binary Point
      L     "IMAC_KONGSBERG_OUT".adw[536];
      T     #temp_dwd;
      U     L      3.0;
      =     "PMA_KONGSBERG_SEND".DG_9_SYMMETRIZATION;
NETWORK
TITLE = DG 9 Analogue Points

// PointId = 019150   Analogue Point
      L     "IMAC_KONGSBERG_OUT".adw[537];
      RND   ;
      T     "PMA_KONGSBERG_SEND".DG_9_EXH_GAS_CYL_01_TEMP;



// PointId = 019160   Analogue Point
      L     "IMAC_KONGSBERG_OUT".adw[538];
      RND   ;
      T     "PMA_KONGSBERG_SEND".DG_9_EXH_GAS_CYL_02_TEMP;


// PointId = 019170   Analogue Point
      L     "IMAC_KONGSBERG_OUT".adw[539];
      RND   ;
      T     "PMA_KONGSBERG_SEND".DG_9_EXH_GAS_CYL_03_TEMP;


// PointId = 019180   Analogue Point
      L     "IMAC_KONGSBERG_OUT".adw[540];
      RND   ;
      T     "PMA_KONGSBERG_SEND".DG_9_EXH_GAS_CYL_04_TEMP;


// PointId = 019190   Analogue Point
      L     "IMAC_KONGSBERG_OUT".adw[541];
      RND   ;
      T     "PMA_KONGSBERG_SEND".DG_9_EXH_GAS_CYL_05_TEMP;


// PointId = 019200   Analogue Point
      L     "IMAC_KONGSBERG_OUT".adw[542];
      RND   ;
      T     "PMA_KONGSBERG_SEND".DG_9_EXH_GAS_CYL_06_TEMP;


// PointId = 019210   Analogue Point
      L     "IMAC_KONGSBERG_OUT".adw[543];
      RND   ;
      T     "PMA_KONGSBERG_SEND".DG_9_EXH_GAS_CYL_07_TEMP;


// PointId = 019220   Analogue Point
      L     "IMAC_KONGSBERG_OUT".adw[544];
      RND   ;
      T     "PMA_KONGSBERG_SEND".DG_9_EXH_GAS_CYL_08_TEMP;


// PointId = 019230   Analogue Point
      L     "IMAC_KONGSBERG_OUT".adw[545];
      RND   ;
      T     "PMA_KONGSBERG_SEND".DG_9_EXH_GAS_CYL_09_TEMP;


// PointId = 019240   Analogue Point
      L     "IMAC_KONGSBERG_OUT".adw[546];
      RND   ;
      T     "PMA_KONGSBERG_SEND".DG_9_EXH_GAS_CYL_10_TEMP;


// PointId = 019250   Analogue Point
      L     "IMAC_KONGSBERG_OUT".adw[547];
      RND   ;
      T     "PMA_KONGSBERG_SEND".DG_9_EXH_GAS_CYL_11_TEMP;


// PointId = 019260   Analogue Point
      L     "IMAC_KONGSBERG_OUT".adw[548];
      RND   ;
      T     "PMA_KONGSBERG_SEND".DG_9_EXH_GAS_CYL_12_TEMP;


// PointId = 019270   Analogue Point
      L     "IMAC_KONGSBERG_OUT".adw[549];
      RND   ;
      T     "PMA_KONGSBERG_SEND".DG_9_EXH_GAS_CYL_13_TEMP;


// PointId = 019280   Analogue Point
      L     "IMAC_KONGSBERG_OUT".adw[550];
      RND   ;
      T     "PMA_KONGSBERG_SEND".DG_9_EXH_GAS_CYL_14_TEMP;


// PointId = 019290   Analogue Point
      L     "IMAC_KONGSBERG_OUT".adw[551];
      RND   ;
      T     "PMA_KONGSBERG_SEND".DG_9_EXH_GAS_CYL_15_TEMP;


// PointId = 019300   Analogue Point
      L     "IMAC_KONGSBERG_OUT".adw[552];
      RND   ;
      T     "PMA_KONGSBERG_SEND".DG_9_EXH_GAS_CYL_16_TEMP;


// PointId = 019470   Analogue Point
      L     "IMAC_KONGSBERG_OUT".adw[553];
      RND   ;
      T     "PMA_KONGSBERG_SEND".DG_9_EXH_CYL_TEMP_MEAN;


// PointId = 019480   Analogue Point
      L     "IMAC_KONGSBERG_OUT".adw[554];
      RND   ;
      T     "PMA_KONGSBERG_SEND".DG_9_EXH_GAS_TEMP_COMP;

NETWORK
TITLE = GEN 9 Analogue Points
// *** TELEGRAM 5 ***   Block 4
// PointId = 029010   Analogue Point
      L     "IMAC_KONGSBERG_OUT".adw[555];
      RND   ;
      T     "PMA_KONGSBERG_SEND".GEN_9_VOLTAGE_L1_L2;


// PointId = 029020   Analogue Point
      L     "IMAC_KONGSBERG_OUT".adw[556];
      RND   ;
      T     "PMA_KONGSBERG_SEND".GEN_9_VOLTAGE_L1_L3;


// PointId = 029030   Analogue Point
      L     "IMAC_KONGSBERG_OUT".adw[557];
      RND   ;
      T     "PMA_KONGSBERG_SEND".GEN_9_VOLTAGE_L2_L3;


// PointId = 029040   Analogue Point
      L     "IMAC_KONGSBERG_OUT".adw[558];
      RND   ;
      T     "PMA_KONGSBERG_SEND".GEN_9_CURRENT_L1_L2;


// PointId = 029051   Analogue Point
      L     "IMAC_KONGSBERG_OUT".adw[559];
      RND   ;
      T     "PMA_KONGSBERG_SEND".GEN_9_CURRENT_L1_L3;


// PointId = 029060   Analogue Point
      L     "IMAC_KONGSBERG_OUT".adw[560];
      RND   ;
      T     "PMA_KONGSBERG_SEND".GEN_9_CURRENT_L2_L3;


// PointId = 029070   Analogue Point
      L     "IMAC_KONGSBERG_OUT".adw[561];
      RND   ;
      T     "PMA_KONGSBERG_SEND".GEN_9_ACTIVE_POWER;


// PointId = 029080   Analogue Point
      L     "IMAC_KONGSBERG_OUT".adw[562];
      RND   ;
      T     "PMA_KONGSBERG_SEND".GEN_9_POWER_FACTOR;


// PointId = 029090   Analogue Point
      L     "IMAC_KONGSBERG_OUT".adw[563];
      RND   ;
      T     "PMA_KONGSBERG_SEND".GEN_9_REACTIVE_POWER;


// PointId = 029120   Analogue Point
      L     "IMAC_KONGSBERG_OUT".adw[564];
      RND   ;
      T     "PMA_KONGSBERG_SEND".GEN_9_WDG_TEMP_L1;


// PointId = 029130   Analogue Point
      L     "IMAC_KONGSBERG_OUT".adw[565];
      RND   ;
      T     "PMA_KONGSBERG_SEND".GEN_9_WDG_TEMP_L2;


// PointId = 029140   Analogue Point
      L     "IMAC_KONGSBERG_OUT".adw[566];
      RND   ;
      T     "PMA_KONGSBERG_SEND".GEN_9_WDG_TEMP_L3;


// PointId = 029150   Analogue Point
      L     "IMAC_KONGSBERG_OUT".adw[567];
      RND   ;
      T     "PMA_KONGSBERG_SEND".GEN_9_BEAR_TEMP_DRIVEEND;


// PointId = 029160   Analogue Point
      L     "IMAC_KONGSBERG_OUT".adw[568];
      RND   ;
      T     "PMA_KONGSBERG_SEND".GEN_9_BEAR_TEMP_NONDRIVE;


// PointId = 029170   Analogue Point
      L     "IMAC_KONGSBERG_OUT".adw[569];
      RND   ;
      T     "PMA_KONGSBERG_SEND".GEN_9_COOL_AIR_TEMP;


// PointId = 029180   Analogue Point
      L     "IMAC_KONGSBERG_OUT".adw[570];
      RND   ;
      T     "PMA_KONGSBERG_SEND".GEN_9_COOL_WATER_TEMP;
NETWORK
TITLE = GEN 9 Binary Points
// *** TELEGRAM 5 ***   Block 5
// PointId = 029100   Binary Point
      L     "IMAC_KONGSBERG_OUT".adw[571];
      T     #temp_dwd;
      U     L      3.0;
      =     "PMA_KONGSBERG_SEND".GEN_9_MCB_STATUS;


// PointId = 029110   Binary Point
      L     "IMAC_KONGSBERG_OUT".adw[572];
      T     #temp_dwd;
      U     L      3.0;
      =     "PMA_KONGSBERG_SEND".GEN_9_MCB_SEC_TO_GND;


// PointId = 029190   Binary Point
      L     "IMAC_KONGSBERG_OUT".adw[573];
      T     #temp_dwd;
      U     L      3.0;
      =     "PMA_KONGSBERG_SEND".GEN_9_OVER_CURRENT_TRIP;


// PointId = 029200   Binary Point
      L     "IMAC_KONGSBERG_OUT".adw[574];
      T     #temp_dwd;
      U     L      3.0;
      =     "PMA_KONGSBERG_SEND".GEN_9_REVERSE_POWER_TRIP;


// PointId = 029210   Binary Point
      L     "IMAC_KONGSBERG_OUT".adw[575];
      T     #temp_dwd;
      U     L      3.0;
      =     "PMA_KONGSBERG_SEND".GEN_9_SHORT_CIRCUIT_TRIP;


// PointId = 029240   Binary Point
      L     "IMAC_KONGSBERG_OUT".adw[576];
      T     #temp_dwd;
      U     L      3.0;
      =     "PMA_KONGSBERG_SEND".GEN_9_DIFF_PROT_TRIP;


// PointId = 029260   Binary Point
      L     "IMAC_KONGSBERG_OUT".adw[577];
      T     #temp_dwd;
      U     L      3.0;
      =     "PMA_KONGSBERG_SEND".GEN_9_PREFERENTIAL_TRIP;


// PointId = 029270   Binary Point
      L     "IMAC_KONGSBERG_OUT".adw[578];
      T     #temp_dwd;
      U     L      3.0;
      =     "PMA_KONGSBERG_SEND".GEN_9_BREAKER_TRIP;



// PointId = 029290   Binary Point
      L     "IMAC_KONGSBERG_OUT".adw[579];
      T     #temp_dwd;
      U     L      3.0;
      =     "PMA_KONGSBERG_SEND".GEN_9_PMA_71_FAULT;


// PointId = 029310   Binary Point
      L     "IMAC_KONGSBERG_OUT".adw[580];
      T     #temp_dwd;
      U     L      3.0;
      =     "PMA_KONGSBERG_SEND".GEN_9_W_LEAK_AIR_COOL;


// PointId = 029300   Analogue Point
      L     "IMAC_KONGSBERG_OUT".adw[581];
      RND   ;
      T     "PMA_KONGSBERG_SEND".GEN_9_PMA_71_STATUS;
NETWORK
TITLE =
// *** TELEGRAM 1 ***   Block 8
// PointId = 020051   Analogue Point
      L     "IMAC_KONGSBERG_OUT".adw[582];
      RND   ;
      T     "PMA_KONGSBERG_SEND".LV_TRANSF_1_WDG_L1_TEMP;


// PointId = 020060   Analogue Point
      L     "IMAC_KONGSBERG_OUT".adw[583];
      RND   ;
      T     "PMA_KONGSBERG_SEND".LV_TRANSF_1_WDG_L2_TEMP;


// PointId = 020070   Analogue Point
      L     "IMAC_KONGSBERG_OUT".adw[584];
      RND   ;
      T     "PMA_KONGSBERG_SEND".LV_TRANSF_1_WDG_L3_TEMP;


// PointId = 020080   Analogue Point
      L     "IMAC_KONGSBERG_OUT".adw[585];
      RND   ;
      T     "PMA_KONGSBERG_SEND".LV_TRANSF_2_WDG_L1_TEMP;


// PointId = 020090   Analogue Point
      L     "IMAC_KONGSBERG_OUT".adw[586];
      RND   ;
      T     "PMA_KONGSBERG_SEND".LV_TRANSF_2_WDG_L2_TEMP;


// PointId = 020100   Analogue Point
      L     "IMAC_KONGSBERG_OUT".adw[587];
      RND   ;
      T     "PMA_KONGSBERG_SEND".LV_TRANSF_2_WDG_L3_TEMP;


// PointId = 051170   Analogue Point
      L     "IMAC_KONGSBERG_OUT".adw[588];
      RND   ;
      T     "PMA_KONGSBERG_SEND".STRT_AIR_PRESS_BOTTLE_1;


// PointId = 051180   Analogue Point
      L     "IMAC_KONGSBERG_OUT".adw[589];
      RND   ;
      T     "PMA_KONGSBERG_SEND".STRT_AIR_PRESS_BOTTLE_2;


// PointId = 051140   Analogue Point
      L     "IMAC_KONGSBERG_OUT".adw[590];
      RND   ;
      T     "PMA_KONGSBERG_SEND".STRT_AIR_BOT_CAT_PRESS;

END_FUNCTION

